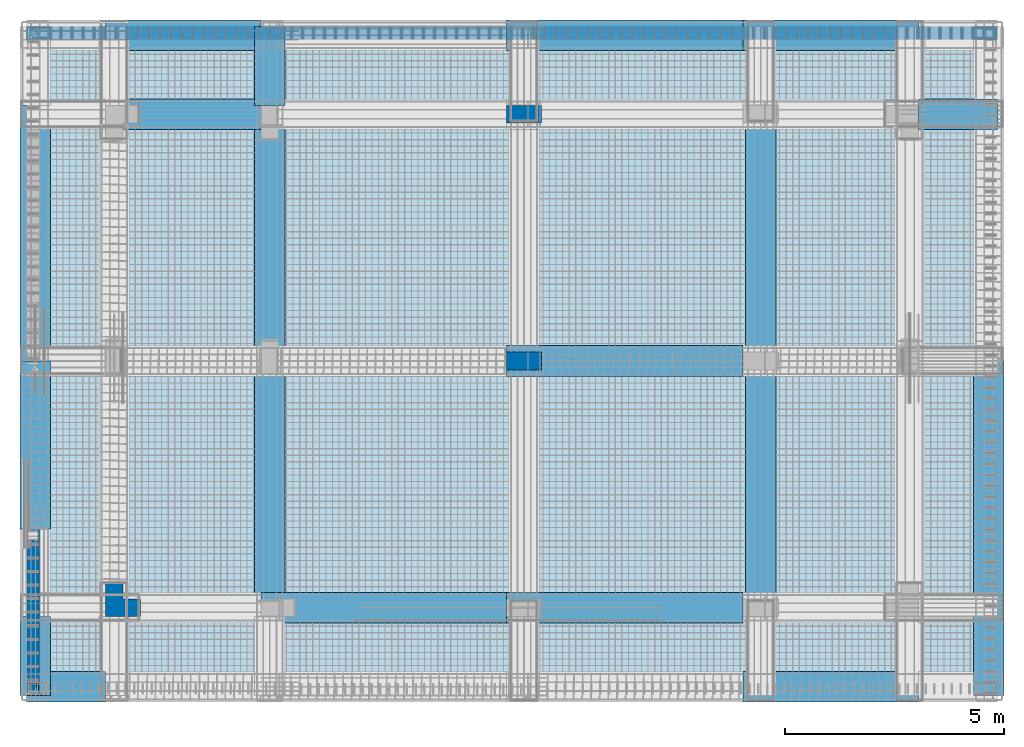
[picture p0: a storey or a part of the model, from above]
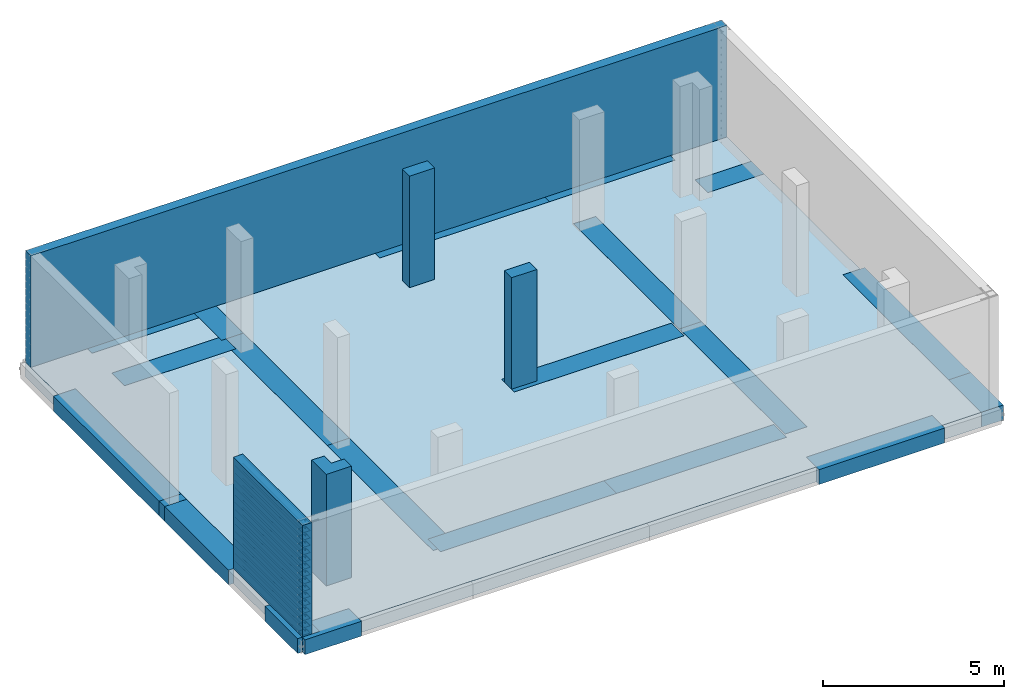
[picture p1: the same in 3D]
Properties of the parts of a building model (IFC4), part 1 of 3

# File
Description: ViewDefinition [CoordinationView]
Made in: IFC file generated by ModeSt (Tecnisoft s.a.s.)

# IfcBuildingStorey (4)
In: Palazzina
Name | Elevation (m)
Storey 0 | 0
Storey 1 | 3.75
Storey 2 | 7
Storey 3 | 11.08

# IfcBeam: 10 R 80x24 T (15)
Type - PredefinedType: BEAM; Material: Calcestruzzo classe C28/35
Description: 10 R 80x24 T - Cemento armato
Pset_BeamCommon - LoadBearing: yes
BaseQuantities - ?: 0.192 m2
Name | In | BaseQuantities, ? (m3) | BaseQuantities, ? (m)
209 | Storey 2 | 1.11936 | 5.83
2 x 206 | Storey 2 | 1.11936 | 5.83
208 | Storey 2 | 1.11936 | 5.83
203 | Storey 2 | 0.4896 | 2.55
203 | Storey 2 | 0.6816 | 3.55
203 | Storey 2 | 1.0368 | 5.4
203 | Storey 2 | 0.5856 | 3.05
203 | Storey 2 | 0.768 | 4
2 x 307 | Storey 3 | 1.13703 | 5.92204
2 x 306 | Storey 3 | 1.13703 | 5.92204
2 x 305 | Storey 3 | 1.13703 | 5.92204

# IfcBeam: 3 R 30x50 T (73)
Type - PredefinedType: BEAM; Material: Calcestruzzo classe C28/35
Description: 3 R 30x50 T - Cemento armato
Pset_BeamCommon - LoadBearing: yes
BaseQuantities - ?: 0.15 m2
Name | In | BaseQuantities, ? (m3) | BaseQuantities, ? (m)
104 | Storey 1 | 0.81 | 5.4
2 x 113 | Storey 1 | 0.8745 | 5.83
111 | Storey 1 | 0.8745 | 5.83
111 | Storey 1 | 0.4095 | 2.73
104 | Storey 1 | 0.435 | 2.9
104 | Storey 1 | 0.405 | 2.7
104 | Storey 1 | 0.6 | 4
2 x 114 | Storey 1 | 0.8745 | 5.83
111 | Storey 1 | 0.465 | 3.1
104 | Storey 1 | 0.5325 | 3.55
2 x 115 | Storey 1 | 0.2025 | 1.35
2 x 106 | Storey 1 | 0.2025 | 1.35
109 | Storey 1 | 0.465 | 3.1
2 x 109 | Storey 1 | 0.2025 | 1.35
2 x 114 | Storey 1 | 0.2025 | 1.35
102 | Storey 1 | 0.6 | 4
2 x 102 | Storey 1 | 0.2025 | 1.35
2 x 113 | Storey 1 | 0.2025 | 1.35
2 x 111 | Storey 1 | 0.2025 | 1.35
2 x 104 | Storey 1 | 0.2025 | 1.35
106 | Storey 1 | 0.6 | 4
106 | Storey 1 | 0.435 | 2.9
106 | Storey 1 | 0.345 | 2.3
109 | Storey 1 | 0.8745 | 5.83
106 | Storey 1 | 0.81 | 5.4
102 | Storey 1 | 0.81 | 5.4
109 | Storey 1 | 0.4095 | 2.73
2 x 115 | Storey 1 | 0.8745 | 5.83
106 | Storey 1 | 0.1875 | 1.25
102 | Storey 1 | 0.5325 | 3.55
102 | Storey 1 | 0.84 | 5.6
106 | Storey 1 | 0.405 | 2.7
201 | Storey 2 | 0.81 | 5.4
204 | Storey 2 | 0.5325 | 3.55
204 | Storey 2 | 0.3825 | 2.55
204 | Storey 2 | 0.4575 | 3.05
204 | Storey 2 | 0.81 | 5.4
201 | Storey 2 | 0.6 | 4
201 | Storey 2 | 0.84 | 5.6
2 x 205 | Storey 2 | 0.8745 | 5.83
201 | Storey 2 | 0.5325 | 3.55
204 | Storey 2 | 0.6 | 4
210 | Storey 2 | 0.6375 | 4.25
210 | Storey 2 | 0.237 | 1.58
210 | Storey 2 | 0.8745 | 5.83
301 | Storey 3 | 0.81 | 5.4
302 | Storey 3 | 0.81 | 5.4
303 | Storey 3 | 0.5325 | 3.55
303 | Storey 3 | 0.81 | 5.4
2 x 308 | Storey 3 | 0.888305 | 5.92204
303 | Storey 3 | 0.84 | 5.6
302 | Storey 3 | 0.6 | 4
301 | Storey 3 | 0.6 | 4
301 | Storey 3 | 0.84 | 5.6
301 | Storey 3 | 0.5325 | 3.55
2 x 304 | Storey 3 | 0.888305 | 5.92204
303 | Storey 3 | 0.6 | 4
302 | Storey 3 | 0.5325 | 3.55
302 | Storey 3 | 0.84 | 5.6

# IfcBeam: 6 R 30x24 T (6)
Type - PredefinedType: BEAM; Material: Calcestruzzo classe C28/35
Description: 6 R 30x24 T - Cemento armato
Pset_BeamCommon - LoadBearing: yes
BaseQuantities - ?: 0.072 m2
Name | In | BaseQuantities, ? (m3) | BaseQuantities, ? (m)
112 | Storey 1 | 0.41976 | 5.83
105 | Storey 1 | 0.1656 | 2.3
105 | Storey 1 | 0.09 | 1.25
110 | Storey 1 | 0.2232 | 3.1
207 | Storey 2 | 0.31752 | 4.41
207 | Storey 2 | 0.10224 | 1.42

# IfcBeam: 8 R 70x50 T (60)
In: Storey 0
Type - PredefinedType: BEAM; Material: Calcestruzzo classe C28/35
Description: 8 R 70x50 T - Cemento armato
Pset_BeamCommon - LoadBearing: yes
BaseQuantities - ?: 0.35 m2
Name | BaseQuantities, ? (m3) | BaseQuantities, ? (m)
506 | 0.105 | 0.3
2 x 501 | 0.63 | 1.8
501 | 1.89 | 5.4
2 x 512 | 0.63 | 1.8
2 x 505 | 0.63 | 1.8
505 | 1.4 | 4
2 x 506 | 0.63 | 1.8
2 x 507 | 0.63 | 1.8
2 x 502 | 0.63 | 1.8
506 | 1.2355 | 3.53
2 x 508 | 0.63 | 1.8
2 x 509 | 0.63 | 1.8
502 | 1.96 | 5.6
501 | 1.96 | 5.6
2 x 510 | 0.63 | 1.8
502 | 1.89 | 5.4
2 x 511 | 0.63 | 1.8
2 x 508 | 2.0405 | 5.83
2 x 509 | 2.0405 | 5.83
2 x 511 | 2.0405 | 5.83
2 x 512 | 2.0405 | 5.83
506 | 0.7 | 2
2 x 507 | 2.0405 | 5.83
2 x 510 | 2.0405 | 5.83
502 | 1.4 | 4
2 x 504 | 0.63 | 1.8
505 | 1.89 | 5.4
504 | 1.89 | 5.4
505 | 1.96 | 5.6
504 | 1.96 | 5.6
505 | 1.2425 | 3.55
2 x 503 | 0.63 | 1.8
503 | 1.89 | 5.4
502 | 1.2425 | 3.55
501 | 1.4 | 4
503 | 1.4 | 4
504 | 1.4 | 4
506 | 2.0405 | 5.83
503 | 1.96 | 5.6
503 | 1.2425 | 3.55
504 | 1.2425 | 3.55
501 | 1.2425 | 3.55

# IfcBeam: 9 R 30x24 T (3)
In: Storey 1
Type - PredefinedType: BEAM; Material: Calcestruzzo classe C28/35
Description: 9 R 30x24 T - Cemento armato
Pset_BeamCommon - LoadBearing: yes
BaseQuantities - ?: 0.072 m2
Name | BaseQuantities, ? (m3) | BaseQuantities, ? (m)
108 | 0.25416 | 3.53
108 | 0.2736 | 3.8
108 | 0.57096 | 7.93

# IfcColumn: 1 R 80x40 P (12)
Type - PredefinedType: COLUMN; Material: Calcestruzzo classe C28/35
Description: 1 R 80x40 P - Cemento armato
Pset_ColumnCommon - LoadBearing: yes
BaseQuantities - ?: 0.32 m2
Name | In | BaseQuantities, ? (m3) | BaseQuantities, ? (m)
12 | Storey 0 | 1.2 | 3.75
6 | Storey 0 | 1.2 | 3.75
7 | Storey 0 | 1.2 | 3.75
10 | Storey 0 | 1.2 | 3.75
7 | Storey 1 | 1.04 | 3.25
6 | Storey 1 | 1.04 | 3.25
12 | Storey 1 | 1.04 | 3.25
10 | Storey 1 | 1.04 | 3.25
12 | Storey 2 | 0.9728 | 3.04
10 | Storey 2 | 1.3056 | 4.08
7 | Storey 2 | 1.3056 | 4.08
6 | Storey 2 | 1.3056 | 4.08

# IfcColumn: 2 R 40x80 P (21)
Type - PredefinedType: COLUMN; Material: Calcestruzzo classe C28/35
Description: 2 R 40x80 P - Cemento armato
Pset_ColumnCommon - LoadBearing: yes
BaseQuantities - ?: 0.32 m2
Name | In | BaseQuantities, ? (m3) | BaseQuantities, ? (m)
9 | Storey 0 | 1.2 | 3.75
4 | Storey 0 | 1.2 | 3.75
13 | Storey 0 | 1.2 | 3.75
14 | Storey 0 | 1.2 | 3.75
2 | Storey 0 | 1.2 | 3.75
3 | Storey 0 | 1.2 | 3.75
8 | Storey 0 | 1.2 | 3.75
9 | Storey 1 | 1.04 | 3.25
4 | Storey 1 | 1.04 | 3.25
13 | Storey 1 | 1.04 | 3.25
8 | Storey 1 | 1.04 | 3.25
2 | Storey 1 | 1.04 | 3.25
3 | Storey 1 | 1.04 | 3.25
14 | Storey 1 | 1.04 | 3.25
14 | Storey 2 | 0.9728 | 3.04
13 | Storey 2 | 0.9728 | 3.04
9 | Storey 2 | 1.3056 | 4.08
2 | Storey 2 | 0.9728 | 3.04
3 | Storey 2 | 0.9728 | 3.04
4 | Storey 2 | 0.9728 | 3.04
8 | Storey 2 | 1.3056 | 4.08

# IfcColumn: 4 L 40x40x80x40 P (6)
Type - PredefinedType: COLUMN; Material: Calcestruzzo classe C28/35
Description: 4 L 40x40x80x40 P - Cemento armato
Pset_ColumnCommon - LoadBearing: yes
BaseQuantities - ?: 0.48 m2
Name | In | BaseQuantities, ? (m3) | BaseQuantities, ? (m)
1 | Storey 0 | 1.8 | 3.75
5 | Storey 0 | 1.8 | 3.75
1 | Storey 1 | 1.56 | 3.25
5 | Storey 1 | 1.56 | 3.25
1 | Storey 2 | 1.4592 | 3.04
5 | Storey 2 | 1.4592 | 3.04

# IfcColumn: 5 Ldx 40x40x80x40 P (6)
Type - PredefinedType: COLUMN; Material: Calcestruzzo classe C28/35
Description: 5 Ldx 40x40x80x40 P - Cemento armato
Pset_ColumnCommon - LoadBearing: yes
BaseQuantities - ?: 0.48 m2
Name | In | BaseQuantities, ? (m3) | BaseQuantities, ? (m)
15 | Storey 0 | 1.8 | 3.75
11 | Storey 0 | 1.8 | 3.75
11 | Storey 1 | 1.56 | 3.25
15 | Storey 1 | 1.56 | 3.25
11 | Storey 2 | 1.4592 | 3.04
15 | Storey 2 | 1.4592 | 3.04

# IfcFooting: 3 Spess. 0.5 S W
In: Storey 0
Type - PredefinedType: STRIP_FOOTING
Description: 3 Spess. 0.5 S W; Material: Calcestruzzo classe C28/35 0.5 m
Pset_WallCommon - LoadBearing: yes
BaseQuantities - ?: 169.005 m3

# IfcReinforcingBar (563)
SteelGrade: B450C
Name | In | NominalDiameter (m) | CrossSectionArea (m2) | BarLength (m)
5 x  | Storey 0 | 0.012 | 0.0001131 | 3.957
5 x  | Storey 0 | 0.012 | 0.0001131 | 1.18782
2 x  | Storey 0 | 0.01 | 0.00007854 | 22.09
5 x  | Storey 0 | 0.01 | 0.00007854 | 1.21121
4 x  | Storey 0 | 0.016 | 0.00020106 | 3.952
4 x  | Storey 0 | 0.016 | 0.00020106 | 1.17543
 | Storey 0 | 0.01 | 0.00007854 | 1.18177
 | Storey 0 | 0.01 | 0.00007854 | 15.2
3 x  | Storey 0 | 0.01 | 0.00007854 | 1.18178
 | Storey 0 | 0.01 | 0.00007854 | 7.87
 | Storey 0 | 0.01 | 0.00007854 | 3.74
10 x  | Storey 2 | 0.02 | 0.00031416 | 1.59754
4 x  | Storey 2 | 0.016 | 0.00020106 | 1.60193
5 x  | Storey 2 | 0.02 | 0.00031416 | 4.73591
4 x  | Storey 2 | 0.016 | 0.00020106 | 4.73591
6 x  | Storey 2 | 0.02 | 0.00031416 | 4.23591
4 x  | Storey 2 | 0.016 | 0.00020106 | 4.23591
10 x  | Storey 2 | 0.016 | 0.00020106 | 3.32943
2 x  | Storey 2 | 0.008 | 0.000050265 | 0.978432
19 x  | Storey 2 | 0.008 | 0.000050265 | 2.37879
 | Storey 2 | 0.008 | 0.000050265 | 0.578429
4 x  | Storey 2 | 0.018 | 0.00025447 | 1.51973
4 x  | Storey 2 | 0.018 | 0.00025447 | 4.47
3 x  | Storey 2 | 0.018 | 0.00025447 | 3.97
 | Storey 2 | 0.008 | 0.000050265 | 1.42681
7 x  | Storey 2 | 0.008 | 0.000050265 | 0.978429
 | Storey 2 | 0.018 | 0.00025447 | 3.32723
3 x  | Storey 2 | 0.008 | 0.000050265 | 1.42683
2 x  | Storey 2 | 0.008 | 0.000050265 | 0.978428
3 x  | Storey 2 | 0.008 | 0.000050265 | 1.4215
5 x  | Storey 2 | 0.02 | 0.00031416 | 4.55
4 x  | Storey 2 | 0.02 | 0.00031416 | 4.05
 | Storey 2 | 0.008 | 0.000050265 | 1.23963
2 x  | Storey 2 | 0.008 | 0.000050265 | 0.97843
3 x  | Storey 2 | 0.008 | 0.000050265 | 1.23324
 | Storey 2 | 0.008 | 0.000050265 | 0.978434
 | Storey 2 | 0.008 | 0.000050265 | 0.578426
2 x  | Storey 2 | 0.018 | 0.00025447 | 4.36723
 | Storey 2 | 0.008 | 0.000050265 | 1.36284
3 x  | Storey 2 | 0.016 | 0.00020106 | 4.36943
2 x  | Storey 2 | 0.008 | 0.000050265 | 1.4295
 | Storey 2 | 0.008 | 0.000050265 | 1.42417
 | Storey 2 | 0.016 | 0.00020106 | 1.44193
 | Storey 2 | 0.016 | 0.00020106 | 4.39
 | Storey 2 | 0.016 | 0.00020106 | 3.89
4 x  | Storey 2 | 0.01 | 0.00007854 | 2.3898
 | Storey 2 | 0.01 | 0.00007854 | 1.23626
2 x  | Storey 2 | 0.01 | 0.00007854 | 0.98443
2 x  | Storey 2 | 0.008 | 0.000050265 | 1.42416
2 x  | Storey 2 | 0.016 | 0.00020106 | 1.52193
2 x  | Storey 2 | 0.016 | 0.00020106 | 4.47
 | Storey 2 | 0.018 | 0.00025447 | 4.13732
 | Storey 2 | 0.016 | 0.00020106 | 4.13732
 | Storey 2 | 0.01 | 0.00007854 | 1.42451
 | Storey 2 | 0.008 | 0.000050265 | 1.36283
 | Storey 2 | 0.008 | 0.000050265 | 0.578428
 | Storey 2 | 0.016 | 0.00020106 | 3.97
 | Storey 2 | 0.02 | 0.00031416 | 3.32504
 | Storey 2 | 0.008 | 0.000050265 | 1.23964
 | Storey 2 | 0.008 | 0.000050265 | 0.978433
 | Storey 2 | 0.008 | 0.000050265 | 0.57843
 | Storey 2 | 0.01 | 0.00007854 | 0.984432
 | Storey 2 | 0.01 | 0.00007854 | 0.584429
 | Storey 0 | 0.014 | 0.00015394 | 22.8032
 | Storey 0 | 0.014 | 0.00015394 | 15.9132
 | Storey 2 | 0.014 | 0.00015394 | 1.51321
 | Storey 2 | 0.014 | 0.00015394 | 13.9632
 | Storey 2 | 0.014 | 0.00015394 | 1.53321
 | Storey 2 | 0.014 | 0.00015394 | 3.11321
7 x  | Storey 1 | 0.008 | 0.000050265 | 1.5868
2 x  | Storey 1 | 0.016 | 0.00020106 | 8.29448
 | Storey 1 | 0.016 | 0.00020106 | 8.19121
2 x  | Storey 1 | 0.018 | 0.00025447 | 6.59121
 | Storey 1 | 0.02 | 0.00031416 | 5.19121
 | Storey 1 | 0.016 | 0.00020106 | 3.58285
 | Storey 1 | 0.02 | 0.00031416 | 11.8812
2 x  | Storey 1 | 0.018 | 0.00025447 | 11.9512
2 x  | Storey 1 | 0.016 | 0.00020106 | 3.36285
4 x  | Storey 1 | 0.012 | 0.0001131 | 2.52121
 | Storey 1 | 0.012 | 0.0001131 | 4.72121
3 x  | Storey 1 | 0.012 | 0.0001131 | 6.77121
2 x  | Storey 1 | 0.012 | 0.0001131 | 6.57121
3 x  | Storey 1 | 0.012 | 0.0001131 | 4.37121
3 x  | Storey 1 | 0.014 | 0.00015394 | 2.69121
 | Storey 1 | 0.016 | 0.00020106 | 2.79448
 | Storey 1 | 0.018 | 0.00025447 | 8.19121
 | Storey 1 | 0.02 | 0.00031416 | 5.69121
2 x  | Storey 1 | 0.016 | 0.00020106 | 3.18285
 | Storey 1 | 0.018 | 0.00025447 | 11.9812
 | Storey 1 | 0.016 | 0.00020106 | 8.32121
 | Storey 1 | 0.02 | 0.00031416 | 7.19121
 | Storey 1 | 0.016 | 0.00020106 | 2.96285
4 x  | Storey 1 | 0.012 | 0.0001131 | 2.12121
2 x  | Storey 1 | 0.012 | 0.0001131 | 4.32121
 | Storey 1 | 0.012 | 0.0001131 | 6.57122
 | Storey 1 | 0.018 | 0.00025447 | 3.19121
 | Storey 1 | 0.016 | 0.00020106 | 2.29448
 | Storey 1 | 0.008 | 0.000050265 | 1.06683
 | Storey 1 | 0.016 | 0.00020106 | 4.09721
 | Storey 1 | 0.018 | 0.00025447 | 11.5912
 | Storey 1 | 0.018 | 0.00025447 | 8.42831
 | Storey 1 | 0.018 | 0.00025447 | 6.8643
 | Storey 1 | 0.016 | 0.00020106 | 9.19121
 | Storey 1 | 0.02 | 0.00031416 | 7.19122
 | Storey 1 | 0.018 | 0.00025447 | 4.19122
 | Storey 1 | 0.014 | 0.00015394 | 3.19121
3 x  | Storey 1 | 0.008 | 0.000050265 | 1.06682
 | Storey 1 | 0.016 | 0.00020106 | 8.54503
 | Storey 1 | 0.016 | 0.00020106 | 7.94503
 | Storey 1 | 0.018 | 0.00025447 | 9.00197
 | Storey 1 | 0.018 | 0.00025447 | 9.14976
 | Storey 1 | 0.018 | 0.00025447 | 9.90276
 | Storey 1 | 0.018 | 0.00025447 | 9.16121
2 x  | Storey 1 | 0.016 | 0.00020106 | 4.59121
3 x  | Storey 1 | 0.012 | 0.0001131 | 6.50121
3 x  | Storey 1 | 0.012 | 0.0001131 | 6.70121
 | Storey 1 | 0.016 | 0.00020106 | 3.64721
 | Storey 1 | 0.018 | 0.00025447 | 9.0443
 | Storey 1 | 0.018 | 0.00025447 | 9.84121
 | Storey 1 | 0.018 | 0.00025447 | 9.84741
 | Storey 1 | 0.018 | 0.00025447 | 9.49121
 | Storey 1 | 0.018 | 0.00025447 | 4.17109
2 x  | Storey 1 | 0.016 | 0.00020106 | 3.95121
 | Storey 1 | 0.012 | 0.0001131 | 2.52122
 | Storey 1 | 0.02 | 0.00031416 | 6.22721
 | Storey 1 | 0.014 | 0.00015394 | 1.97562
2 x  | Storey 1 | 0.018 | 0.00025447 | 8.9443
 | Storey 1 | 0.018 | 0.00025447 | 7.64739
2 x  | Storey 1 | 0.018 | 0.00025447 | 9.42831
 | Storey 1 | 0.018 | 0.00025447 | 8.18739
 | Storey 1 | 0.016 | 0.00020106 | 3.93121
 | Storey 1 | 0.016 | 0.00020106 | 3.63121
2 x  | Storey 1 | 0.012 | 0.0001131 | 6.40121
 | Storey 1 | 0.008 | 0.000050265 | 1.58681
 | Storey 1 | 0.018 | 0.00025447 | 8.71476
 | Storey 1 | 0.016 | 0.00020106 | 4.15121
 | Storey 1 | 0.018 | 0.00025447 | 10.0912
 | Storey 1 | 0.016 | 0.00020106 | 9.11285
 | Storey 1 | 0.02 | 0.00031416 | 9.69122
 | Storey 1 | 0.016 | 0.00020106 | 4.59122
4 x  | Storey 2 | 0.008 | 0.000050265 | 1.5868
2 x  | Storey 2 | 0.018 | 0.00025447 | 11.9412
 | Storey 2 | 0.02 | 0.00031416 | 11.0958
 | Storey 2 | 0.018 | 0.00025447 | 6.52121
 | Storey 2 | 0.018 | 0.00025447 | 5.87121
 | Storey 2 | 0.018 | 0.00025447 | 11.9612
 | Storey 2 | 0.018 | 0.00025447 | 11.9512
 | Storey 2 | 0.018 | 0.00025447 | 6.58121
 | Storey 2 | 0.018 | 0.00025447 | 6.33121
2 x  | Storey 2 | 0.012 | 0.0001131 | 4.37121
 | Storey 2 | 0.012 | 0.0001131 | 4.72121
2 x  | Storey 2 | 0.012 | 0.0001131 | 6.77121
 | Storey 2 | 0.012 | 0.0001131 | 6.57122
4 x  | Storey 2 | 0.008 | 0.000050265 | 1.57214
 | Storey 2 | 0.016 | 0.00020106 | 10.0912
 | Storey 2 | 0.016 | 0.00020106 | 8.19121
 | Storey 2 | 0.016 | 0.00020106 | 10.5912
2 x  | Storey 2 | 0.018 | 0.00025447 | 7.19121
 | Storey 2 | 0.016 | 0.00020106 | 7.19121
 | Storey 2 | 0.02 | 0.00031416 | 7.19121
 | Storey 2 | 0.02 | 0.00031416 | 3.59121
2 x  | Storey 2 | 0.018 | 0.00025447 | 3.59121
 | Storey 2 | 0.016 | 0.00020106 | 3.59121
 | Storey 2 | 0.02 | 0.00031416 | 11.9012
 | Storey 2 | 0.018 | 0.00025447 | 6.94121
 | Storey 2 | 0.018 | 0.00025447 | 5.45976
 | Storey 2 | 0.018 | 0.00025447 | 11.9712
 | Storey 2 | 0.018 | 0.00025447 | 11.4598
 | Storey 2 | 0.018 | 0.00025447 | 6.40121
 | Storey 2 | 0.018 | 0.00025447 | 5.95121
 | Storey 2 | 0.012 | 0.0001131 | 6.57121
 | Storey 2 | 0.012 | 0.0001131 | 4.32121
2 x  | Storey 2 | 0.02 | 0.00031416 | 12.4312
2 x  | Storey 2 | 0.02 | 0.00031416 | 11.9912
 | Storey 2 | 0.012 | 0.0001131 | 6.50121
2 x  | Storey 2 | 0.012 | 0.0001131 | 6.70121
 | Storey 2 | 0.016 | 0.00020106 | 11.9072
 | Storey 2 | 0.02 | 0.00031416 | 8.69121
 | Storey 2 | 0.018 | 0.00025447 | 8.69121
4 x  | Storey 2 | 0.018 | 0.00025447 | 4.59121
2 x  | Storey 2 | 0.016 | 0.00020106 | 4.59121
3 x  | Storey 2 | 0.02 | 0.00031416 | 4.59121
 | Storey 2 | 0.008 | 0.000050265 | 1.06682
 | Storey 2 | 0.016 | 0.00020106 | 6.47721
2 x  | Storey 2 | 0.02 | 0.00031416 | 4.64876
2 x  | Storey 2 | 0.018 | 0.00025447 | 4.64876
 | Storey 2 | 0.012 | 0.0001131 | 5.72788
5 x  | Storey 3 | 0.008 | 0.000050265 | 1.5868
 | Storey 3 | 0.018 | 0.00025447 | 11.9598
 | Storey 3 | 0.018 | 0.00025447 | 10.9598
 | Storey 3 | 0.018 | 0.00025447 | 6.33121
 | Storey 3 | 0.018 | 0.00025447 | 5.59121
2 x  | Storey 3 | 0.018 | 0.00025447 | 10.7443
2 x  | Storey 3 | 0.018 | 0.00025447 | 10.4943
 | Storey 3 | 0.018 | 0.00025447 | 5.97121
 | Storey 3 | 0.018 | 0.00025447 | 5.3443
 | Storey 3 | 0.012 | 0.0001131 | 4.72121
3 x  | Storey 3 | 0.012 | 0.0001131 | 4.40121
2 x  | Storey 3 | 0.012 | 0.0001131 | 6.60122
 | Storey 3 | 0.012 | 0.0001131 | 6.80122
 | Storey 3 | 0.016 | 0.00020106 | 11.0912
 | Storey 3 | 0.016 | 0.00020106 | 8.29448
 | Storey 3 | 0.02 | 0.00031416 | 5.09121
2 x  | Storey 3 | 0.012 | 0.0001131 | 4.32121
2 x  | Storey 3 | 0.012 | 0.0001131 | 6.80121
 | Storey 3 | 0.016 | 0.00020106 | 2.79448
2 x  | Storey 3 | 0.02 | 0.00031416 | 11.0912
 | Storey 3 | 0.016 | 0.00020106 | 5.09122
 | Storey 3 | 0.018 | 0.00025447 | 5.09121
 | Storey 3 | 0.02 | 0.00031416 | 10.6258
 | Storey 3 | 0.02 | 0.00031416 | 10.8758
 | Storey 3 | 0.016 | 0.00020106 | 5.21285
 | Storey 3 | 0.02 | 0.00031416 | 5.02576
 | Storey 3 | 0.012 | 0.0001131 | 6.60121
 | Storey 3 | 0.02 | 0.00031416 | 4.19122
 | Storey 3 | 0.016 | 0.00020106 | 4.19122
 | Storey 3 | 0.018 | 0.00025447 | 4.19122
 | Storey 3 | 0.016 | 0.00020106 | 2.29448
 | Storey 3 | 0.014 | 0.00015394 | 3.19122
2 x  | Storey 3 | 0.018 | 0.00025447 | 7.49081
2 x  | Storey 3 | 0.02 | 0.00031416 | 12.1783
 | Storey 3 | 0.018 | 0.00025447 | 12.1783
2 x  | Storey 3 | 0.012 | 0.0001131 | 6.16672
2 x  | Storey 3 | 0.012 | 0.0001131 | 6.36987
3 x  | Storey 3 | 0.008 | 0.000050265 | 1.57214
 | Storey 3 | 0.016 | 0.00020106 | 7.589
 | Storey 3 | 0.016 | 0.00020106 | 7.09316
5 x  | Storey 3 | 0.02 | 0.00031416 | 8.69116
3 x  | Storey 3 | 0.016 | 0.00020106 | 8.69116
 | Storey 3 | 0.018 | 0.00025447 | 4.21654
 | Storey 3 | 0.016 | 0.00020106 | 4.21654
3 x  | Storey 3 | 0.02 | 0.00031416 | 4.59273
2 x  | Storey 3 | 0.018 | 0.00025447 | 4.59273
2 x  | Storey 3 | 0.018 | 0.00025447 | 6.63307
2 x  | Storey 3 | 0.018 | 0.00025447 | 8.69116
 | Storey 3 | 0.018 | 0.00025447 | 4.26733
 | Storey 3 | 0.016 | 0.00020106 | 4.26733
2 x  | Storey 3 | 0.02 | 0.00031416 | 4.58906
 | Storey 3 | 0.016 | 0.00020106 | 4.58906
3 x  | Storey 3 | 0.016 | 0.00020106 | 4.59273
 | Storey 3 | 0.018 | 0.00025447 | 4.58906
 | Storey 3 | 0.02 | 0.00031416 | 7.62227
 | Storey 3 | 0.02 | 0.00031416 | 7.62226
2 x  | Storey 3 | 0.016 | 0.00020106 | 3.58906
 | Storey 3 | 0.016 | 0.00020106 | 2.44898
8 x  | Storey 0 | 0.01 | 0.00007854 | 1.85514
2 x  | Storey 0 | 0.016 | 0.00020106 | 11.7241
2 x  | Storey 0 | 0.016 | 0.00020106 | 6.70876
2 x  | Storey 0 | 0.016 | 0.00020106 | 6.79003
2 x  | Storey 0 | 0.012 | 0.0001131 | 6.87621
2 x  | Storey 0 | 0.012 | 0.0001131 | 6.65712
2 x  | Storey 0 | 0.012 | 0.0001131 | 11.8103
 | Storey 0 | 0.016 | 0.00020106 | 9.35121
 | Storey 0 | 0.016 | 0.00020106 | 7.30121
 | Storey 0 | 0.016 | 0.00020106 | 7.60121
3 x  | Storey 0 | 0.016 | 0.00020106 | 2.81503
 | Storey 0 | 0.016 | 0.00020106 | 9.22121
 | Storey 0 | 0.02 | 0.00031416 | 7.15121
 | Storey 0 | 0.016 | 0.00020106 | 7.15121
 | Storey 0 | 0.016 | 0.00020106 | 9.48122
4 x  | Storey 0 | 0.012 | 0.0001131 | 3.66121
 | Storey 0 | 0.012 | 0.0001131 | 4.84121
 | Storey 0 | 0.012 | 0.0001131 | 6.92621
3 x  | Storey 0 | 0.012 | 0.0001131 | 6.6603
2 x  | Storey 0 | 0.012 | 0.0001131 | 3.99121
 | Storey 0 | 0.016 | 0.00020106 | 10.1312
 | Storey 0 | 0.016 | 0.00020106 | 6.97121
 | Storey 0 | 0.016 | 0.00020106 | 7.71121
 | Storey 0 | 0.016 | 0.00020106 | 9.97121
 | Storey 0 | 0.016 | 0.00020106 | 6.81831
 | Storey 0 | 0.016 | 0.00020106 | 9.50121
4 x  | Storey 0 | 0.012 | 0.0001131 | 3.26121
2 x  | Storey 0 | 0.012 | 0.0001131 | 4.90121
 | Storey 0 | 0.012 | 0.0001131 | 7.35122
 | Storey 0 | 0.012 | 0.0001131 | 4.49121
4 x  | Storey 0 | 0.01 | 0.00007854 | 1.85515
 | Storey 0 | 0.016 | 0.00020106 | 7.97121
 | Storey 0 | 0.016 | 0.00020106 | 8.82121
 | Storey 0 | 0.016 | 0.00020106 | 7.82121
 | Storey 0 | 0.016 | 0.00020106 | 7.50121
 | Storey 0 | 0.016 | 0.00020106 | 9.61122
 | Storey 0 | 0.016 | 0.00020106 | 8.86121
 | Storey 0 | 0.012 | 0.0001131 | 4.44121
 | Storey 0 | 0.012 | 0.0001131 | 7.35121
 | Storey 0 | 0.016 | 0.00020106 | 10.0912
 | Storey 0 | 0.016 | 0.00020106 | 4.57285
 | Storey 0 | 0.02 | 0.00031416 | 4.94649
 | Storey 0 | 0.018 | 0.00025447 | 2.19121
3 x  | Storey 0 | 0.016 | 0.00020106 | 2.19121
 | Storey 0 | 0.018 | 0.00025447 | 8.41076
 | Storey 0 | 0.012 | 0.0001131 | 4.52121
 | Storey 0 | 0.012 | 0.0001131 | 9.03121
2 x  | Storey 0 | 0.016 | 0.00020106 | 9.09121
4 x  | Storey 0 | 0.016 | 0.00020106 | 8.64503
4 x  | Storey 0 | 0.016 | 0.00020106 | 8.59121
2 x  | Storey 0 | 0.02 | 0.00031416 | 2.19121
2 x  | Storey 0 | 0.012 | 0.0001131 | 6.02121
3 x  | Storey 0 | 0.012 | 0.0001131 | 5.92336
 | Storey 0 | 0.016 | 0.00020106 | 9.83121
 | Storey 0 | 0.016 | 0.00020106 | 9.65121
 | Storey 0 | 0.016 | 0.00020106 | 9.63121
 | Storey 0 | 0.016 | 0.00020106 | 9.68121
 | Storey 0 | 0.012 | 0.0001131 | 6.52121
 | Storey 0 | 0.016 | 0.00020106 | 9.86121
2 x  | Storey 0 | 0.016 | 0.00020106 | 9.59121
 | Storey 0 | 0.016 | 0.00020106 | 9.73121
 | Storey 0 | 0.016 | 0.00020106 | 9.61121
2 x  | Storey 0 | 0.012 | 0.0001131 | 6.98121
 | Storey 0 | 0.016 | 0.00020106 | 9.34121
 | Storey 0 | 0.016 | 0.00020106 | 9.56121
 | Storey 0 | 0.016 | 0.00020106 | 9.13121
 | Storey 0 | 0.012 | 0.0001131 | 3.66122
 | Storey 0 | 0.012 | 0.0001131 | 8.73122

# IfcSlab: 1 Hs 0.3 Sc 0.04 Qps 390 Qpn 250 QA 200 (10)
In: Storey 1
Type - PredefinedType: FLOOR; Material: Concrete
Description: 1 Hs 0.3 Sc 0.04 Qps 390 Qpn 250 QA 200 - Altezza solaio 0.300000 - Spessore cappa 0.040000 -
Pset_SlabCommon - LoadBearing: yes
BaseQuantities - ?: 0.3 m
Name | BaseQuantities, ? (m2) | BaseQuantities, ? (m3)
100 | 20.6965 | 6.20895
101 | -23.32 | -6.996
103 | 31.482 | 9.4446
104 | 32.648 | 9.7944
105 | -15.741 | -4.7223
106 | -9.6915 | -2.90745
107 | -3.875 | -1.1625
110 | -31.482 | -9.4446
111 | 23.32 | 6.996
112 | -16.907 | -5.0721

# IfcSlab: 2 Hs 0.3 Sc 0.04 Qps 300 Qpn 90 QA 200 (8)
In: Storey 3
Type - PredefinedType: FLOOR; Material: Concrete
Description: 2 Hs 0.3 Sc 0.04 Qps 300 Qpn 90 QA 200 - Altezza solaio 0.300000 - Spessore cappa 0.040000 -
Pset_SlabCommon - LoadBearing: yes
BaseQuantities - ?: 0.3 m
Name | BaseQuantities, ? (m2) | BaseQuantities, ? (m3)
300 | 31.482 | 9.4446
301 | 31.482 | 9.4446
302 | 20.6965 | 6.20895
303 | 32.648 | 9.7944
304 | 23.32 | 6.996
305 | 20.6965 | 6.20895
306 | 32.648 | 9.7944
307 | 23.32 | 6.996

# IfcSlab: 2 Spess. 0.2 S F
In: Storey 2
Type - PredefinedType: BASESLAB
Description: 2 Spess. 0.2 S F; Material: Calcestruzzo classe C28/35 0.2 m
Pset_WallCommon - LoadBearing: yes
BaseQuantities - ?: 8.30999 m3

# IfcSlab: 3 Hs 0.1 Qps 250 Qpn 100 QA 200 (16)
In: Storey 1
Type - PredefinedType: FLOOR; Material: Concrete
Description: 3 Hs 0.1 Qps 250 Qpn 100 QA 200 - Altezza solaio 0.100000 - Spessore cappa 0.000000 -
Pset_SlabCommon - LoadBearing: yes
BaseQuantities - ?: 0.1 m
Name | BaseQuantities, ? (m2) | BaseQuantities, ? (m3)
102 | -7.29 | -0.729
108 | -7.56 | -0.756
109 | -4.7925 | -0.47925
113 | -5.4 | -0.54
114 | -1.8225 | -0.18225
115 | -7.8705 | -0.78705
116 | 7.8705 | 0.78705
117 | -1.8225 | -0.18225
118 | -5.4 | -0.54
119 | -7.29 | -0.729
120 | -7.56 | -0.756
121 | -4.7925 | -0.47925
122 | -1.8225 | -0.18225
123 | 7.8705 | 0.78705
124 | -7.8705 | -0.78705
125 | -1.8225 | -0.18225

# IfcSlab: 4 Hs 0.3 Sc 0.04 Qps 300 Qpn 250 QA 200 (6)
In: Storey 2
Type - PredefinedType: FLOOR; Material: Concrete
Description: 4 Hs 0.3 Sc 0.04 Qps 300 Qpn 250 QA 200 - Altezza solaio 0.300000 - Spessore cappa 0.040000 -
Pset_SlabCommon - LoadBearing: yes
BaseQuantities - ?: 0.3 m
Name | BaseQuantities, ? (m2) | BaseQuantities, ? (m3)
200 | 23.32 | 6.996
201 | 31.482 | 9.4446
202 | -14.8665 | -4.45995
203 | 32.648 | 9.7944
204 | 20.6965 | 6.20895
205 | -20.6965 | -6.20895

# IfcWall (21)
Pset_WallCommon - LoadBearing: yes
Name | In
106 | Storey 1
110 | Storey 1
111 | Storey 1
104 | Storey 1
103 | Storey 1
112 | Storey 1
113 | Storey 1
108 | Storey 1
107 | Storey 1
203 | Storey 2
204 | Storey 2
206 | Storey 2
105 | Storey 2
308 | Storey 2
102 | Storey 2
101 | Storey 2
213 | Storey 2
212 | Storey 2
109 | Storey 2
208 | Storey 2
207 | Storey 2

# IfcWallStandardCase: 1 Spess. 0.3 P F (5)
In: Storey 0
Type - PredefinedType: STANDARD
Material: Calcestruzzo classe C28/35 0.3 m
Pset_WallCommon - LoadBearing: yes
BaseQuantities - ?: 3.75 m
Name | Description | BaseQuantities, ? (m2) | BaseQuantities, ? (m3)
113 | Wall number 113 | 1.14 | 4.275
112 | Wall number 112 | 2.379 | 8.92125
111 | Wall number 111 | 6.645 | 24.9188
110 | Wall number 110 | 4.578 | 17.1675
109 | Wall number 109 | 6.645 | 24.9188

# IfcReinforcingBarType, no part of this type: type
PredefinedType: MAIN; NominalDiameter: 0.012 m; CrossSectionArea: 0.0001131 m2; BarLength: 3.957 m; Material: Steel

# IfcReinforcingBarType, no part of this type: type
PredefinedType: MAIN; NominalDiameter: 0.012 m; CrossSectionArea: 0.0001131 m2; BarLength: 1.18782 m; Material: Steel

# IfcReinforcingBarType, no part of this type: type
PredefinedType: LIGATURE; NominalDiameter: 0.01 m; CrossSectionArea: 0.00007854 m2; BarLength: 22.09 m; Material: Steel

# IfcReinforcingBarType, no part of this type: type
PredefinedType: LIGATURE; NominalDiameter: 0.01 m; CrossSectionArea: 0.00007854 m2; BarLength: 1.21121 m; Material: Steel

# IfcReinforcingBarType, no part of this type: type
PredefinedType: MAIN; NominalDiameter: 0.016 m; CrossSectionArea: 0.00020106 m2; BarLength: 3.952 m; Material: Steel

# IfcReinforcingBarType, no part of this type: type
PredefinedType: MAIN; NominalDiameter: 0.016 m; CrossSectionArea: 0.00020106 m2; BarLength: 1.17543 m; Material: Steel

# IfcReinforcingBarType, no part of this type: type
PredefinedType: LIGATURE; NominalDiameter: 0.01 m; CrossSectionArea: 0.00007854 m2; BarLength: 1.18177 m; Material: Steel

# IfcReinforcingBarType, no part of this type: type
PredefinedType: MAIN; NominalDiameter: 0.012 m; CrossSectionArea: 0.0001131 m2; BarLength: 3.957 m; Material: Steel

# IfcReinforcingBarType, no part of this type: type
PredefinedType: MAIN; NominalDiameter: 0.012 m; CrossSectionArea: 0.0001131 m2; BarLength: 1.18782 m; Material: Steel

# IfcReinforcingBarType, no part of this type: type
PredefinedType: LIGATURE; NominalDiameter: 0.01 m; CrossSectionArea: 0.00007854 m2; BarLength: 15.2 m; Material: Steel

# IfcReinforcingBarType, no part of this type: type
PredefinedType: LIGATURE; NominalDiameter: 0.01 m; CrossSectionArea: 0.00007854 m2; BarLength: 1.21121 m; Material: Steel

# IfcReinforcingBarType, no part of this type: type
PredefinedType: MAIN; NominalDiameter: 0.012 m; CrossSectionArea: 0.0001131 m2; BarLength: 3.957 m; Material: Steel

# IfcReinforcingBarType, no part of this type: type
PredefinedType: MAIN; NominalDiameter: 0.012 m; CrossSectionArea: 0.0001131 m2; BarLength: 1.18782 m; Material: Steel

# IfcReinforcingBarType, no part of this type: type
PredefinedType: LIGATURE; NominalDiameter: 0.01 m; CrossSectionArea: 0.00007854 m2; BarLength: 22.09 m; Material: Steel

# IfcReinforcingBarType, no part of this type: type
PredefinedType: LIGATURE; NominalDiameter: 0.01 m; CrossSectionArea: 0.00007854 m2; BarLength: 1.21121 m; Material: Steel

# IfcReinforcingBarType, no part of this type: type
PredefinedType: MAIN; NominalDiameter: 0.016 m; CrossSectionArea: 0.00020106 m2; BarLength: 3.952 m; Material: Steel

# IfcReinforcingBarType, no part of this type: type
PredefinedType: MAIN; NominalDiameter: 0.016 m; CrossSectionArea: 0.00020106 m2; BarLength: 1.17543 m; Material: Steel

# IfcReinforcingBarType, no part of this type: type
PredefinedType: LIGATURE; NominalDiameter: 0.01 m; CrossSectionArea: 0.00007854 m2; BarLength: 1.18178 m; Material: Steel

# IfcReinforcingBarType, no part of this type: type
PredefinedType: MAIN; NominalDiameter: 0.012 m; CrossSectionArea: 0.0001131 m2; BarLength: 3.957 m; Material: Steel

# IfcReinforcingBarType, no part of this type: type
PredefinedType: MAIN; NominalDiameter: 0.012 m; CrossSectionArea: 0.0001131 m2; BarLength: 1.18782 m; Material: Steel

# IfcReinforcingBarType, no part of this type: type
PredefinedType: LIGATURE; NominalDiameter: 0.01 m; CrossSectionArea: 0.00007854 m2; BarLength: 7.87 m; Material: Steel

# IfcReinforcingBarType, no part of this type: type
PredefinedType: LIGATURE; NominalDiameter: 0.01 m; CrossSectionArea: 0.00007854 m2; BarLength: 1.21121 m; Material: Steel

# IfcReinforcingBarType, no part of this type: type
PredefinedType: MAIN; NominalDiameter: 0.016 m; CrossSectionArea: 0.00020106 m2; BarLength: 3.952 m; Material: Steel

# IfcReinforcingBarType, no part of this type: type
PredefinedType: MAIN; NominalDiameter: 0.016 m; CrossSectionArea: 0.00020106 m2; BarLength: 1.17543 m; Material: Steel

# IfcReinforcingBarType, no part of this type: type
PredefinedType: LIGATURE; NominalDiameter: 0.01 m; CrossSectionArea: 0.00007854 m2; BarLength: 1.18178 m; Material: Steel

# IfcReinforcingBarType, no part of this type: type
PredefinedType: MAIN; NominalDiameter: 0.012 m; CrossSectionArea: 0.0001131 m2; BarLength: 3.957 m; Material: Steel

# IfcReinforcingBarType, no part of this type: type
PredefinedType: MAIN; NominalDiameter: 0.012 m; CrossSectionArea: 0.0001131 m2; BarLength: 1.18782 m; Material: Steel

# IfcReinforcingBarType, no part of this type: type
PredefinedType: LIGATURE; NominalDiameter: 0.01 m; CrossSectionArea: 0.00007854 m2; BarLength: 3.74 m; Material: Steel

# IfcReinforcingBarType, no part of this type: type
PredefinedType: LIGATURE; NominalDiameter: 0.01 m; CrossSectionArea: 0.00007854 m2; BarLength: 1.21121 m; Material: Steel

# IfcReinforcingBarType, no part of this type: type
PredefinedType: MAIN; NominalDiameter: 0.016 m; CrossSectionArea: 0.00020106 m2; BarLength: 3.952 m; Material: Steel

# IfcReinforcingBarType, no part of this type: type
PredefinedType: MAIN; NominalDiameter: 0.016 m; CrossSectionArea: 0.00020106 m2; BarLength: 1.17543 m; Material: Steel

# IfcReinforcingBarType, no part of this type: type
PredefinedType: LIGATURE; NominalDiameter: 0.01 m; CrossSectionArea: 0.00007854 m2; BarLength: 1.18178 m; Material: Steel

# IfcReinforcingBarType, no part of this type: type
PredefinedType: MAIN; NominalDiameter: 0.02 m; CrossSectionArea: 0.00031416 m2; BarLength: 1.59754 m; Material: Steel

# IfcReinforcingBarType, no part of this type: type
PredefinedType: MAIN; NominalDiameter: 0.016 m; CrossSectionArea: 0.00020106 m2; BarLength: 1.60193 m; Material: Steel

# IfcReinforcingBarType, no part of this type: type
PredefinedType: MAIN; NominalDiameter: 0.02 m; CrossSectionArea: 0.00031416 m2; BarLength: 4.73591 m; Material: Steel

# IfcReinforcingBarType, no part of this type: type
PredefinedType: MAIN; NominalDiameter: 0.016 m; CrossSectionArea: 0.00020106 m2; BarLength: 4.73591 m; Material: Steel

# IfcReinforcingBarType, no part of this type: type
PredefinedType: MAIN; NominalDiameter: 0.02 m; CrossSectionArea: 0.00031416 m2; BarLength: 4.23591 m; Material: Steel

# IfcReinforcingBarType, no part of this type: type
PredefinedType: MAIN; NominalDiameter: 0.016 m; CrossSectionArea: 0.00020106 m2; BarLength: 4.23591 m; Material: Steel

# IfcReinforcingBarType, no part of this type: type
PredefinedType: MAIN; NominalDiameter: 0.016 m; CrossSectionArea: 0.00020106 m2; BarLength: 3.32943 m; Material: Steel

# IfcReinforcingBarType, no part of this type: type
PredefinedType: LIGATURE; NominalDiameter: 0.008 m; CrossSectionArea: 0.000050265 m2; BarLength: 0.978432 m; Material: Steel

# IfcReinforcingBarType, no part of this type: type
PredefinedType: LIGATURE; NominalDiameter: 0.008 m; CrossSectionArea: 0.000050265 m2; BarLength: 2.37879 m; Material: Steel

# IfcReinforcingBarType, no part of this type: type
PredefinedType: LIGATURE; NominalDiameter: 0.008 m; CrossSectionArea: 0.000050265 m2; BarLength: 0.578429 m; Material: Steel

# IfcReinforcingBarType, no part of this type: type
PredefinedType: LIGATURE; NominalDiameter: 0.008 m; CrossSectionArea: 0.000050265 m2; BarLength: 2.37879 m; Material: Steel

# IfcReinforcingBarType, no part of this type: type
PredefinedType: MAIN; NominalDiameter: 0.018 m; CrossSectionArea: 0.00025447 m2; BarLength: 1.51973 m; Material: Steel

# IfcReinforcingBarType, no part of this type: type
PredefinedType: MAIN; NominalDiameter: 0.018 m; CrossSectionArea: 0.00025447 m2; BarLength: 4.47 m; Material: Steel

# IfcReinforcingBarType, no part of this type: type
PredefinedType: MAIN; NominalDiameter: 0.018 m; CrossSectionArea: 0.00025447 m2; BarLength: 3.97 m; Material: Steel

# IfcReinforcingBarType, no part of this type: type
PredefinedType: MAIN; NominalDiameter: 0.016 m; CrossSectionArea: 0.00020106 m2; BarLength: 3.32943 m; Material: Steel

# IfcReinforcingBarType, no part of this type: type
PredefinedType: LIGATURE; NominalDiameter: 0.008 m; CrossSectionArea: 0.000050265 m2; BarLength: 1.42681 m; Material: Steel

# IfcReinforcingBarType, no part of this type: type
PredefinedType: LIGATURE; NominalDiameter: 0.008 m; CrossSectionArea: 0.000050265 m2; BarLength: 2.37879 m; Material: Steel

# IfcReinforcingBarType, no part of this type: type
PredefinedType: LIGATURE; NominalDiameter: 0.008 m; CrossSectionArea: 0.000050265 m2; BarLength: 0.978429 m; Material: Steel

# IfcReinforcingBarType, no part of this type: type
PredefinedType: MAIN; NominalDiameter: 0.018 m; CrossSectionArea: 0.00025447 m2; BarLength: 1.51973 m; Material: Steel

# IfcReinforcingBarType, no part of this type: type
PredefinedType: MAIN; NominalDiameter: 0.018 m; CrossSectionArea: 0.00025447 m2; BarLength: 4.47 m; Material: Steel

# IfcReinforcingBarType, no part of this type: type
PredefinedType: MAIN; NominalDiameter: 0.018 m; CrossSectionArea: 0.00025447 m2; BarLength: 3.97 m; Material: Steel

# IfcReinforcingBarType, no part of this type: type
PredefinedType: MAIN; NominalDiameter: 0.018 m; CrossSectionArea: 0.00025447 m2; BarLength: 3.32723 m; Material: Steel

# IfcReinforcingBarType, no part of this type: type
PredefinedType: MAIN; NominalDiameter: 0.016 m; CrossSectionArea: 0.00020106 m2; BarLength: 3.32943 m; Material: Steel

# IfcReinforcingBarType, no part of this type: type
PredefinedType: LIGATURE; NominalDiameter: 0.008 m; CrossSectionArea: 0.000050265 m2; BarLength: 1.42683 m; Material: Steel

# IfcReinforcingBarType, no part of this type: type
PredefinedType: LIGATURE; NominalDiameter: 0.008 m; CrossSectionArea: 0.000050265 m2; BarLength: 2.37879 m; Material: Steel

# IfcReinforcingBarType, no part of this type: type
PredefinedType: LIGATURE; NominalDiameter: 0.008 m; CrossSectionArea: 0.000050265 m2; BarLength: 0.978428 m; Material: Steel

# IfcReinforcingBarType, no part of this type: type
PredefinedType: LIGATURE; NominalDiameter: 0.008 m; CrossSectionArea: 0.000050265 m2; BarLength: 1.4215 m; Material: Steel

# IfcReinforcingBarType, no part of this type: type
PredefinedType: MAIN; NominalDiameter: 0.02 m; CrossSectionArea: 0.00031416 m2; BarLength: 1.59754 m; Material: Steel

# IfcReinforcingBarType, no part of this type: type
PredefinedType: MAIN; NominalDiameter: 0.02 m; CrossSectionArea: 0.00031416 m2; BarLength: 4.55 m; Material: Steel

# IfcReinforcingBarType, no part of this type: type
PredefinedType: MAIN; NominalDiameter: 0.02 m; CrossSectionArea: 0.00031416 m2; BarLength: 4.05 m; Material: Steel

# IfcReinforcingBarType, no part of this type: type
PredefinedType: MAIN; NominalDiameter: 0.016 m; CrossSectionArea: 0.00020106 m2; BarLength: 3.32943 m; Material: Steel

# IfcReinforcingBarType, no part of this type: type
PredefinedType: LIGATURE; NominalDiameter: 0.008 m; CrossSectionArea: 0.000050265 m2; BarLength: 2.37879 m; Material: Steel

# IfcReinforcingBarType, no part of this type: type
PredefinedType: LIGATURE; NominalDiameter: 0.008 m; CrossSectionArea: 0.000050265 m2; BarLength: 1.23963 m; Material: Steel

# IfcReinforcingBarType, no part of this type: type
PredefinedType: LIGATURE; NominalDiameter: 0.008 m; CrossSectionArea: 0.000050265 m2; BarLength: 0.97843 m; Material: Steel

# IfcReinforcingBarType, no part of this type: type
PredefinedType: LIGATURE; NominalDiameter: 0.008 m; CrossSectionArea: 0.000050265 m2; BarLength: 1.23324 m; Material: Steel

# IfcReinforcingBarType, no part of this type: type
PredefinedType: MAIN; NominalDiameter: 0.02 m; CrossSectionArea: 0.00031416 m2; BarLength: 1.59754 m; Material: Steel

# IfcReinforcingBarType, no part of this type: type
PredefinedType: MAIN; NominalDiameter: 0.016 m; CrossSectionArea: 0.00020106 m2; BarLength: 1.60193 m; Material: Steel

# IfcReinforcingBarType, no part of this type: type
PredefinedType: MAIN; NominalDiameter: 0.02 m; CrossSectionArea: 0.00031416 m2; BarLength: 4.73591 m; Material: Steel

# IfcReinforcingBarType, no part of this type: type
PredefinedType: MAIN; NominalDiameter: 0.016 m; CrossSectionArea: 0.00020106 m2; BarLength: 4.73591 m; Material: Steel

# IfcReinforcingBarType, no part of this type: type
PredefinedType: MAIN; NominalDiameter: 0.02 m; CrossSectionArea: 0.00031416 m2; BarLength: 4.23591 m; Material: Steel

# IfcReinforcingBarType, no part of this type: type
PredefinedType: MAIN; NominalDiameter: 0.016 m; CrossSectionArea: 0.00020106 m2; BarLength: 4.23591 m; Material: Steel

# IfcReinforcingBarType, no part of this type: type
PredefinedType: MAIN; NominalDiameter: 0.016 m; CrossSectionArea: 0.00020106 m2; BarLength: 3.32943 m; Material: Steel

# IfcReinforcingBarType, no part of this type: type
PredefinedType: LIGATURE; NominalDiameter: 0.008 m; CrossSectionArea: 0.000050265 m2; BarLength: 0.978434 m; Material: Steel

# IfcReinforcingBarType, no part of this type: type
PredefinedType: LIGATURE; NominalDiameter: 0.008 m; CrossSectionArea: 0.000050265 m2; BarLength: 0.578426 m; Material: Steel

# IfcReinforcingBarType, no part of this type: type
PredefinedType: LIGATURE; NominalDiameter: 0.008 m; CrossSectionArea: 0.000050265 m2; BarLength: 2.37879 m; Material: Steel

# IfcReinforcingBarType, no part of this type: type
PredefinedType: LIGATURE; NominalDiameter: 0.008 m; CrossSectionArea: 0.000050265 m2; BarLength: 2.37879 m; Material: Steel

# IfcReinforcingBarType, no part of this type: type
PredefinedType: MAIN; NominalDiameter: 0.02 m; CrossSectionArea: 0.00031416 m2; BarLength: 1.59754 m; Material: Steel

# IfcReinforcingBarType, no part of this type: type
PredefinedType: MAIN; NominalDiameter: 0.02 m; CrossSectionArea: 0.00031416 m2; BarLength: 4.55 m; Material: Steel

# IfcReinforcingBarType, no part of this type: type
PredefinedType: MAIN; NominalDiameter: 0.02 m; CrossSectionArea: 0.00031416 m2; BarLength: 4.23591 m; Material: Steel

# IfcReinforcingBarType, no part of this type: type
PredefinedType: MAIN; NominalDiameter: 0.018 m; CrossSectionArea: 0.00025447 m2; BarLength: 4.36723 m; Material: Steel

# IfcReinforcingBarType, no part of this type: type
PredefinedType: LIGATURE; NominalDiameter: 0.008 m; CrossSectionArea: 0.000050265 m2; BarLength: 2.37879 m; Material: Steel

# IfcReinforcingBarType, no part of this type: type
PredefinedType: LIGATURE; NominalDiameter: 0.008 m; CrossSectionArea: 0.000050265 m2; BarLength: 1.36284 m; Material: Steel

# IfcReinforcingBarType, no part of this type: type
PredefinedType: LIGATURE; NominalDiameter: 0.008 m; CrossSectionArea: 0.000050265 m2; BarLength: 1.42683 m; Material: Steel

# IfcReinforcingBarType, no part of this type: type
PredefinedType: LIGATURE; NominalDiameter: 0.008 m; CrossSectionArea: 0.000050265 m2; BarLength: 0.978429 m; Material: Steel

# IfcReinforcingBarType, no part of this type: type
PredefinedType: MAIN; NominalDiameter: 0.02 m; CrossSectionArea: 0.00031416 m2; BarLength: 1.59754 m; Material: Steel

# IfcReinforcingBarType, no part of this type: type
PredefinedType: MAIN; NominalDiameter: 0.02 m; CrossSectionArea: 0.00031416 m2; BarLength: 4.55 m; Material: Steel

# IfcReinforcingBarType, no part of this type: type
PredefinedType: MAIN; NominalDiameter: 0.02 m; CrossSectionArea: 0.00031416 m2; BarLength: 4.23591 m; Material: Steel

# IfcReinforcingBarType, no part of this type: type
PredefinedType: MAIN; NominalDiameter: 0.016 m; CrossSectionArea: 0.00020106 m2; BarLength: 4.36943 m; Material: Steel

# IfcReinforcingBarType, no part of this type: type
PredefinedType: LIGATURE; NominalDiameter: 0.008 m; CrossSectionArea: 0.000050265 m2; BarLength: 2.37879 m; Material: Steel

# IfcReinforcingBarType, no part of this type: type
PredefinedType: LIGATURE; NominalDiameter: 0.008 m; CrossSectionArea: 0.000050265 m2; BarLength: 0.978428 m; Material: Steel

# IfcReinforcingBarType, no part of this type: type
PredefinedType: LIGATURE; NominalDiameter: 0.008 m; CrossSectionArea: 0.000050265 m2; BarLength: 1.4295 m; Material: Steel

# IfcReinforcingBarType, no part of this type: type
PredefinedType: LIGATURE; NominalDiameter: 0.008 m; CrossSectionArea: 0.000050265 m2; BarLength: 1.42417 m; Material: Steel

# IfcReinforcingBarType, no part of this type: type
PredefinedType: MAIN; NominalDiameter: 0.016 m; CrossSectionArea: 0.00020106 m2; BarLength: 1.44193 m; Material: Steel

# IfcReinforcingBarType, no part of this type: type
PredefinedType: MAIN; NominalDiameter: 0.016 m; CrossSectionArea: 0.00020106 m2; BarLength: 4.39 m; Material: Steel

# IfcReinforcingBarType, no part of this type: type
PredefinedType: MAIN; NominalDiameter: 0.016 m; CrossSectionArea: 0.00020106 m2; BarLength: 3.89 m; Material: Steel

# IfcReinforcingBarType, no part of this type: type
PredefinedType: MAIN; NominalDiameter: 0.016 m; CrossSectionArea: 0.00020106 m2; BarLength: 4.36943 m; Material: Steel

# IfcReinforcingBarType, no part of this type: type
PredefinedType: LIGATURE; NominalDiameter: 0.008 m; CrossSectionArea: 0.000050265 m2; BarLength: 2.37879 m; Material: Steel

# IfcReinforcingBarType, no part of this type: type
PredefinedType: LIGATURE; NominalDiameter: 0.008 m; CrossSectionArea: 0.000050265 m2; BarLength: 1.23324 m; Material: Steel

# IfcReinforcingBarType, no part of this type: type
PredefinedType: LIGATURE; NominalDiameter: 0.008 m; CrossSectionArea: 0.000050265 m2; BarLength: 0.978429 m; Material: Steel

# IfcReinforcingBarType, no part of this type: type
PredefinedType: LIGATURE; NominalDiameter: 0.01 m; CrossSectionArea: 0.00007854 m2; BarLength: 2.3898 m; Material: Steel

# IfcReinforcingBarType, no part of this type: type
PredefinedType: LIGATURE; NominalDiameter: 0.01 m; CrossSectionArea: 0.00007854 m2; BarLength: 1.23626 m; Material: Steel

# IfcReinforcingBarType, no part of this type: type
PredefinedType: LIGATURE; NominalDiameter: 0.01 m; CrossSectionArea: 0.00007854 m2; BarLength: 0.98443 m; Material: Steel

# IfcReinforcingBarType, no part of this type: type
PredefinedType: LIGATURE; NominalDiameter: 0.008 m; CrossSectionArea: 0.000050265 m2; BarLength: 1.42416 m; Material: Steel

# IfcReinforcingBarType, no part of this type: type
PredefinedType: MAIN; NominalDiameter: 0.018 m; CrossSectionArea: 0.00025447 m2; BarLength: 1.51973 m; Material: Steel

# IfcReinforcingBarType, no part of this type: type
PredefinedType: MAIN; NominalDiameter: 0.016 m; CrossSectionArea: 0.00020106 m2; BarLength: 1.52193 m; Material: Steel

# IfcReinforcingBarType, no part of this type: type
PredefinedType: MAIN; NominalDiameter: 0.018 m; CrossSectionArea: 0.00025447 m2; BarLength: 4.47 m; Material: Steel

# IfcReinforcingBarType, no part of this type: type
PredefinedType: MAIN; NominalDiameter: 0.016 m; CrossSectionArea: 0.00020106 m2; BarLength: 4.47 m; Material: Steel

# IfcReinforcingBarType, no part of this type: type
PredefinedType: MAIN; NominalDiameter: 0.018 m; CrossSectionArea: 0.00025447 m2; BarLength: 4.13732 m; Material: Steel

# IfcReinforcingBarType, no part of this type: type
PredefinedType: MAIN; NominalDiameter: 0.016 m; CrossSectionArea: 0.00020106 m2; BarLength: 4.13732 m; Material: Steel

# IfcReinforcingBarType, no part of this type: type
PredefinedType: MAIN; NominalDiameter: 0.016 m; CrossSectionArea: 0.00020106 m2; BarLength: 4.36943 m; Material: Steel

# IfcReinforcingBarType, no part of this type: type
PredefinedType: LIGATURE; NominalDiameter: 0.008 m; CrossSectionArea: 0.000050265 m2; BarLength: 2.37879 m; Material: Steel

# IfcReinforcingBarType, no part of this type: type
PredefinedType: LIGATURE; NominalDiameter: 0.008 m; CrossSectionArea: 0.000050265 m2; BarLength: 1.4215 m; Material: Steel

# IfcReinforcingBarType, no part of this type: type
PredefinedType: LIGATURE; NominalDiameter: 0.008 m; CrossSectionArea: 0.000050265 m2; BarLength: 0.978429 m; Material: Steel

# IfcReinforcingBarType, no part of this type: type
PredefinedType: LIGATURE; NominalDiameter: 0.01 m; CrossSectionArea: 0.00007854 m2; BarLength: 2.3898 m; Material: Steel

# IfcReinforcingBarType, no part of this type: type
PredefinedType: LIGATURE; NominalDiameter: 0.01 m; CrossSectionArea: 0.00007854 m2; BarLength: 1.42451 m; Material: Steel

# IfcReinforcingBarType, no part of this type: type
PredefinedType: LIGATURE; NominalDiameter: 0.01 m; CrossSectionArea: 0.00007854 m2; BarLength: 0.98443 m; Material: Steel

# IfcReinforcingBarType, no part of this type: type
PredefinedType: MAIN; NominalDiameter: 0.02 m; CrossSectionArea: 0.00031416 m2; BarLength: 1.59754 m; Material: Steel

# IfcReinforcingBarType, no part of this type: type
PredefinedType: MAIN; NominalDiameter: 0.02 m; CrossSectionArea: 0.00031416 m2; BarLength: 4.55 m; Material: Steel

# IfcReinforcingBarType, no part of this type: type
PredefinedType: MAIN; NominalDiameter: 0.02 m; CrossSectionArea: 0.00031416 m2; BarLength: 4.05 m; Material: Steel

# IfcReinforcingBarType, no part of this type: type
PredefinedType: MAIN; NominalDiameter: 0.018 m; CrossSectionArea: 0.00025447 m2; BarLength: 4.36723 m; Material: Steel

# IfcReinforcingBarType, no part of this type: type
PredefinedType: LIGATURE; NominalDiameter: 0.008 m; CrossSectionArea: 0.000050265 m2; BarLength: 2.37879 m; Material: Steel

# IfcReinforcingBarType, no part of this type: type
PredefinedType: LIGATURE; NominalDiameter: 0.008 m; CrossSectionArea: 0.000050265 m2; BarLength: 1.36283 m; Material: Steel

# IfcReinforcingBarType, no part of this type: type
PredefinedType: LIGATURE; NominalDiameter: 0.008 m; CrossSectionArea: 0.000050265 m2; BarLength: 0.978429 m; Material: Steel

# IfcReinforcingBarType, no part of this type: type
PredefinedType: LIGATURE; NominalDiameter: 0.008 m; CrossSectionArea: 0.000050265 m2; BarLength: 1.42683 m; Material: Steel

# IfcReinforcingBarType, no part of this type: type
PredefinedType: MAIN; NominalDiameter: 0.02 m; CrossSectionArea: 0.00031416 m2; BarLength: 1.59754 m; Material: Steel

# IfcReinforcingBarType, no part of this type: type
PredefinedType: MAIN; NominalDiameter: 0.016 m; CrossSectionArea: 0.00020106 m2; BarLength: 1.60193 m; Material: Steel

# IfcReinforcingBarType, no part of this type: type
PredefinedType: MAIN; NominalDiameter: 0.02 m; CrossSectionArea: 0.00031416 m2; BarLength: 4.73591 m; Material: Steel

# IfcReinforcingBarType, no part of this type: type
PredefinedType: MAIN; NominalDiameter: 0.016 m; CrossSectionArea: 0.00020106 m2; BarLength: 4.73591 m; Material: Steel

# IfcReinforcingBarType, no part of this type: type
PredefinedType: MAIN; NominalDiameter: 0.02 m; CrossSectionArea: 0.00031416 m2; BarLength: 4.23591 m; Material: Steel

# IfcReinforcingBarType, no part of this type: type
PredefinedType: MAIN; NominalDiameter: 0.016 m; CrossSectionArea: 0.00020106 m2; BarLength: 4.23591 m; Material: Steel

# IfcReinforcingBarType, no part of this type: type
PredefinedType: MAIN; NominalDiameter: 0.016 m; CrossSectionArea: 0.00020106 m2; BarLength: 3.32943 m; Material: Steel

# IfcReinforcingBarType, no part of this type: type
PredefinedType: LIGATURE; NominalDiameter: 0.008 m; CrossSectionArea: 0.000050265 m2; BarLength: 0.978432 m; Material: Steel

# IfcReinforcingBarType, no part of this type: type
PredefinedType: LIGATURE; NominalDiameter: 0.008 m; CrossSectionArea: 0.000050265 m2; BarLength: 0.578428 m; Material: Steel

# IfcReinforcingBarType, no part of this type: type
PredefinedType: LIGATURE; NominalDiameter: 0.008 m; CrossSectionArea: 0.000050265 m2; BarLength: 2.37879 m; Material: Steel

# IfcReinforcingBarType, no part of this type: type
PredefinedType: LIGATURE; NominalDiameter: 0.008 m; CrossSectionArea: 0.000050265 m2; BarLength: 2.37879 m; Material: Steel

# IfcReinforcingBarType, no part of this type: type
PredefinedType: MAIN; NominalDiameter: 0.02 m; CrossSectionArea: 0.00031416 m2; BarLength: 1.59754 m; Material: Steel

# IfcReinforcingBarType, no part of this type: type
PredefinedType: MAIN; NominalDiameter: 0.02 m; CrossSectionArea: 0.00031416 m2; BarLength: 4.55 m; Material: Steel

# IfcReinforcingBarType, no part of this type: type
PredefinedType: MAIN; NominalDiameter: 0.02 m; CrossSectionArea: 0.00031416 m2; BarLength: 4.05 m; Material: Steel

# IfcReinforcingBarType, no part of this type: type
PredefinedType: MAIN; NominalDiameter: 0.016 m; CrossSectionArea: 0.00020106 m2; BarLength: 3.32943 m; Material: Steel

# IfcReinforcingBarType, no part of this type: type
PredefinedType: LIGATURE; NominalDiameter: 0.008 m; CrossSectionArea: 0.000050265 m2; BarLength: 2.37879 m; Material: Steel

# IfcReinforcingBarType, no part of this type: type
PredefinedType: LIGATURE; NominalDiameter: 0.008 m; CrossSectionArea: 0.000050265 m2; BarLength: 1.4295 m; Material: Steel

# IfcReinforcingBarType, no part of this type: type
PredefinedType: LIGATURE; NominalDiameter: 0.008 m; CrossSectionArea: 0.000050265 m2; BarLength: 0.97843 m; Material: Steel

# IfcReinforcingBarType, no part of this type: type
PredefinedType: LIGATURE; NominalDiameter: 0.008 m; CrossSectionArea: 0.000050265 m2; BarLength: 1.42416 m; Material: Steel

# IfcReinforcingBarType, no part of this type: type
PredefinedType: MAIN; NominalDiameter: 0.018 m; CrossSectionArea: 0.00025447 m2; BarLength: 1.51973 m; Material: Steel

# IfcReinforcingBarType, no part of this type: type
PredefinedType: MAIN; NominalDiameter: 0.016 m; CrossSectionArea: 0.00020106 m2; BarLength: 1.52193 m; Material: Steel

# IfcReinforcingBarType, no part of this type: type
PredefinedType: MAIN; NominalDiameter: 0.018 m; CrossSectionArea: 0.00025447 m2; BarLength: 4.47 m; Material: Steel

# IfcReinforcingBarType, no part of this type: type
PredefinedType: MAIN; NominalDiameter: 0.016 m; CrossSectionArea: 0.00020106 m2; BarLength: 4.47 m; Material: Steel

# IfcReinforcingBarType, no part of this type: type
PredefinedType: MAIN; NominalDiameter: 0.018 m; CrossSectionArea: 0.00025447 m2; BarLength: 3.97 m; Material: Steel

# IfcReinforcingBarType, no part of this type: type
PredefinedType: MAIN; NominalDiameter: 0.016 m; CrossSectionArea: 0.00020106 m2; BarLength: 3.97 m; Material: Steel

# IfcReinforcingBarType, no part of this type: type
PredefinedType: MAIN; NominalDiameter: 0.02 m; CrossSectionArea: 0.00031416 m2; BarLength: 3.32504 m; Material: Steel

# IfcReinforcingBarType, no part of this type: type
PredefinedType: MAIN; NominalDiameter: 0.016 m; CrossSectionArea: 0.00020106 m2; BarLength: 3.32943 m; Material: Steel

# IfcReinforcingBarType, no part of this type: type
PredefinedType: LIGATURE; NominalDiameter: 0.008 m; CrossSectionArea: 0.000050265 m2; BarLength: 2.37879 m; Material: Steel

# IfcReinforcingBarType, no part of this type: type
PredefinedType: LIGATURE; NominalDiameter: 0.008 m; CrossSectionArea: 0.000050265 m2; BarLength: 0.978429 m; Material: Steel

# IfcReinforcingBarType, no part of this type: type
PredefinedType: LIGATURE; NominalDiameter: 0.008 m; CrossSectionArea: 0.000050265 m2; BarLength: 1.4215 m; Material: Steel

# IfcReinforcingBarType, no part of this type: type
PredefinedType: MAIN; NominalDiameter: 0.02 m; CrossSectionArea: 0.00031416 m2; BarLength: 1.59754 m; Material: Steel

# IfcReinforcingBarType, no part of this type: type
PredefinedType: MAIN; NominalDiameter: 0.02 m; CrossSectionArea: 0.00031416 m2; BarLength: 4.73591 m; Material: Steel

# IfcReinforcingBarType, no part of this type: type
PredefinedType: MAIN; NominalDiameter: 0.02 m; CrossSectionArea: 0.00031416 m2; BarLength: 4.05 m; Material: Steel

# IfcReinforcingBarType, no part of this type: type
PredefinedType: MAIN; NominalDiameter: 0.016 m; CrossSectionArea: 0.00020106 m2; BarLength: 3.32943 m; Material: Steel

# IfcReinforcingBarType, no part of this type: type
PredefinedType: LIGATURE; NominalDiameter: 0.008 m; CrossSectionArea: 0.000050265 m2; BarLength: 2.37879 m; Material: Steel

# IfcReinforcingBarType, no part of this type: type
PredefinedType: LIGATURE; NominalDiameter: 0.008 m; CrossSectionArea: 0.000050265 m2; BarLength: 1.23964 m; Material: Steel

# IfcReinforcingBarType, no part of this type: type
PredefinedType: LIGATURE; NominalDiameter: 0.008 m; CrossSectionArea: 0.000050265 m2; BarLength: 0.978429 m; Material: Steel

# IfcReinforcingBarType, no part of this type: type
PredefinedType: LIGATURE; NominalDiameter: 0.008 m; CrossSectionArea: 0.000050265 m2; BarLength: 1.23324 m; Material: Steel

# IfcReinforcingBarType, no part of this type: type
PredefinedType: MAIN; NominalDiameter: 0.02 m; CrossSectionArea: 0.00031416 m2; BarLength: 1.59754 m; Material: Steel

# IfcReinforcingBarType, no part of this type: type
PredefinedType: MAIN; NominalDiameter: 0.016 m; CrossSectionArea: 0.00020106 m2; BarLength: 1.60193 m; Material: Steel

# IfcReinforcingBarType, no part of this type: type
PredefinedType: MAIN; NominalDiameter: 0.02 m; CrossSectionArea: 0.00031416 m2; BarLength: 4.73591 m; Material: Steel

# IfcReinforcingBarType, no part of this type: type
PredefinedType: MAIN; NominalDiameter: 0.016 m; CrossSectionArea: 0.00020106 m2; BarLength: 4.73591 m; Material: Steel

# IfcReinforcingBarType, no part of this type: type
PredefinedType: MAIN; NominalDiameter: 0.02 m; CrossSectionArea: 0.00031416 m2; BarLength: 4.23591 m; Material: Steel

# IfcReinforcingBarType, no part of this type: type
PredefinedType: MAIN; NominalDiameter: 0.016 m; CrossSectionArea: 0.00020106 m2; BarLength: 4.23591 m; Material: Steel

# IfcReinforcingBarType, no part of this type: type
PredefinedType: MAIN; NominalDiameter: 0.016 m; CrossSectionArea: 0.00020106 m2; BarLength: 3.32943 m; Material: Steel

# IfcReinforcingBarType, no part of this type: type
PredefinedType: LIGATURE; NominalDiameter: 0.008 m; CrossSectionArea: 0.000050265 m2; BarLength: 2.37879 m; Material: Steel

# IfcReinforcingBarType, no part of this type: type
PredefinedType: LIGATURE; NominalDiameter: 0.008 m; CrossSectionArea: 0.000050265 m2; BarLength: 2.37879 m; Material: Steel

# IfcReinforcingBarType, no part of this type: type
PredefinedType: LIGATURE; NominalDiameter: 0.008 m; CrossSectionArea: 0.000050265 m2; BarLength: 0.978433 m; Material: Steel

# IfcReinforcingBarType, no part of this type: type
PredefinedType: LIGATURE; NominalDiameter: 0.008 m; CrossSectionArea: 0.000050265 m2; BarLength: 0.57843 m; Material: Steel

# IfcReinforcingBarType, no part of this type: type
PredefinedType: LIGATURE; NominalDiameter: 0.01 m; CrossSectionArea: 0.00007854 m2; BarLength: 0.984432 m; Material: Steel

# IfcReinforcingBarType, no part of this type: type
PredefinedType: LIGATURE; NominalDiameter: 0.01 m; CrossSectionArea: 0.00007854 m2; BarLength: 0.584429 m; Material: Steel

# IfcReinforcingBarType, no part of this type: type
PredefinedType: LIGATURE; NominalDiameter: 0.01 m; CrossSectionArea: 0.00007854 m2; BarLength: 2.3898 m; Material: Steel

# IfcReinforcingBarType, no part of this type: type
PredefinedType: LIGATURE; NominalDiameter: 0.01 m; CrossSectionArea: 0.00007854 m2; BarLength: 2.3898 m; Material: Steel

# IfcReinforcingBarType, no part of this type: type
PredefinedType: MAIN; NominalDiameter: 0.014 m; CrossSectionArea: 0.00015394 m2; BarLength: 22.8032 m; Material: Steel

# IfcReinforcingBarType, no part of this type: type
PredefinedType: MAIN; NominalDiameter: 0.014 m; CrossSectionArea: 0.00015394 m2; BarLength: 15.9132 m; Material: Steel

# IfcReinforcingBarType, no part of this type: type
PredefinedType: MAIN; NominalDiameter: 0.014 m; CrossSectionArea: 0.00015394 m2; BarLength: 1.51321 m; Material: Steel

# IfcReinforcingBarType, no part of this type: type
PredefinedType: MAIN; NominalDiameter: 0.014 m; CrossSectionArea: 0.00015394 m2; BarLength: 13.9632 m; Material: Steel

# IfcReinforcingBarType, no part of this type: type
PredefinedType: MAIN; NominalDiameter: 0.014 m; CrossSectionArea: 0.00015394 m2; BarLength: 1.53321 m; Material: Steel

# IfcReinforcingBarType, no part of this type: type
PredefinedType: MAIN; NominalDiameter: 0.014 m; CrossSectionArea: 0.00015394 m2; BarLength: 3.11321 m; Material: Steel

# IfcReinforcingBarType, no part of this type: type
PredefinedType: LIGATURE; NominalDiameter: 0.008 m; CrossSectionArea: 0.000050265 m2; BarLength: 1.5868 m; Material: Steel

# IfcReinforcingBarType, no part of this type: type
PredefinedType: MAIN; NominalDiameter: 0.016 m; CrossSectionArea: 0.00020106 m2; BarLength: 8.29448 m; Material: Steel

# IfcReinforcingBarType, no part of this type: type
PredefinedType: MAIN; NominalDiameter: 0.016 m; CrossSectionArea: 0.00020106 m2; BarLength: 8.19121 m; Material: Steel

# IfcReinforcingBarType, no part of this type: type
PredefinedType: MAIN; NominalDiameter: 0.018 m; CrossSectionArea: 0.00025447 m2; BarLength: 6.59121 m; Material: Steel

# IfcReinforcingBarType, no part of this type: type
PredefinedType: MAIN; NominalDiameter: 0.02 m; CrossSectionArea: 0.00031416 m2; BarLength: 5.19121 m; Material: Steel

# IfcReinforcingBarType, no part of this type: type
PredefinedType: MAIN; NominalDiameter: 0.016 m; CrossSectionArea: 0.00020106 m2; BarLength: 3.58285 m; Material: Steel

# IfcReinforcingBarType, no part of this type: type
PredefinedType: MAIN; NominalDiameter: 0.02 m; CrossSectionArea: 0.00031416 m2; BarLength: 11.8812 m; Material: Steel

# IfcReinforcingBarType, no part of this type: type
PredefinedType: MAIN; NominalDiameter: 0.018 m; CrossSectionArea: 0.00025447 m2; BarLength: 11.9512 m; Material: Steel

# IfcReinforcingBarType, no part of this type: type
PredefinedType: MAIN; NominalDiameter: 0.016 m; CrossSectionArea: 0.00020106 m2; BarLength: 3.36285 m; Material: Steel

# IfcReinforcingBarType, no part of this type: type
PredefinedType: MAIN; NominalDiameter: 0.012 m; CrossSectionArea: 0.0001131 m2; BarLength: 2.52121 m; Material: Steel

# IfcReinforcingBarType, no part of this type: type
PredefinedType: MAIN; NominalDiameter: 0.012 m; CrossSectionArea: 0.0001131 m2; BarLength: 4.72121 m; Material: Steel

# IfcReinforcingBarType, no part of this type: type
PredefinedType: MAIN; NominalDiameter: 0.012 m; CrossSectionArea: 0.0001131 m2; BarLength: 6.77121 m; Material: Steel

# IfcReinforcingBarType, no part of this type: type
PredefinedType: MAIN; NominalDiameter: 0.012 m; CrossSectionArea: 0.0001131 m2; BarLength: 6.57121 m; Material: Steel

# IfcReinforcingBarType, no part of this type: type
PredefinedType: MAIN; NominalDiameter: 0.012 m; CrossSectionArea: 0.0001131 m2; BarLength: 4.37121 m; Material: Steel

# IfcReinforcingBarType, no part of this type: type
PredefinedType: MAIN; NominalDiameter: 0.014 m; CrossSectionArea: 0.00015394 m2; BarLength: 2.69121 m; Material: Steel

# IfcReinforcingBarType, no part of this type: type
PredefinedType: MAIN; NominalDiameter: 0.016 m; CrossSectionArea: 0.00020106 m2; BarLength: 2.79448 m; Material: Steel

# IfcReinforcingBarType, no part of this type: type
PredefinedType: LIGATURE; NominalDiameter: 0.008 m; CrossSectionArea: 0.000050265 m2; BarLength: 1.5868 m; Material: Steel

# IfcReinforcingBarType, no part of this type: type
PredefinedType: MAIN; NominalDiameter: 0.018 m; CrossSectionArea: 0.00025447 m2; BarLength: 8.19121 m; Material: Steel

# IfcReinforcingBarType, no part of this type: type
PredefinedType: MAIN; NominalDiameter: 0.016 m; CrossSectionArea: 0.00020106 m2; BarLength: 8.29448 m; Material: Steel

# IfcReinforcingBarType, no part of this type: type
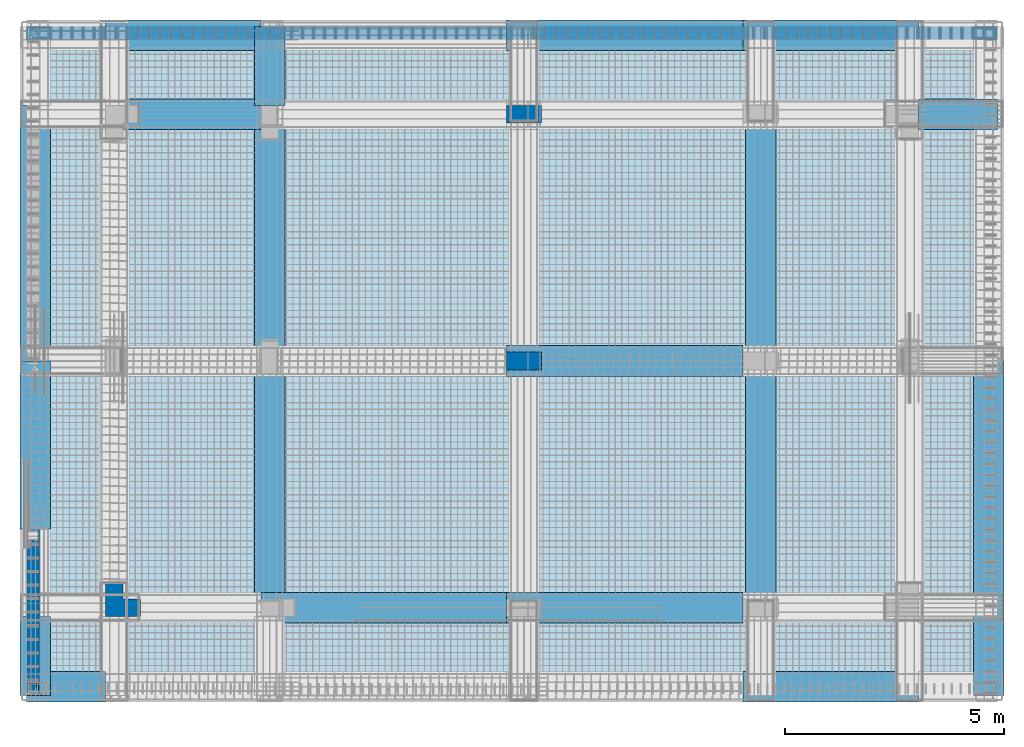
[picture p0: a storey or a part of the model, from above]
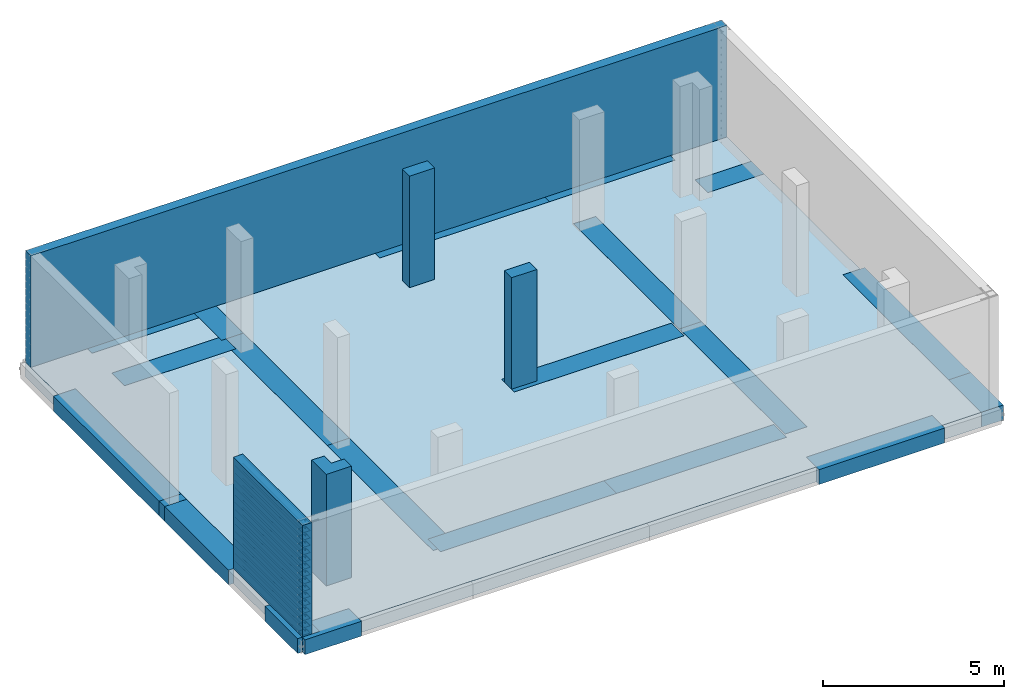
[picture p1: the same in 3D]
Properties of the parts of a building model (IFC4), part 2 of 3

# IfcReinforcingBarType, no part of this type: type
PredefinedType: MAIN; NominalDiameter: 0.018 m; CrossSectionArea: 0.00025447 m2; BarLength: 6.59121 m; Material: Steel

# IfcReinforcingBarType, no part of this type: type
PredefinedType: MAIN; NominalDiameter: 0.02 m; CrossSectionArea: 0.00031416 m2; BarLength: 5.69121 m; Material: Steel

# IfcReinforcingBarType, no part of this type: type
PredefinedType: MAIN; NominalDiameter: 0.016 m; CrossSectionArea: 0.00020106 m2; BarLength: 3.18285 m; Material: Steel

# IfcReinforcingBarType, no part of this type: type
PredefinedType: MAIN; NominalDiameter: 0.018 m; CrossSectionArea: 0.00025447 m2; BarLength: 11.9812 m; Material: Steel

# IfcReinforcingBarType, no part of this type: type
PredefinedType: MAIN; NominalDiameter: 0.016 m; CrossSectionArea: 0.00020106 m2; BarLength: 8.32121 m; Material: Steel

# IfcReinforcingBarType, no part of this type: type
PredefinedType: MAIN; NominalDiameter: 0.02 m; CrossSectionArea: 0.00031416 m2; BarLength: 7.19121 m; Material: Steel

# IfcReinforcingBarType, no part of this type: type
PredefinedType: MAIN; NominalDiameter: 0.016 m; CrossSectionArea: 0.00020106 m2; BarLength: 2.96285 m; Material: Steel

# IfcReinforcingBarType, no part of this type: type
PredefinedType: MAIN; NominalDiameter: 0.012 m; CrossSectionArea: 0.0001131 m2; BarLength: 2.12121 m; Material: Steel

# IfcReinforcingBarType, no part of this type: type
PredefinedType: MAIN; NominalDiameter: 0.012 m; CrossSectionArea: 0.0001131 m2; BarLength: 4.32121 m; Material: Steel

# IfcReinforcingBarType, no part of this type: type
PredefinedType: MAIN; NominalDiameter: 0.012 m; CrossSectionArea: 0.0001131 m2; BarLength: 6.77121 m; Material: Steel

# IfcReinforcingBarType, no part of this type: type
PredefinedType: MAIN; NominalDiameter: 0.012 m; CrossSectionArea: 0.0001131 m2; BarLength: 6.57122 m; Material: Steel

# IfcReinforcingBarType, no part of this type: type
PredefinedType: MAIN; NominalDiameter: 0.012 m; CrossSectionArea: 0.0001131 m2; BarLength: 4.37121 m; Material: Steel

# IfcReinforcingBarType, no part of this type: type
PredefinedType: MAIN; NominalDiameter: 0.018 m; CrossSectionArea: 0.00025447 m2; BarLength: 3.19121 m; Material: Steel

# IfcReinforcingBarType, no part of this type: type
PredefinedType: MAIN; NominalDiameter: 0.016 m; CrossSectionArea: 0.00020106 m2; BarLength: 2.29448 m; Material: Steel

# IfcReinforcingBarType, no part of this type: type
PredefinedType: MAIN; NominalDiameter: 0.014 m; CrossSectionArea: 0.00015394 m2; BarLength: 2.69121 m; Material: Steel

# IfcReinforcingBarType, no part of this type: type
PredefinedType: LIGATURE; NominalDiameter: 0.008 m; CrossSectionArea: 0.000050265 m2; BarLength: 1.06683 m; Material: Steel

# IfcReinforcingBarType, no part of this type: type
PredefinedType: MAIN; NominalDiameter: 0.016 m; CrossSectionArea: 0.00020106 m2; BarLength: 4.09721 m; Material: Steel

# IfcReinforcingBarType, no part of this type: type
PredefinedType: LIGATURE; NominalDiameter: 0.008 m; CrossSectionArea: 0.000050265 m2; BarLength: 1.5868 m; Material: Steel

# IfcReinforcingBarType, no part of this type: type
PredefinedType: MAIN; NominalDiameter: 0.018 m; CrossSectionArea: 0.00025447 m2; BarLength: 11.5912 m; Material: Steel

# IfcReinforcingBarType, no part of this type: type
PredefinedType: MAIN; NominalDiameter: 0.018 m; CrossSectionArea: 0.00025447 m2; BarLength: 8.42831 m; Material: Steel

# IfcReinforcingBarType, no part of this type: type
PredefinedType: MAIN; NominalDiameter: 0.018 m; CrossSectionArea: 0.00025447 m2; BarLength: 6.8643 m; Material: Steel

# IfcReinforcingBarType, no part of this type: type
PredefinedType: MAIN; NominalDiameter: 0.018 m; CrossSectionArea: 0.00025447 m2; BarLength: 11.9512 m; Material: Steel

# IfcReinforcingBarType, no part of this type: type
PredefinedType: MAIN; NominalDiameter: 0.016 m; CrossSectionArea: 0.00020106 m2; BarLength: 9.19121 m; Material: Steel

# IfcReinforcingBarType, no part of this type: type
PredefinedType: MAIN; NominalDiameter: 0.02 m; CrossSectionArea: 0.00031416 m2; BarLength: 7.19122 m; Material: Steel

# IfcReinforcingBarType, no part of this type: type
PredefinedType: MAIN; NominalDiameter: 0.016 m; CrossSectionArea: 0.00020106 m2; BarLength: 3.36285 m; Material: Steel

# IfcReinforcingBarType, no part of this type: type
PredefinedType: MAIN; NominalDiameter: 0.012 m; CrossSectionArea: 0.0001131 m2; BarLength: 2.52121 m; Material: Steel

# IfcReinforcingBarType, no part of this type: type
PredefinedType: MAIN; NominalDiameter: 0.012 m; CrossSectionArea: 0.0001131 m2; BarLength: 4.32121 m; Material: Steel

# IfcReinforcingBarType, no part of this type: type
PredefinedType: MAIN; NominalDiameter: 0.012 m; CrossSectionArea: 0.0001131 m2; BarLength: 6.77121 m; Material: Steel

# IfcReinforcingBarType, no part of this type: type
PredefinedType: MAIN; NominalDiameter: 0.012 m; CrossSectionArea: 0.0001131 m2; BarLength: 6.57121 m; Material: Steel

# IfcReinforcingBarType, no part of this type: type
PredefinedType: MAIN; NominalDiameter: 0.012 m; CrossSectionArea: 0.0001131 m2; BarLength: 4.37121 m; Material: Steel

# IfcReinforcingBarType, no part of this type: type
PredefinedType: MAIN; NominalDiameter: 0.018 m; CrossSectionArea: 0.00025447 m2; BarLength: 4.19122 m; Material: Steel

# IfcReinforcingBarType, no part of this type: type
PredefinedType: MAIN; NominalDiameter: 0.014 m; CrossSectionArea: 0.00015394 m2; BarLength: 3.19121 m; Material: Steel

# IfcReinforcingBarType, no part of this type: type
PredefinedType: MAIN; NominalDiameter: 0.014 m; CrossSectionArea: 0.00015394 m2; BarLength: 2.69121 m; Material: Steel

# IfcReinforcingBarType, no part of this type: type
PredefinedType: LIGATURE; NominalDiameter: 0.008 m; CrossSectionArea: 0.000050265 m2; BarLength: 1.06682 m; Material: Steel

# IfcReinforcingBarType, no part of this type: type
PredefinedType: MAIN; NominalDiameter: 0.016 m; CrossSectionArea: 0.00020106 m2; BarLength: 8.54503 m; Material: Steel

# IfcReinforcingBarType, no part of this type: type
PredefinedType: MAIN; NominalDiameter: 0.016 m; CrossSectionArea: 0.00020106 m2; BarLength: 7.94503 m; Material: Steel

# IfcReinforcingBarType, no part of this type: type
PredefinedType: LIGATURE; NominalDiameter: 0.008 m; CrossSectionArea: 0.000050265 m2; BarLength: 1.5868 m; Material: Steel

# IfcReinforcingBarType, no part of this type: type
PredefinedType: MAIN; NominalDiameter: 0.018 m; CrossSectionArea: 0.00025447 m2; BarLength: 9.00197 m; Material: Steel

# IfcReinforcingBarType, no part of this type: type
PredefinedType: MAIN; NominalDiameter: 0.018 m; CrossSectionArea: 0.00025447 m2; BarLength: 9.14976 m; Material: Steel

# IfcReinforcingBarType, no part of this type: type
PredefinedType: MAIN; NominalDiameter: 0.018 m; CrossSectionArea: 0.00025447 m2; BarLength: 9.90276 m; Material: Steel

# IfcReinforcingBarType, no part of this type: type
PredefinedType: MAIN; NominalDiameter: 0.018 m; CrossSectionArea: 0.00025447 m2; BarLength: 9.16121 m; Material: Steel

# IfcReinforcingBarType, no part of this type: type
PredefinedType: MAIN; NominalDiameter: 0.016 m; CrossSectionArea: 0.00020106 m2; BarLength: 4.59121 m; Material: Steel

# IfcReinforcingBarType, no part of this type: type
PredefinedType: MAIN; NominalDiameter: 0.012 m; CrossSectionArea: 0.0001131 m2; BarLength: 2.52121 m; Material: Steel

# IfcReinforcingBarType, no part of this type: type
PredefinedType: MAIN; NominalDiameter: 0.012 m; CrossSectionArea: 0.0001131 m2; BarLength: 6.50121 m; Material: Steel

# IfcReinforcingBarType, no part of this type: type
PredefinedType: MAIN; NominalDiameter: 0.012 m; CrossSectionArea: 0.0001131 m2; BarLength: 6.70121 m; Material: Steel

# IfcReinforcingBarType, no part of this type: type
PredefinedType: LIGATURE; NominalDiameter: 0.008 m; CrossSectionArea: 0.000050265 m2; BarLength: 1.06682 m; Material: Steel

# IfcReinforcingBarType, no part of this type: type
PredefinedType: MAIN; NominalDiameter: 0.016 m; CrossSectionArea: 0.00020106 m2; BarLength: 3.64721 m; Material: Steel

# IfcReinforcingBarType, no part of this type: type
PredefinedType: LIGATURE; NominalDiameter: 0.008 m; CrossSectionArea: 0.000050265 m2; BarLength: 1.5868 m; Material: Steel

# IfcReinforcingBarType, no part of this type: type
PredefinedType: MAIN; NominalDiameter: 0.018 m; CrossSectionArea: 0.00025447 m2; BarLength: 9.0443 m; Material: Steel

# IfcReinforcingBarType, no part of this type: type
PredefinedType: MAIN; NominalDiameter: 0.018 m; CrossSectionArea: 0.00025447 m2; BarLength: 9.84121 m; Material: Steel

# IfcReinforcingBarType, no part of this type: type
PredefinedType: MAIN; NominalDiameter: 0.018 m; CrossSectionArea: 0.00025447 m2; BarLength: 9.84741 m; Material: Steel

# IfcReinforcingBarType, no part of this type: type
PredefinedType: MAIN; NominalDiameter: 0.018 m; CrossSectionArea: 0.00025447 m2; BarLength: 9.49121 m; Material: Steel

# IfcReinforcingBarType, no part of this type: type
PredefinedType: MAIN; NominalDiameter: 0.018 m; CrossSectionArea: 0.00025447 m2; BarLength: 4.17109 m; Material: Steel

# IfcReinforcingBarType, no part of this type: type
PredefinedType: MAIN; NominalDiameter: 0.016 m; CrossSectionArea: 0.00020106 m2; BarLength: 3.95121 m; Material: Steel

# IfcReinforcingBarType, no part of this type: type
PredefinedType: MAIN; NominalDiameter: 0.012 m; CrossSectionArea: 0.0001131 m2; BarLength: 2.12121 m; Material: Steel

# IfcReinforcingBarType, no part of this type: type
PredefinedType: MAIN; NominalDiameter: 0.012 m; CrossSectionArea: 0.0001131 m2; BarLength: 6.70121 m; Material: Steel

# IfcReinforcingBarType, no part of this type: type
PredefinedType: MAIN; NominalDiameter: 0.012 m; CrossSectionArea: 0.0001131 m2; BarLength: 2.52122 m; Material: Steel

# IfcReinforcingBarType, no part of this type: type
PredefinedType: MAIN; NominalDiameter: 0.012 m; CrossSectionArea: 0.0001131 m2; BarLength: 6.50121 m; Material: Steel

# IfcReinforcingBarType, no part of this type: type
PredefinedType: LIGATURE; NominalDiameter: 0.008 m; CrossSectionArea: 0.000050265 m2; BarLength: 1.06682 m; Material: Steel

# IfcReinforcingBarType, no part of this type: type
PredefinedType: MAIN; NominalDiameter: 0.02 m; CrossSectionArea: 0.00031416 m2; BarLength: 6.22721 m; Material: Steel

# IfcReinforcingBarType, no part of this type: type
PredefinedType: MAIN; NominalDiameter: 0.014 m; CrossSectionArea: 0.00015394 m2; BarLength: 1.97562 m; Material: Steel

# IfcReinforcingBarType, no part of this type: type
PredefinedType: LIGATURE; NominalDiameter: 0.008 m; CrossSectionArea: 0.000050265 m2; BarLength: 1.5868 m; Material: Steel

# IfcReinforcingBarType, no part of this type: type
PredefinedType: MAIN; NominalDiameter: 0.018 m; CrossSectionArea: 0.00025447 m2; BarLength: 8.9443 m; Material: Steel

# IfcReinforcingBarType, no part of this type: type
PredefinedType: MAIN; NominalDiameter: 0.018 m; CrossSectionArea: 0.00025447 m2; BarLength: 7.64739 m; Material: Steel

# IfcReinforcingBarType, no part of this type: type
PredefinedType: MAIN; NominalDiameter: 0.016 m; CrossSectionArea: 0.00020106 m2; BarLength: 3.18285 m; Material: Steel

# IfcReinforcingBarType, no part of this type: type
PredefinedType: MAIN; NominalDiameter: 0.018 m; CrossSectionArea: 0.00025447 m2; BarLength: 9.42831 m; Material: Steel

# IfcReinforcingBarType, no part of this type: type
PredefinedType: MAIN; NominalDiameter: 0.018 m; CrossSectionArea: 0.00025447 m2; BarLength: 8.18739 m; Material: Steel

# IfcReinforcingBarType, no part of this type: type
PredefinedType: MAIN; NominalDiameter: 0.016 m; CrossSectionArea: 0.00020106 m2; BarLength: 3.93121 m; Material: Steel

# IfcReinforcingBarType, no part of this type: type
PredefinedType: MAIN; NominalDiameter: 0.016 m; CrossSectionArea: 0.00020106 m2; BarLength: 3.63121 m; Material: Steel

# IfcReinforcingBarType, no part of this type: type
PredefinedType: MAIN; NominalDiameter: 0.012 m; CrossSectionArea: 0.0001131 m2; BarLength: 2.12121 m; Material: Steel

# IfcReinforcingBarType, no part of this type: type
PredefinedType: MAIN; NominalDiameter: 0.012 m; CrossSectionArea: 0.0001131 m2; BarLength: 6.40121 m; Material: Steel

# IfcReinforcingBarType, no part of this type: type
PredefinedType: LIGATURE; NominalDiameter: 0.008 m; CrossSectionArea: 0.000050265 m2; BarLength: 1.58681 m; Material: Steel

# IfcReinforcingBarType, no part of this type: type
PredefinedType: MAIN; NominalDiameter: 0.018 m; CrossSectionArea: 0.00025447 m2; BarLength: 8.9443 m; Material: Steel

# IfcReinforcingBarType, no part of this type: type
PredefinedType: MAIN; NominalDiameter: 0.018 m; CrossSectionArea: 0.00025447 m2; BarLength: 8.71476 m; Material: Steel

# IfcReinforcingBarType, no part of this type: type
PredefinedType: MAIN; NominalDiameter: 0.018 m; CrossSectionArea: 0.00025447 m2; BarLength: 9.42831 m; Material: Steel

# IfcReinforcingBarType, no part of this type: type
PredefinedType: MAIN; NominalDiameter: 0.016 m; CrossSectionArea: 0.00020106 m2; BarLength: 4.15121 m; Material: Steel

# IfcReinforcingBarType, no part of this type: type
PredefinedType: MAIN; NominalDiameter: 0.016 m; CrossSectionArea: 0.00020106 m2; BarLength: 3.95121 m; Material: Steel

# IfcReinforcingBarType, no part of this type: type
PredefinedType: MAIN; NominalDiameter: 0.012 m; CrossSectionArea: 0.0001131 m2; BarLength: 2.12121 m; Material: Steel

# IfcReinforcingBarType, no part of this type: type
PredefinedType: MAIN; NominalDiameter: 0.012 m; CrossSectionArea: 0.0001131 m2; BarLength: 6.40121 m; Material: Steel

# IfcReinforcingBarType, no part of this type: type
PredefinedType: LIGATURE; NominalDiameter: 0.008 m; CrossSectionArea: 0.000050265 m2; BarLength: 1.5868 m; Material: Steel

# IfcReinforcingBarType, no part of this type: type
PredefinedType: MAIN; NominalDiameter: 0.018 m; CrossSectionArea: 0.00025447 m2; BarLength: 10.0912 m; Material: Steel

# IfcReinforcingBarType, no part of this type: type
PredefinedType: MAIN; NominalDiameter: 0.016 m; CrossSectionArea: 0.00020106 m2; BarLength: 9.11285 m; Material: Steel

# IfcReinforcingBarType, no part of this type: type
PredefinedType: MAIN; NominalDiameter: 0.02 m; CrossSectionArea: 0.00031416 m2; BarLength: 9.69122 m; Material: Steel

# IfcReinforcingBarType, no part of this type: type
PredefinedType: MAIN; NominalDiameter: 0.016 m; CrossSectionArea: 0.00020106 m2; BarLength: 4.59122 m; Material: Steel

# IfcReinforcingBarType, no part of this type: type
PredefinedType: MAIN; NominalDiameter: 0.016 m; CrossSectionArea: 0.00020106 m2; BarLength: 4.59121 m; Material: Steel

# IfcReinforcingBarType, no part of this type: type
PredefinedType: MAIN; NominalDiameter: 0.012 m; CrossSectionArea: 0.0001131 m2; BarLength: 2.52121 m; Material: Steel

# IfcReinforcingBarType, no part of this type: type
PredefinedType: MAIN; NominalDiameter: 0.012 m; CrossSectionArea: 0.0001131 m2; BarLength: 6.70121 m; Material: Steel

# IfcReinforcingBarType, no part of this type: type
PredefinedType: MAIN; NominalDiameter: 0.012 m; CrossSectionArea: 0.0001131 m2; BarLength: 6.50121 m; Material: Steel

# IfcReinforcingBarType, no part of this type: type
PredefinedType: LIGATURE; NominalDiameter: 0.008 m; CrossSectionArea: 0.000050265 m2; BarLength: 1.5868 m; Material: Steel

# IfcReinforcingBarType, no part of this type: type
PredefinedType: MAIN; NominalDiameter: 0.018 m; CrossSectionArea: 0.00025447 m2; BarLength: 11.9412 m; Material: Steel

# IfcReinforcingBarType, no part of this type: type
PredefinedType: MAIN; NominalDiameter: 0.02 m; CrossSectionArea: 0.00031416 m2; BarLength: 11.0958 m; Material: Steel

# IfcReinforcingBarType, no part of this type: type
PredefinedType: MAIN; NominalDiameter: 0.018 m; CrossSectionArea: 0.00025447 m2; BarLength: 6.52121 m; Material: Steel

# IfcReinforcingBarType, no part of this type: type
PredefinedType: MAIN; NominalDiameter: 0.018 m; CrossSectionArea: 0.00025447 m2; BarLength: 5.87121 m; Material: Steel

# IfcReinforcingBarType, no part of this type: type
PredefinedType: MAIN; NominalDiameter: 0.018 m; CrossSectionArea: 0.00025447 m2; BarLength: 11.9612 m; Material: Steel

# IfcReinforcingBarType, no part of this type: type
PredefinedType: MAIN; NominalDiameter: 0.018 m; CrossSectionArea: 0.00025447 m2; BarLength: 11.9512 m; Material: Steel

# IfcReinforcingBarType, no part of this type: type
PredefinedType: MAIN; NominalDiameter: 0.018 m; CrossSectionArea: 0.00025447 m2; BarLength: 6.58121 m; Material: Steel

# IfcReinforcingBarType, no part of this type: type
PredefinedType: MAIN; NominalDiameter: 0.018 m; CrossSectionArea: 0.00025447 m2; BarLength: 6.33121 m; Material: Steel

# IfcReinforcingBarType, no part of this type: type
PredefinedType: MAIN; NominalDiameter: 0.012 m; CrossSectionArea: 0.0001131 m2; BarLength: 4.37121 m; Material: Steel

# IfcReinforcingBarType, no part of this type: type
PredefinedType: MAIN; NominalDiameter: 0.012 m; CrossSectionArea: 0.0001131 m2; BarLength: 4.72121 m; Material: Steel

# IfcReinforcingBarType, no part of this type: type
PredefinedType: MAIN; NominalDiameter: 0.012 m; CrossSectionArea: 0.0001131 m2; BarLength: 6.77121 m; Material: Steel

# IfcReinforcingBarType, no part of this type: type
PredefinedType: MAIN; NominalDiameter: 0.012 m; CrossSectionArea: 0.0001131 m2; BarLength: 6.57122 m; Material: Steel

# IfcReinforcingBarType, no part of this type: type
PredefinedType: LIGATURE; NominalDiameter: 0.008 m; CrossSectionArea: 0.000050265 m2; BarLength: 1.57214 m; Material: Steel

# IfcReinforcingBarType, no part of this type: type
PredefinedType: MAIN; NominalDiameter: 0.016 m; CrossSectionArea: 0.00020106 m2; BarLength: 10.0912 m; Material: Steel

# IfcReinforcingBarType, no part of this type: type
PredefinedType: MAIN; NominalDiameter: 0.016 m; CrossSectionArea: 0.00020106 m2; BarLength: 8.19121 m; Material: Steel

# IfcReinforcingBarType, no part of this type: type
PredefinedType: MAIN; NominalDiameter: 0.016 m; CrossSectionArea: 0.00020106 m2; BarLength: 10.5912 m; Material: Steel

# IfcReinforcingBarType, no part of this type: type
PredefinedType: MAIN; NominalDiameter: 0.018 m; CrossSectionArea: 0.00025447 m2; BarLength: 7.19121 m; Material: Steel

# IfcReinforcingBarType, no part of this type: type
PredefinedType: MAIN; NominalDiameter: 0.016 m; CrossSectionArea: 0.00020106 m2; BarLength: 7.19121 m; Material: Steel

# IfcReinforcingBarType, no part of this type: type
PredefinedType: MAIN; NominalDiameter: 0.02 m; CrossSectionArea: 0.00031416 m2; BarLength: 7.19121 m; Material: Steel

# IfcReinforcingBarType, no part of this type: type
PredefinedType: MAIN; NominalDiameter: 0.018 m; CrossSectionArea: 0.00025447 m2; BarLength: 7.19121 m; Material: Steel

# IfcReinforcingBarType, no part of this type: type
PredefinedType: MAIN; NominalDiameter: 0.02 m; CrossSectionArea: 0.00031416 m2; BarLength: 3.59121 m; Material: Steel

# IfcReinforcingBarType, no part of this type: type
PredefinedType: MAIN; NominalDiameter: 0.018 m; CrossSectionArea: 0.00025447 m2; BarLength: 3.59121 m; Material: Steel

# IfcReinforcingBarType, no part of this type: type
PredefinedType: MAIN; NominalDiameter: 0.018 m; CrossSectionArea: 0.00025447 m2; BarLength: 3.59121 m; Material: Steel

# IfcReinforcingBarType, no part of this type: type
PredefinedType: MAIN; NominalDiameter: 0.016 m; CrossSectionArea: 0.00020106 m2; BarLength: 3.59121 m; Material: Steel

# IfcReinforcingBarType, no part of this type: type
PredefinedType: LIGATURE; NominalDiameter: 0.008 m; CrossSectionArea: 0.000050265 m2; BarLength: 1.5868 m; Material: Steel

# IfcReinforcingBarType, no part of this type: type
PredefinedType: MAIN; NominalDiameter: 0.018 m; CrossSectionArea: 0.00025447 m2; BarLength: 11.9412 m; Material: Steel

# IfcReinforcingBarType, no part of this type: type
PredefinedType: MAIN; NominalDiameter: 0.02 m; CrossSectionArea: 0.00031416 m2; BarLength: 11.9012 m; Material: Steel

# IfcReinforcingBarType, no part of this type: type
PredefinedType: MAIN; NominalDiameter: 0.018 m; CrossSectionArea: 0.00025447 m2; BarLength: 6.94121 m; Material: Steel

# IfcReinforcingBarType, no part of this type: type
PredefinedType: MAIN; NominalDiameter: 0.018 m; CrossSectionArea: 0.00025447 m2; BarLength: 5.45976 m; Material: Steel

# IfcReinforcingBarType, no part of this type: type
PredefinedType: MAIN; NominalDiameter: 0.018 m; CrossSectionArea: 0.00025447 m2; BarLength: 11.9712 m; Material: Steel

# IfcReinforcingBarType, no part of this type: type
PredefinedType: MAIN; NominalDiameter: 0.018 m; CrossSectionArea: 0.00025447 m2; BarLength: 11.4598 m; Material: Steel

# IfcReinforcingBarType, no part of this type: type
PredefinedType: MAIN; NominalDiameter: 0.018 m; CrossSectionArea: 0.00025447 m2; BarLength: 6.40121 m; Material: Steel

# IfcReinforcingBarType, no part of this type: type
PredefinedType: MAIN; NominalDiameter: 0.018 m; CrossSectionArea: 0.00025447 m2; BarLength: 5.95121 m; Material: Steel

# IfcReinforcingBarType, no part of this type: type
PredefinedType: MAIN; NominalDiameter: 0.012 m; CrossSectionArea: 0.0001131 m2; BarLength: 6.57121 m; Material: Steel

# IfcReinforcingBarType, no part of this type: type
PredefinedType: MAIN; NominalDiameter: 0.012 m; CrossSectionArea: 0.0001131 m2; BarLength: 4.32121 m; Material: Steel

# IfcReinforcingBarType, no part of this type: type
PredefinedType: MAIN; NominalDiameter: 0.012 m; CrossSectionArea: 0.0001131 m2; BarLength: 6.77121 m; Material: Steel

# IfcReinforcingBarType, no part of this type: type
PredefinedType: MAIN; NominalDiameter: 0.012 m; CrossSectionArea: 0.0001131 m2; BarLength: 4.37121 m; Material: Steel

# IfcReinforcingBarType, no part of this type: type
PredefinedType: LIGATURE; NominalDiameter: 0.008 m; CrossSectionArea: 0.000050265 m2; BarLength: 1.5868 m; Material: Steel

# IfcReinforcingBarType, no part of this type: type
PredefinedType: MAIN; NominalDiameter: 0.02 m; CrossSectionArea: 0.00031416 m2; BarLength: 12.4312 m; Material: Steel

# IfcReinforcingBarType, no part of this type: type
PredefinedType: MAIN; NominalDiameter: 0.02 m; CrossSectionArea: 0.00031416 m2; BarLength: 11.9912 m; Material: Steel

# IfcReinforcingBarType, no part of this type: type
PredefinedType: MAIN; NominalDiameter: 0.012 m; CrossSectionArea: 0.0001131 m2; BarLength: 6.50121 m; Material: Steel

# IfcReinforcingBarType, no part of this type: type
PredefinedType: MAIN; NominalDiameter: 0.012 m; CrossSectionArea: 0.0001131 m2; BarLength: 6.70121 m; Material: Steel

# IfcReinforcingBarType, no part of this type: type
PredefinedType: LIGATURE; NominalDiameter: 0.008 m; CrossSectionArea: 0.000050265 m2; BarLength: 1.57214 m; Material: Steel

# IfcReinforcingBarType, no part of this type: type
PredefinedType: MAIN; NominalDiameter: 0.016 m; CrossSectionArea: 0.00020106 m2; BarLength: 11.9072 m; Material: Steel

# IfcReinforcingBarType, no part of this type: type
PredefinedType: MAIN; NominalDiameter: 0.02 m; CrossSectionArea: 0.00031416 m2; BarLength: 8.69121 m; Material: Steel

# IfcReinforcingBarType, no part of this type: type
PredefinedType: MAIN; NominalDiameter: 0.018 m; CrossSectionArea: 0.00025447 m2; BarLength: 8.69121 m; Material: Steel

# IfcReinforcingBarType, no part of this type: type
PredefinedType: MAIN; NominalDiameter: 0.018 m; CrossSectionArea: 0.00025447 m2; BarLength: 4.59121 m; Material: Steel

# IfcReinforcingBarType, no part of this type: type
PredefinedType: MAIN; NominalDiameter: 0.016 m; CrossSectionArea: 0.00020106 m2; BarLength: 4.59121 m; Material: Steel

# IfcReinforcingBarType, no part of this type: type
PredefinedType: MAIN; NominalDiameter: 0.02 m; CrossSectionArea: 0.00031416 m2; BarLength: 4.59121 m; Material: Steel

# IfcReinforcingBarType, no part of this type: type
PredefinedType: MAIN; NominalDiameter: 0.018 m; CrossSectionArea: 0.00025447 m2; BarLength: 4.59121 m; Material: Steel

# IfcReinforcingBarType, no part of this type: type
PredefinedType: LIGATURE; NominalDiameter: 0.008 m; CrossSectionArea: 0.000050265 m2; BarLength: 1.06682 m; Material: Steel

# IfcReinforcingBarType, no part of this type: type
PredefinedType: MAIN; NominalDiameter: 0.016 m; CrossSectionArea: 0.00020106 m2; BarLength: 6.47721 m; Material: Steel

# IfcReinforcingBarType, no part of this type: type
PredefinedType: LIGATURE; NominalDiameter: 0.008 m; CrossSectionArea: 0.000050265 m2; BarLength: 1.57214 m; Material: Steel

# IfcReinforcingBarType, no part of this type: type
PredefinedType: MAIN; NominalDiameter: 0.02 m; CrossSectionArea: 0.00031416 m2; BarLength: 4.64876 m; Material: Steel

# IfcReinforcingBarType, no part of this type: type
PredefinedType: MAIN; NominalDiameter: 0.018 m; CrossSectionArea: 0.00025447 m2; BarLength: 4.64876 m; Material: Steel

# IfcReinforcingBarType, no part of this type: type
PredefinedType: MAIN; NominalDiameter: 0.02 m; CrossSectionArea: 0.00031416 m2; BarLength: 4.59121 m; Material: Steel

# IfcReinforcingBarType, no part of this type: type
PredefinedType: MAIN; NominalDiameter: 0.018 m; CrossSectionArea: 0.00025447 m2; BarLength: 4.59121 m; Material: Steel

# IfcReinforcingBarType, no part of this type: type
PredefinedType: MAIN; NominalDiameter: 0.016 m; CrossSectionArea: 0.00020106 m2; BarLength: 4.59121 m; Material: Steel

# IfcReinforcingBarType, no part of this type: type
PredefinedType: LIGATURE; NominalDiameter: 0.008 m; CrossSectionArea: 0.000050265 m2; BarLength: 1.57214 m; Material: Steel

# IfcReinforcingBarType, no part of this type: type
PredefinedType: MAIN; NominalDiameter: 0.02 m; CrossSectionArea: 0.00031416 m2; BarLength: 4.64876 m; Material: Steel

# IfcReinforcingBarType, no part of this type: type
PredefinedType: MAIN; NominalDiameter: 0.018 m; CrossSectionArea: 0.00025447 m2; BarLength: 4.64876 m; Material: Steel

# IfcReinforcingBarType, no part of this type: type
PredefinedType: MAIN; NominalDiameter: 0.02 m; CrossSectionArea: 0.00031416 m2; BarLength: 4.59121 m; Material: Steel

# IfcReinforcingBarType, no part of this type: type
PredefinedType: MAIN; NominalDiameter: 0.018 m; CrossSectionArea: 0.00025447 m2; BarLength: 4.59121 m; Material: Steel

# IfcReinforcingBarType, no part of this type: type
PredefinedType: LIGATURE; NominalDiameter: 0.008 m; CrossSectionArea: 0.000050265 m2; BarLength: 1.5868 m; Material: Steel

# IfcReinforcingBarType, no part of this type: type
PredefinedType: MAIN; NominalDiameter: 0.02 m; CrossSectionArea: 0.00031416 m2; BarLength: 12.4312 m; Material: Steel

# IfcReinforcingBarType, no part of this type: type
PredefinedType: MAIN; NominalDiameter: 0.02 m; CrossSectionArea: 0.00031416 m2; BarLength: 11.9912 m; Material: Steel

# IfcReinforcingBarType, no part of this type: type
PredefinedType: MAIN; NominalDiameter: 0.012 m; CrossSectionArea: 0.0001131 m2; BarLength: 6.70121 m; Material: Steel

# IfcReinforcingBarType, no part of this type: type
PredefinedType: MAIN; NominalDiameter: 0.012 m; CrossSectionArea: 0.0001131 m2; BarLength: 5.72788 m; Material: Steel

# IfcReinforcingBarType, no part of this type: type
PredefinedType: LIGATURE; NominalDiameter: 0.008 m; CrossSectionArea: 0.000050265 m2; BarLength: 1.5868 m; Material: Steel

# IfcReinforcingBarType, no part of this type: type
PredefinedType: MAIN; NominalDiameter: 0.018 m; CrossSectionArea: 0.00025447 m2; BarLength: 11.9598 m; Material: Steel

# IfcReinforcingBarType, no part of this type: type
PredefinedType: MAIN; NominalDiameter: 0.018 m; CrossSectionArea: 0.00025447 m2; BarLength: 10.9598 m; Material: Steel

# IfcReinforcingBarType, no part of this type: type
PredefinedType: MAIN; NominalDiameter: 0.018 m; CrossSectionArea: 0.00025447 m2; BarLength: 6.33121 m; Material: Steel

# IfcReinforcingBarType, no part of this type: type
PredefinedType: MAIN; NominalDiameter: 0.018 m; CrossSectionArea: 0.00025447 m2; BarLength: 5.59121 m; Material: Steel

# IfcReinforcingBarType, no part of this type: type
PredefinedType: MAIN; NominalDiameter: 0.018 m; CrossSectionArea: 0.00025447 m2; BarLength: 10.7443 m; Material: Steel

# IfcReinforcingBarType, no part of this type: type
PredefinedType: MAIN; NominalDiameter: 0.018 m; CrossSectionArea: 0.00025447 m2; BarLength: 10.4943 m; Material: Steel

# IfcReinforcingBarType, no part of this type: type
PredefinedType: MAIN; NominalDiameter: 0.018 m; CrossSectionArea: 0.00025447 m2; BarLength: 5.97121 m; Material: Steel

# IfcReinforcingBarType, no part of this type: type
PredefinedType: MAIN; NominalDiameter: 0.018 m; CrossSectionArea: 0.00025447 m2; BarLength: 5.3443 m; Material: Steel

# IfcReinforcingBarType, no part of this type: type
PredefinedType: MAIN; NominalDiameter: 0.012 m; CrossSectionArea: 0.0001131 m2; BarLength: 4.72121 m; Material: Steel

# IfcReinforcingBarType, no part of this type: type
PredefinedType: MAIN; NominalDiameter: 0.012 m; CrossSectionArea: 0.0001131 m2; BarLength: 4.40121 m; Material: Steel

# IfcReinforcingBarType, no part of this type: type
PredefinedType: MAIN; NominalDiameter: 0.012 m; CrossSectionArea: 0.0001131 m2; BarLength: 6.60122 m; Material: Steel

# IfcReinforcingBarType, no part of this type: type
PredefinedType: MAIN; NominalDiameter: 0.012 m; CrossSectionArea: 0.0001131 m2; BarLength: 6.80122 m; Material: Steel

# IfcReinforcingBarType, no part of this type: type
PredefinedType: LIGATURE; NominalDiameter: 0.008 m; CrossSectionArea: 0.000050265 m2; BarLength: 1.5868 m; Material: Steel

# IfcReinforcingBarType, no part of this type: type
PredefinedType: MAIN; NominalDiameter: 0.016 m; CrossSectionArea: 0.00020106 m2; BarLength: 11.0912 m; Material: Steel

# IfcReinforcingBarType, no part of this type: type
PredefinedType: MAIN; NominalDiameter: 0.016 m; CrossSectionArea: 0.00020106 m2; BarLength: 8.29448 m; Material: Steel

# IfcReinforcingBarType, no part of this type: type
PredefinedType: MAIN; NominalDiameter: 0.02 m; CrossSectionArea: 0.00031416 m2; BarLength: 5.09121 m; Material: Steel

# IfcReinforcingBarType, no part of this type: type
PredefinedType: MAIN; NominalDiameter: 0.018 m; CrossSectionArea: 0.00025447 m2; BarLength: 10.7443 m; Material: Steel

# IfcReinforcingBarType, no part of this type: type
PredefinedType: MAIN; NominalDiameter: 0.018 m; CrossSectionArea: 0.00025447 m2; BarLength: 10.4943 m; Material: Steel

# IfcReinforcingBarType, no part of this type: type
PredefinedType: MAIN; NominalDiameter: 0.012 m; CrossSectionArea: 0.0001131 m2; BarLength: 4.32121 m; Material: Steel

# IfcReinforcingBarType, no part of this type: type
PredefinedType: MAIN; NominalDiameter: 0.012 m; CrossSectionArea: 0.0001131 m2; BarLength: 6.80121 m; Material: Steel

# IfcReinforcingBarType, no part of this type: type
PredefinedType: MAIN; NominalDiameter: 0.012 m; CrossSectionArea: 0.0001131 m2; BarLength: 6.60122 m; Material: Steel

# IfcReinforcingBarType, no part of this type: type
PredefinedType: MAIN; NominalDiameter: 0.012 m; CrossSectionArea: 0.0001131 m2; BarLength: 4.40121 m; Material: Steel

# IfcReinforcingBarType, no part of this type: type
PredefinedType: MAIN; NominalDiameter: 0.016 m; CrossSectionArea: 0.00020106 m2; BarLength: 2.79448 m; Material: Steel

# IfcReinforcingBarType, no part of this type: type
PredefinedType: LIGATURE; NominalDiameter: 0.008 m; CrossSectionArea: 0.000050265 m2; BarLength: 1.5868 m; Material: Steel

# IfcReinforcingBarType, no part of this type: type
PredefinedType: MAIN; NominalDiameter: 0.02 m; CrossSectionArea: 0.00031416 m2; BarLength: 11.0912 m; Material: Steel

# IfcReinforcingBarType, no part of this type: type
PredefinedType: MAIN; NominalDiameter: 0.02 m; CrossSectionArea: 0.00031416 m2; BarLength: 11.0912 m; Material: Steel

# IfcReinforcingBarType, no part of this type: type
PredefinedType: MAIN; NominalDiameter: 0.016 m; CrossSectionArea: 0.00020106 m2; BarLength: 5.09122 m; Material: Steel

# IfcReinforcingBarType, no part of this type: type
PredefinedType: MAIN; NominalDiameter: 0.018 m; CrossSectionArea: 0.00025447 m2; BarLength: 5.09121 m; Material: Steel

# IfcReinforcingBarType, no part of this type: type
PredefinedType: MAIN; NominalDiameter: 0.02 m; CrossSectionArea: 0.00031416 m2; BarLength: 10.6258 m; Material: Steel

# IfcReinforcingBarType, no part of this type: type
PredefinedType: MAIN; NominalDiameter: 0.02 m; CrossSectionArea: 0.00031416 m2; BarLength: 10.8758 m; Material: Steel

# IfcReinforcingBarType, no part of this type: type
PredefinedType: MAIN; NominalDiameter: 0.016 m; CrossSectionArea: 0.00020106 m2; BarLength: 5.21285 m; Material: Steel

# IfcReinforcingBarType, no part of this type: type
PredefinedType: MAIN; NominalDiameter: 0.02 m; CrossSectionArea: 0.00031416 m2; BarLength: 5.02576 m; Material: Steel

# IfcReinforcingBarType, no part of this type: type
PredefinedType: MAIN; NominalDiameter: 0.012 m; CrossSectionArea: 0.0001131 m2; BarLength: 4.32121 m; Material: Steel

# IfcReinforcingBarType, no part of this type: type
PredefinedType: MAIN; NominalDiameter: 0.012 m; CrossSectionArea: 0.0001131 m2; BarLength: 6.80121 m; Material: Steel

# IfcReinforcingBarType, no part of this type: type
PredefinedType: MAIN; NominalDiameter: 0.012 m; CrossSectionArea: 0.0001131 m2; BarLength: 6.60121 m; Material: Steel

# IfcReinforcingBarType, no part of this type: type
PredefinedType: MAIN; NominalDiameter: 0.012 m; CrossSectionArea: 0.0001131 m2; BarLength: 4.40121 m; Material: Steel

# IfcReinforcingBarType, no part of this type: type
PredefinedType: MAIN; NominalDiameter: 0.02 m; CrossSectionArea: 0.00031416 m2; BarLength: 4.19122 m; Material: Steel

# IfcReinforcingBarType, no part of this type: type
PredefinedType: MAIN; NominalDiameter: 0.016 m; CrossSectionArea: 0.00020106 m2; BarLength: 4.19122 m; Material: Steel

# IfcReinforcingBarType, no part of this type: type
PredefinedType: MAIN; NominalDiameter: 0.018 m; CrossSectionArea: 0.00025447 m2; BarLength: 4.19122 m; Material: Steel

# IfcReinforcingBarType, no part of this type: type
PredefinedType: MAIN; NominalDiameter: 0.016 m; CrossSectionArea: 0.00020106 m2; BarLength: 2.29448 m; Material: Steel

# IfcReinforcingBarType, no part of this type: type
PredefinedType: MAIN; NominalDiameter: 0.014 m; CrossSectionArea: 0.00015394 m2; BarLength: 3.19122 m; Material: Steel

# IfcReinforcingBarType, no part of this type: type
PredefinedType: LIGATURE; NominalDiameter: 0.008 m; CrossSectionArea: 0.000050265 m2; BarLength: 1.5868 m; Material: Steel

# IfcReinforcingBarType, no part of this type: type
PredefinedType: MAIN; NominalDiameter: 0.018 m; CrossSectionArea: 0.00025447 m2; BarLength: 7.49081 m; Material: Steel

# IfcReinforcingBarType, no part of this type: type
PredefinedType: MAIN; NominalDiameter: 0.018 m; CrossSectionArea: 0.00025447 m2; BarLength: 7.49081 m; Material: Steel

# IfcReinforcingBarType, no part of this type: type
PredefinedType: MAIN; NominalDiameter: 0.02 m; CrossSectionArea: 0.00031416 m2; BarLength: 12.1783 m; Material: Steel

# IfcReinforcingBarType, no part of this type: type
PredefinedType: MAIN; NominalDiameter: 0.018 m; CrossSectionArea: 0.00025447 m2; BarLength: 12.1783 m; Material: Steel

# IfcReinforcingBarType, no part of this type: type
PredefinedType: MAIN; NominalDiameter: 0.012 m; CrossSectionArea: 0.0001131 m2; BarLength: 6.16672 m; Material: Steel

# IfcReinforcingBarType, no part of this type: type
PredefinedType: MAIN; NominalDiameter: 0.012 m; CrossSectionArea: 0.0001131 m2; BarLength: 6.36987 m; Material: Steel

# IfcReinforcingBarType, no part of this type: type
PredefinedType: LIGATURE; NominalDiameter: 0.008 m; CrossSectionArea: 0.000050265 m2; BarLength: 1.57214 m; Material: Steel

# IfcReinforcingBarType, no part of this type: type
PredefinedType: MAIN; NominalDiameter: 0.016 m; CrossSectionArea: 0.00020106 m2; BarLength: 7.589 m; Material: Steel

# IfcReinforcingBarType, no part of this type: type
PredefinedType: MAIN; NominalDiameter: 0.016 m; CrossSectionArea: 0.00020106 m2; BarLength: 7.09316 m; Material: Steel

# IfcReinforcingBarType, no part of this type: type
PredefinedType: MAIN; NominalDiameter: 0.02 m; CrossSectionArea: 0.00031416 m2; BarLength: 8.69116 m; Material: Steel

# IfcReinforcingBarType, no part of this type: type
PredefinedType: MAIN; NominalDiameter: 0.016 m; CrossSectionArea: 0.00020106 m2; BarLength: 8.69116 m; Material: Steel

# IfcReinforcingBarType, no part of this type: type
PredefinedType: MAIN; NominalDiameter: 0.018 m; CrossSectionArea: 0.00025447 m2; BarLength: 4.21654 m; Material: Steel

# IfcReinforcingBarType, no part of this type: type
PredefinedType: MAIN; NominalDiameter: 0.016 m; CrossSectionArea: 0.00020106 m2; BarLength: 4.21654 m; Material: Steel

# IfcReinforcingBarType, no part of this type: type
PredefinedType: MAIN; NominalDiameter: 0.02 m; CrossSectionArea: 0.00031416 m2; BarLength: 4.59273 m; Material: Steel

# IfcReinforcingBarType, no part of this type: type
PredefinedType: MAIN; NominalDiameter: 0.018 m; CrossSectionArea: 0.00025447 m2; BarLength: 4.59273 m; Material: Steel

# IfcReinforcingBarType, no part of this type: type
PredefinedType: LIGATURE; NominalDiameter: 0.008 m; CrossSectionArea: 0.000050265 m2; BarLength: 1.57214 m; Material: Steel

# IfcReinforcingBarType, no part of this type: type
PredefinedType: MAIN; NominalDiameter: 0.018 m; CrossSectionArea: 0.00025447 m2; BarLength: 6.63307 m; Material: Steel

# IfcReinforcingBarType, no part of this type: type
PredefinedType: MAIN; NominalDiameter: 0.02 m; CrossSectionArea: 0.00031416 m2; BarLength: 8.69116 m; Material: Steel

# IfcReinforcingBarType, no part of this type: type
PredefinedType: MAIN; NominalDiameter: 0.016 m; CrossSectionArea: 0.00020106 m2; BarLength: 8.69116 m; Material: Steel

# IfcReinforcingBarType, no part of this type: type
PredefinedType: MAIN; NominalDiameter: 0.02 m; CrossSectionArea: 0.00031416 m2; BarLength: 8.69116 m; Material: Steel

# IfcReinforcingBarType, no part of this type: type
PredefinedType: MAIN; NominalDiameter: 0.018 m; CrossSectionArea: 0.00025447 m2; BarLength: 8.69116 m; Material: Steel

# IfcReinforcingBarType, no part of this type: type
PredefinedType: MAIN; NominalDiameter: 0.018 m; CrossSectionArea: 0.00025447 m2; BarLength: 4.26733 m; Material: Steel

# IfcReinforcingBarType, no part of this type: type
PredefinedType: MAIN; NominalDiameter: 0.016 m; CrossSectionArea: 0.00020106 m2; BarLength: 4.26733 m; Material: Steel

# IfcReinforcingBarType, no part of this type: type
PredefinedType: MAIN; NominalDiameter: 0.02 m; CrossSectionArea: 0.00031416 m2; BarLength: 4.58906 m; Material: Steel

# IfcReinforcingBarType, no part of this type: type
PredefinedType: MAIN; NominalDiameter: 0.016 m; CrossSectionArea: 0.00020106 m2; BarLength: 4.58906 m; Material: Steel

# IfcReinforcingBarType, no part of this type: type
PredefinedType: MAIN; NominalDiameter: 0.018 m; CrossSectionArea: 0.00025447 m2; BarLength: 4.59273 m; Material: Steel

# IfcReinforcingBarType, no part of this type: type
PredefinedType: MAIN; NominalDiameter: 0.016 m; CrossSectionArea: 0.00020106 m2; BarLength: 4.59273 m; Material: Steel

# IfcReinforcingBarType, no part of this type: type
PredefinedType: LIGATURE; NominalDiameter: 0.008 m; CrossSectionArea: 0.000050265 m2; BarLength: 1.57214 m; Material: Steel

# IfcReinforcingBarType, no part of this type: type
PredefinedType: MAIN; NominalDiameter: 0.018 m; CrossSectionArea: 0.00025447 m2; BarLength: 6.63307 m; Material: Steel

# IfcReinforcingBarType, no part of this type: type
PredefinedType: MAIN; NominalDiameter: 0.02 m; CrossSectionArea: 0.00031416 m2; BarLength: 8.69116 m; Material: Steel

# IfcReinforcingBarType, no part of this type: type
PredefinedType: MAIN; NominalDiameter: 0.018 m; CrossSectionArea: 0.00025447 m2; BarLength: 8.69116 m; Material: Steel

# IfcReinforcingBarType, no part of this type: type
PredefinedType: MAIN; NominalDiameter: 0.02 m; CrossSectionArea: 0.00031416 m2; BarLength: 8.69116 m; Material: Steel

# IfcReinforcingBarType, no part of this type: type
PredefinedType: MAIN; NominalDiameter: 0.016 m; CrossSectionArea: 0.00020106 m2; BarLength: 8.69116 m; Material: Steel

# IfcReinforcingBarType, no part of this type: type
PredefinedType: MAIN; NominalDiameter: 0.02 m; CrossSectionArea: 0.00031416 m2; BarLength: 4.59273 m; Material: Steel

# IfcReinforcingBarType, no part of this type: type
PredefinedType: MAIN; NominalDiameter: 0.016 m; CrossSectionArea: 0.00020106 m2; BarLength: 4.59273 m; Material: Steel

# IfcReinforcingBarType, no part of this type: type
PredefinedType: MAIN; NominalDiameter: 0.02 m; CrossSectionArea: 0.00031416 m2; BarLength: 4.58906 m; Material: Steel

# IfcReinforcingBarType, no part of this type: type
PredefinedType: MAIN; NominalDiameter: 0.018 m; CrossSectionArea: 0.00025447 m2; BarLength: 4.58906 m; Material: Steel

# IfcReinforcingBarType, no part of this type: type
PredefinedType: MAIN; NominalDiameter: 0.02 m; CrossSectionArea: 0.00031416 m2; BarLength: 4.59273 m; Material: Steel

# IfcReinforcingBarType, no part of this type: type
PredefinedType: MAIN; NominalDiameter: 0.016 m; CrossSectionArea: 0.00020106 m2; BarLength: 4.59273 m; Material: Steel

# IfcReinforcingBarType, no part of this type: type
PredefinedType: LIGATURE; NominalDiameter: 0.008 m; CrossSectionArea: 0.000050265 m2; BarLength: 1.5868 m; Material: Steel

# IfcReinforcingBarType, no part of this type: type
PredefinedType: MAIN; NominalDiameter: 0.02 m; CrossSectionArea: 0.00031416 m2; BarLength: 7.62227 m; Material: Steel

# IfcReinforcingBarType, no part of this type: type
PredefinedType: MAIN; NominalDiameter: 0.02 m; CrossSectionArea: 0.00031416 m2; BarLength: 7.62226 m; Material: Steel

# IfcReinforcingBarType, no part of this type: type
PredefinedType: MAIN; NominalDiameter: 0.02 m; CrossSectionArea: 0.00031416 m2; BarLength: 12.1783 m; Material: Steel

# IfcReinforcingBarType, no part of this type: type
PredefinedType: MAIN; NominalDiameter: 0.012 m; CrossSectionArea: 0.0001131 m2; BarLength: 6.36987 m; Material: Steel

# IfcReinforcingBarType, no part of this type: type
PredefinedType: MAIN; NominalDiameter: 0.012 m; CrossSectionArea: 0.0001131 m2; BarLength: 6.16672 m; Material: Steel

# IfcReinforcingBarType, no part of this type: type
PredefinedType: MAIN; NominalDiameter: 0.016 m; CrossSectionArea: 0.00020106 m2; BarLength: 3.58906 m; Material: Steel

# IfcReinforcingBarType, no part of this type: type
PredefinedType: MAIN; NominalDiameter: 0.016 m; CrossSectionArea: 0.00020106 m2; BarLength: 2.44898 m; Material: Steel

# IfcReinforcingBarType, no part of this type: type
PredefinedType: MAIN; NominalDiameter: 0.016 m; CrossSectionArea: 0.00020106 m2; BarLength: 3.58906 m; Material: Steel

# IfcReinforcingBarType, no part of this type: type
PredefinedType: LIGATURE; NominalDiameter: 0.01 m; CrossSectionArea: 0.00007854 m2; BarLength: 1.85514 m; Material: Steel

# IfcReinforcingBarType, no part of this type: type
PredefinedType: MAIN; NominalDiameter: 0.016 m; CrossSectionArea: 0.00020106 m2; BarLength: 11.7241 m; Material: Steel

# IfcReinforcingBarType, no part of this type: type
PredefinedType: MAIN; NominalDiameter: 0.016 m; CrossSectionArea: 0.00020106 m2; BarLength: 6.70876 m; Material: Steel

# IfcReinforcingBarType, no part of this type: type
PredefinedType: MAIN; NominalDiameter: 0.016 m; CrossSectionArea: 0.00020106 m2; BarLength: 6.79003 m; Material: Steel

# IfcReinforcingBarType, no part of this type: type
PredefinedType: MAIN; NominalDiameter: 0.012 m; CrossSectionArea: 0.0001131 m2; BarLength: 6.87621 m; Material: Steel

# IfcReinforcingBarType, no part of this type: type
PredefinedType: MAIN; NominalDiameter: 0.012 m; CrossSectionArea: 0.0001131 m2; BarLength: 6.65712 m; Material: Steel

# IfcReinforcingBarType, no part of this type: type
PredefinedType: MAIN; NominalDiameter: 0.012 m; CrossSectionArea: 0.0001131 m2; BarLength: 11.8103 m; Material: Steel

# IfcReinforcingBarType, no part of this type: type
PredefinedType: LIGATURE; NominalDiameter: 0.01 m; CrossSectionArea: 0.00007854 m2; BarLength: 1.85514 m; Material: Steel

# IfcReinforcingBarType, no part of this type: type
PredefinedType: MAIN; NominalDiameter: 0.016 m; CrossSectionArea: 0.00020106 m2; BarLength: 9.35121 m; Material: Steel

# IfcReinforcingBarType, no part of this type: type
PredefinedType: MAIN; NominalDiameter: 0.016 m; CrossSectionArea: 0.00020106 m2; BarLength: 7.30121 m; Material: Steel

# IfcReinforcingBarType, no part of this type: type
PredefinedType: MAIN; NominalDiameter: 0.016 m; CrossSectionArea: 0.00020106 m2; BarLength: 7.60121 m; Material: Steel

# IfcReinforcingBarType, no part of this type: type
PredefinedType: MAIN; NominalDiameter: 0.016 m; CrossSectionArea: 0.00020106 m2; BarLength: 2.81503 m; Material: Steel

# IfcReinforcingBarType, no part of this type: type
PredefinedType: MAIN; NominalDiameter: 0.016 m; CrossSectionArea: 0.00020106 m2; BarLength: 9.22121 m; Material: Steel

# IfcReinforcingBarType, no part of this type: type
PredefinedType: MAIN; NominalDiameter: 0.02 m; CrossSectionArea: 0.00031416 m2; BarLength: 7.15121 m; Material: Steel

# IfcReinforcingBarType, no part of this type: type
PredefinedType: MAIN; NominalDiameter: 0.016 m; CrossSectionArea: 0.00020106 m2; BarLength: 7.15121 m; Material: Steel

# IfcReinforcingBarType, no part of this type: type
PredefinedType: MAIN; NominalDiameter: 0.016 m; CrossSectionArea: 0.00020106 m2; BarLength: 9.48122 m; Material: Steel

# IfcReinforcingBarType, no part of this type: type
PredefinedType: MAIN; NominalDiameter: 0.012 m; CrossSectionArea: 0.0001131 m2; BarLength: 3.66121 m; Material: Steel

# IfcReinforcingBarType, no part of this type: type
PredefinedType: MAIN; NominalDiameter: 0.012 m; CrossSectionArea: 0.0001131 m2; BarLength: 4.84121 m; Material: Steel

# IfcReinforcingBarType, no part of this type: type
PredefinedType: MAIN; NominalDiameter: 0.012 m; CrossSectionArea: 0.0001131 m2; BarLength: 6.92621 m; Material: Steel

# IfcReinforcingBarType, no part of this type: type
PredefinedType: MAIN; NominalDiameter: 0.012 m; CrossSectionArea: 0.0001131 m2; BarLength: 6.6603 m; Material: Steel

# IfcReinforcingBarType, no part of this type: type
PredefinedType: MAIN; NominalDiameter: 0.012 m; CrossSectionArea: 0.0001131 m2; BarLength: 3.99121 m; Material: Steel

# IfcReinforcingBarType, no part of this type: type
PredefinedType: LIGATURE; NominalDiameter: 0.01 m; CrossSectionArea: 0.00007854 m2; BarLength: 1.85514 m; Material: Steel

# IfcReinforcingBarType, no part of this type: type
PredefinedType: MAIN; NominalDiameter: 0.016 m; CrossSectionArea: 0.00020106 m2; BarLength: 10.1312 m; Material: Steel

# IfcReinforcingBarType, no part of this type: type
PredefinedType: MAIN; NominalDiameter: 0.016 m; CrossSectionArea: 0.00020106 m2; BarLength: 6.97121 m; Material: Steel

# IfcReinforcingBarType, no part of this type: type
PredefinedType: MAIN; NominalDiameter: 0.016 m; CrossSectionArea: 0.00020106 m2; BarLength: 7.71121 m; Material: Steel

# IfcReinforcingBarType, no part of this type: type
PredefinedType: MAIN; NominalDiameter: 0.016 m; CrossSectionArea: 0.00020106 m2; BarLength: 2.81503 m; Material: Steel

# IfcReinforcingBarType, no part of this type: type
PredefinedType: MAIN; NominalDiameter: 0.016 m; CrossSectionArea: 0.00020106 m2; BarLength: 9.97121 m; Material: Steel

# IfcReinforcingBarType, no part of this type: type
PredefinedType: MAIN; NominalDiameter: 0.016 m; CrossSectionArea: 0.00020106 m2; BarLength: 6.81831 m; Material: Steel

# IfcReinforcingBarType, no part of this type: type
PredefinedType: MAIN; NominalDiameter: 0.016 m; CrossSectionArea: 0.00020106 m2; BarLength: 9.50121 m; Material: Steel

# IfcReinforcingBarType, no part of this type: type
PredefinedType: MAIN; NominalDiameter: 0.012 m; CrossSectionArea: 0.0001131 m2; BarLength: 3.26121 m; Material: Steel

# IfcReinforcingBarType, no part of this type: type
PredefinedType: MAIN; NominalDiameter: 0.012 m; CrossSectionArea: 0.0001131 m2; BarLength: 4.90121 m; Material: Steel

# IfcReinforcingBarType, no part of this type: type
PredefinedType: MAIN; NominalDiameter: 0.012 m; CrossSectionArea: 0.0001131 m2; BarLength: 7.35122 m; Material: Steel

# IfcReinforcingBarType, no part of this type: type
PredefinedType: MAIN; NominalDiameter: 0.012 m; CrossSectionArea: 0.0001131 m2; BarLength: 6.6603 m; Material: Steel

# IfcReinforcingBarType, no part of this type: type
PredefinedType: MAIN; NominalDiameter: 0.012 m; CrossSectionArea: 0.0001131 m2; BarLength: 4.49121 m; Material: Steel

# IfcReinforcingBarType, no part of this type: type
PredefinedType: LIGATURE; NominalDiameter: 0.01 m; CrossSectionArea: 0.00007854 m2; BarLength: 1.85515 m; Material: Steel

# IfcReinforcingBarType, no part of this type: type
PredefinedType: MAIN; NominalDiameter: 0.016 m; CrossSectionArea: 0.00020106 m2; BarLength: 7.97121 m; Material: Steel

# IfcReinforcingBarType, no part of this type: type
PredefinedType: MAIN; NominalDiameter: 0.016 m; CrossSectionArea: 0.00020106 m2; BarLength: 8.82121 m; Material: Steel

# IfcReinforcingBarType, no part of this type: type
PredefinedType: MAIN; NominalDiameter: 0.016 m; CrossSectionArea: 0.00020106 m2; BarLength: 7.82121 m; Material: Steel

# IfcReinforcingBarType, no part of this type: type
PredefinedType: MAIN; NominalDiameter: 0.016 m; CrossSectionArea: 0.00020106 m2; BarLength: 2.81503 m; Material: Steel

# IfcReinforcingBarType, no part of this type: type
PredefinedType: MAIN; NominalDiameter: 0.016 m; CrossSectionArea: 0.00020106 m2; BarLength: 7.50121 m; Material: Steel

# IfcReinforcingBarType, no part of this type: type
PredefinedType: MAIN; NominalDiameter: 0.016 m; CrossSectionArea: 0.00020106 m2; BarLength: 9.61122 m; Material: Steel

# IfcReinforcingBarType, no part of this type: type
PredefinedType: MAIN; NominalDiameter: 0.016 m; CrossSectionArea: 0.00020106 m2; BarLength: 8.86121 m; Material: Steel

# IfcReinforcingBarType, no part of this type: type
PredefinedType: MAIN; NominalDiameter: 0.012 m; CrossSectionArea: 0.0001131 m2; BarLength: 3.99121 m; Material: Steel

# IfcReinforcingBarType, no part of this type: type
PredefinedType: MAIN; NominalDiameter: 0.012 m; CrossSectionArea: 0.0001131 m2; BarLength: 3.66121 m; Material: Steel

# IfcReinforcingBarType, no part of this type: type
PredefinedType: MAIN; NominalDiameter: 0.012 m; CrossSectionArea: 0.0001131 m2; BarLength: 4.44121 m; Material: Steel

# IfcReinforcingBarType, no part of this type: type
PredefinedType: MAIN; NominalDiameter: 0.012 m; CrossSectionArea: 0.0001131 m2; BarLength: 7.35121 m; Material: Steel

# IfcReinforcingBarType, no part of this type: type
PredefinedType: MAIN; NominalDiameter: 0.012 m; CrossSectionArea: 0.0001131 m2; BarLength: 6.6603 m; Material: Steel

# IfcReinforcingBarType, no part of this type: type
PredefinedType: LIGATURE; NominalDiameter: 0.01 m; CrossSectionArea: 0.00007854 m2; BarLength: 1.85514 m; Material: Steel

# IfcReinforcingBarType, no part of this type: type
PredefinedType: MAIN; NominalDiameter: 0.016 m; CrossSectionArea: 0.00020106 m2; BarLength: 11.7241 m; Material: Steel

# IfcReinforcingBarType, no part of this type: type
PredefinedType: MAIN; NominalDiameter: 0.016 m; CrossSectionArea: 0.00020106 m2; BarLength: 6.70876 m; Material: Steel

# IfcReinforcingBarType, no part of this type: type
PredefinedType: MAIN; NominalDiameter: 0.016 m; CrossSectionArea: 0.00020106 m2; BarLength: 6.79003 m; Material: Steel

# IfcReinforcingBarType, no part of this type: type
PredefinedType: MAIN; NominalDiameter: 0.012 m; CrossSectionArea: 0.0001131 m2; BarLength: 6.87621 m; Material: Steel

# IfcReinforcingBarType, no part of this type: type
PredefinedType: MAIN; NominalDiameter: 0.012 m; CrossSectionArea: 0.0001131 m2; BarLength: 6.65712 m; Material: Steel

# IfcReinforcingBarType, no part of this type: type
PredefinedType: MAIN; NominalDiameter: 0.012 m; CrossSectionArea: 0.0001131 m2; BarLength: 11.8103 m; Material: Steel

# IfcReinforcingBarType, no part of this type: type
PredefinedType: LIGATURE; NominalDiameter: 0.01 m; CrossSectionArea: 0.00007854 m2; BarLength: 1.85514 m; Material: Steel

# IfcReinforcingBarType, no part of this type: type
PredefinedType: MAIN; NominalDiameter: 0.016 m; CrossSectionArea: 0.00020106 m2; BarLength: 10.0912 m; Material: Steel

# IfcReinforcingBarType, no part of this type: type
PredefinedType: MAIN; NominalDiameter: 0.016 m; CrossSectionArea: 0.00020106 m2; BarLength: 4.57285 m; Material: Steel

# IfcReinforcingBarType, no part of this type: type
PredefinedType: MAIN; NominalDiameter: 0.02 m; CrossSectionArea: 0.00031416 m2; BarLength: 4.94649 m; Material: Steel

# IfcReinforcingBarType, no part of this type: type
PredefinedType: MAIN; NominalDiameter: 0.018 m; CrossSectionArea: 0.00025447 m2; BarLength: 2.19121 m; Material: Steel

# IfcReinforcingBarType, no part of this type: type
PredefinedType: MAIN; NominalDiameter: 0.016 m; CrossSectionArea: 0.00020106 m2; BarLength: 2.19121 m; Material: Steel

# IfcReinforcingBarType, no part of this type: type
PredefinedType: MAIN; NominalDiameter: 0.018 m; CrossSectionArea: 0.00025447 m2; BarLength: 8.41076 m; Material: Steel

# IfcReinforcingBarType, no part of this type: type
PredefinedType: MAIN; NominalDiameter: 0.012 m; CrossSectionArea: 0.0001131 m2; BarLength: 4.90121 m; Material: Steel

# IfcReinforcingBarType, no part of this type: type
PredefinedType: MAIN; NominalDiameter: 0.012 m; CrossSectionArea: 0.0001131 m2; BarLength: 4.52121 m; Material: Steel

# IfcReinforcingBarType, no part of this type: type
PredefinedType: MAIN; NominalDiameter: 0.012 m; CrossSectionArea: 0.0001131 m2; BarLength: 9.03121 m; Material: Steel

# IfcReinforcingBarType, no part of this type: type
PredefinedType: LIGATURE; NominalDiameter: 0.01 m; CrossSectionArea: 0.00007854 m2; BarLength: 1.85514 m; Material: Steel

# IfcReinforcingBarType, no part of this type: type
PredefinedType: MAIN; NominalDiameter: 0.016 m; CrossSectionArea: 0.00020106 m2; BarLength: 9.09121 m; Material: Steel

# IfcReinforcingBarType, no part of this type: type
PredefinedType: MAIN; NominalDiameter: 0.016 m; CrossSectionArea: 0.00020106 m2; BarLength: 8.64503 m; Material: Steel

# IfcReinforcingBarType, no part of this type: type
PredefinedType: MAIN; NominalDiameter: 0.016 m; CrossSectionArea: 0.00020106 m2; BarLength: 8.59121 m; Material: Steel

# IfcReinforcingBarType, no part of this type: type
PredefinedType: MAIN; NominalDiameter: 0.016 m; CrossSectionArea: 0.00020106 m2; BarLength: 8.59121 m; Material: Steel

# IfcReinforcingBarType, no part of this type: type
PredefinedType: MAIN; NominalDiameter: 0.02 m; CrossSectionArea: 0.00031416 m2; BarLength: 2.19121 m; Material: Steel

# IfcReinforcingBarType, no part of this type: type
PredefinedType: MAIN; NominalDiameter: 0.016 m; CrossSectionArea: 0.00020106 m2; BarLength: 2.19121 m; Material: Steel

# IfcReinforcingBarType, no part of this type: type
PredefinedType: MAIN; NominalDiameter: 0.012 m; CrossSectionArea: 0.0001131 m2; BarLength: 3.66121 m; Material: Steel

# IfcReinforcingBarType, no part of this type: type
PredefinedType: MAIN; NominalDiameter: 0.012 m; CrossSectionArea: 0.0001131 m2; BarLength: 6.02121 m; Material: Steel

# IfcReinforcingBarType, no part of this type: type
PredefinedType: MAIN; NominalDiameter: 0.012 m; CrossSectionArea: 0.0001131 m2; BarLength: 5.92336 m; Material: Steel

# IfcReinforcingBarType, no part of this type: type
PredefinedType: LIGATURE; NominalDiameter: 0.01 m; CrossSectionArea: 0.00007854 m2; BarLength: 1.85514 m; Material: Steel

# IfcReinforcingBarType, no part of this type: type
PredefinedType: MAIN; NominalDiameter: 0.016 m; CrossSectionArea: 0.00020106 m2; BarLength: 9.83121 m; Material: Steel

# IfcReinforcingBarType, no part of this type: type
PredefinedType: MAIN; NominalDiameter: 0.016 m; CrossSectionArea: 0.00020106 m2; BarLength: 9.65121 m; Material: Steel

# IfcReinforcingBarType, no part of this type: type
PredefinedType: MAIN; NominalDiameter: 0.016 m; CrossSectionArea: 0.00020106 m2; BarLength: 9.63121 m; Material: Steel

# IfcReinforcingBarType, no part of this type: type
PredefinedType: MAIN; NominalDiameter: 0.016 m; CrossSectionArea: 0.00020106 m2; BarLength: 9.68121 m; Material: Steel

# IfcReinforcingBarType, no part of this type: type
PredefinedType: MAIN; NominalDiameter: 0.012 m; CrossSectionArea: 0.0001131 m2; BarLength: 5.92336 m; Material: Steel

# IfcReinforcingBarType, no part of this type: type
PredefinedType: MAIN; NominalDiameter: 0.012 m; CrossSectionArea: 0.0001131 m2; BarLength: 3.66121 m; Material: Steel

# IfcReinforcingBarType, no part of this type: type
PredefinedType: MAIN; NominalDiameter: 0.012 m; CrossSectionArea: 0.0001131 m2; BarLength: 3.26121 m; Material: Steel

# IfcReinforcingBarType, no part of this type: type
PredefinedType: MAIN; NominalDiameter: 0.012 m; CrossSectionArea: 0.0001131 m2; BarLength: 6.52121 m; Material: Steel

# IfcReinforcingBarType, no part of this type: type
PredefinedType: LIGATURE; NominalDiameter: 0.01 m; CrossSectionArea: 0.00007854 m2; BarLength: 1.85514 m; Material: Steel

# IfcReinforcingBarType, no part of this type: type
PredefinedType: MAIN; NominalDiameter: 0.016 m; CrossSectionArea: 0.00020106 m2; BarLength: 9.86121 m; Material: Steel

# IfcReinforcingBarType, no part of this type: type
PredefinedType: MAIN; NominalDiameter: 0.016 m; CrossSectionArea: 0.00020106 m2; BarLength: 9.59121 m; Material: Steel

# IfcReinforcingBarType, no part of this type: type
PredefinedType: MAIN; NominalDiameter: 0.016 m; CrossSectionArea: 0.00020106 m2; BarLength: 9.73121 m; Material: Steel

# IfcReinforcingBarType, no part of this type: type
PredefinedType: MAIN; NominalDiameter: 0.016 m; CrossSectionArea: 0.00020106 m2; BarLength: 9.61121 m; Material: Steel

# IfcReinforcingBarType, no part of this type: type
PredefinedType: MAIN; NominalDiameter: 0.012 m; CrossSectionArea: 0.0001131 m2; BarLength: 6.98121 m; Material: Steel

# IfcReinforcingBarType, no part of this type: type
PredefinedType: MAIN; NominalDiameter: 0.012 m; CrossSectionArea: 0.0001131 m2; BarLength: 3.26121 m; Material: Steel

# IfcReinforcingBarType, no part of this type: type
PredefinedType: LIGATURE; NominalDiameter: 0.01 m; CrossSectionArea: 0.00007854 m2; BarLength: 1.85515 m; Material: Steel

# IfcReinforcingBarType, no part of this type: type
PredefinedType: MAIN; NominalDiameter: 0.016 m; CrossSectionArea: 0.00020106 m2; BarLength: 9.59121 m; Material: Steel

# IfcReinforcingBarType, no part of this type: type
PredefinedType: MAIN; NominalDiameter: 0.016 m; CrossSectionArea: 0.00020106 m2; BarLength: 9.34121 m; Material: Steel

# IfcReinforcingBarType, no part of this type: type
PredefinedType: MAIN; NominalDiameter: 0.016 m; CrossSectionArea: 0.00020106 m2; BarLength: 9.56121 m; Material: Steel

# IfcReinforcingBarType, no part of this type: type
PredefinedType: MAIN; NominalDiameter: 0.016 m; CrossSectionArea: 0.00020106 m2; BarLength: 9.13121 m; Material: Steel

# IfcReinforcingBarType, no part of this type: type
PredefinedType: MAIN; NominalDiameter: 0.012 m; CrossSectionArea: 0.0001131 m2; BarLength: 6.98121 m; Material: Steel

# IfcReinforcingBarType, no part of this type: type
PredefinedType: MAIN; NominalDiameter: 0.012 m; CrossSectionArea: 0.0001131 m2; BarLength: 3.26121 m; Material: Steel

# IfcReinforcingBarType, no part of this type: type
PredefinedType: LIGATURE; NominalDiameter: 0.01 m; CrossSectionArea: 0.00007854 m2; BarLength: 1.85515 m; Material: Steel

# IfcReinforcingBarType, no part of this type: type
PredefinedType: MAIN; NominalDiameter: 0.016 m; CrossSectionArea: 0.00020106 m2; BarLength: 9.09121 m; Material: Steel

# IfcReinforcingBarType, no part of this type: type
PredefinedType: MAIN; NominalDiameter: 0.016 m; CrossSectionArea: 0.00020106 m2; BarLength: 8.64503 m; Material: Steel

# IfcReinforcingBarType, no part of this type: type
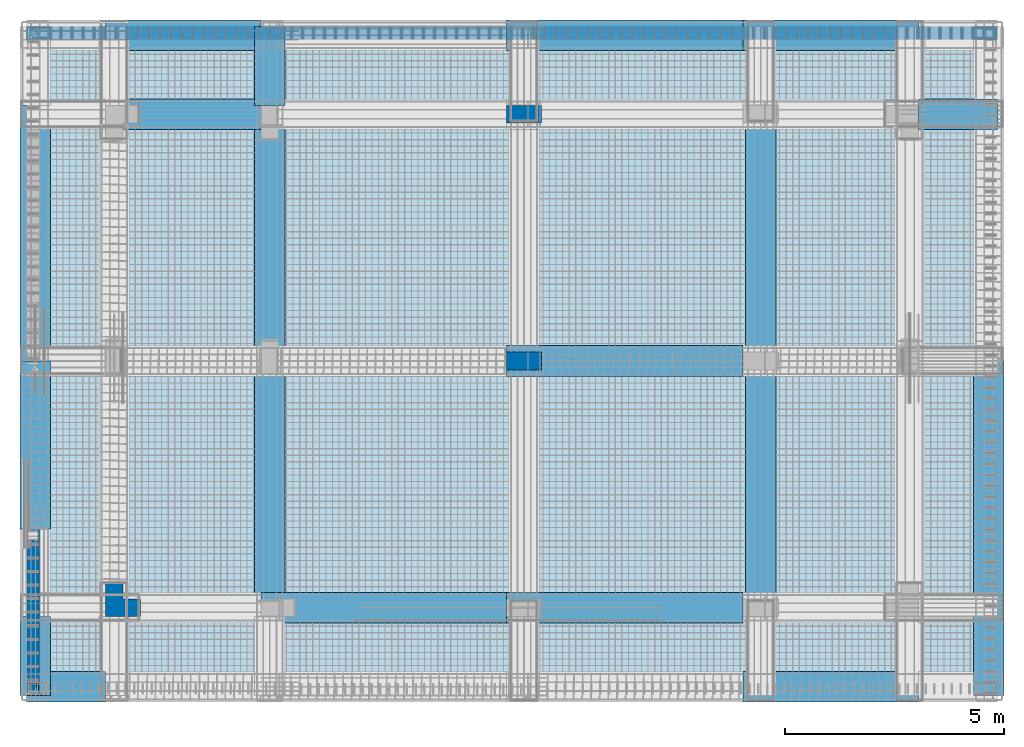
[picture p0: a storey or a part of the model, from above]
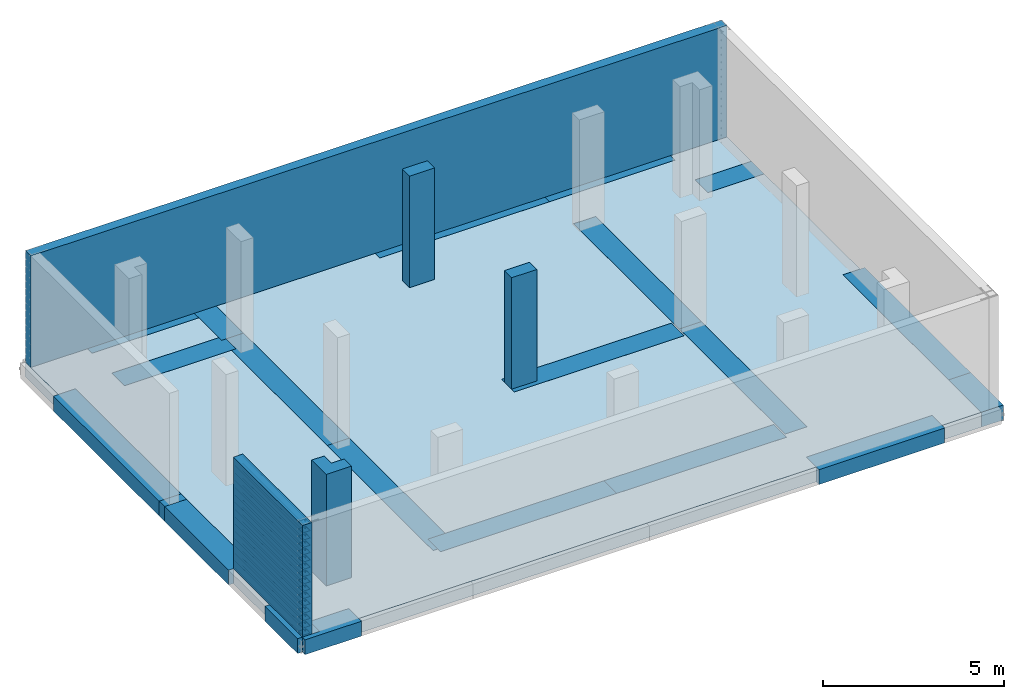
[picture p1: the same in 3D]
Properties of the parts of a building model (IFC4), part 3 of 3

# IfcReinforcingBarType, no part of this type: type
PredefinedType: MAIN; NominalDiameter: 0.016 m; CrossSectionArea: 0.00020106 m2; BarLength: 8.59121 m; Material: Steel

# IfcReinforcingBarType, no part of this type: type
PredefinedType: MAIN; NominalDiameter: 0.016 m; CrossSectionArea: 0.00020106 m2; BarLength: 8.59121 m; Material: Steel

# IfcReinforcingBarType, no part of this type: type
PredefinedType: MAIN; NominalDiameter: 0.02 m; CrossSectionArea: 0.00031416 m2; BarLength: 2.19121 m; Material: Steel

# IfcReinforcingBarType, no part of this type: type
PredefinedType: MAIN; NominalDiameter: 0.016 m; CrossSectionArea: 0.00020106 m2; BarLength: 2.19121 m; Material: Steel

# IfcReinforcingBarType, no part of this type: type
PredefinedType: MAIN; NominalDiameter: 0.012 m; CrossSectionArea: 0.0001131 m2; BarLength: 3.66122 m; Material: Steel

# IfcReinforcingBarType, no part of this type: type
PredefinedType: MAIN; NominalDiameter: 0.012 m; CrossSectionArea: 0.0001131 m2; BarLength: 6.02121 m; Material: Steel

# IfcReinforcingBarType, no part of this type: type
PredefinedType: MAIN; NominalDiameter: 0.012 m; CrossSectionArea: 0.0001131 m2; BarLength: 5.92336 m; Material: Steel

# IfcReinforcingBarType, no part of this type: type
PredefinedType: LIGATURE; NominalDiameter: 0.01 m; CrossSectionArea: 0.00007854 m2; BarLength: 1.85515 m; Material: Steel

# IfcReinforcingBarType, no part of this type: type
PredefinedType: MAIN; NominalDiameter: 0.016 m; CrossSectionArea: 0.00020106 m2; BarLength: 8.64503 m; Material: Steel

# IfcReinforcingBarType, no part of this type: type
PredefinedType: MAIN; NominalDiameter: 0.016 m; CrossSectionArea: 0.00020106 m2; BarLength: 8.64503 m; Material: Steel

# IfcReinforcingBarType, no part of this type: type
PredefinedType: MAIN; NominalDiameter: 0.012 m; CrossSectionArea: 0.0001131 m2; BarLength: 8.73122 m; Material: Steel

# Material: Calcestruzzo classe C28/35
Calcestruzzo classe C28/35 - Mass Density: 2500; Poisson Ratio: 0.1; Shear Modulus: 1481280000; Thermal Expansion Coefficient: 0.00001; Young Modulus: 3258810112

# Material: Calcestruzzo classe C28/35
Calcestruzzo classe C28/35 - Mass Density: 2500; Poisson Ratio: 0.1; Shear Modulus: 1481280000; Thermal Expansion Coefficient: 0.00001; Young Modulus: 3258810112

# Material: Calcestruzzo classe C28/35
Calcestruzzo classe C28/35 - Mass Density: 2500; Poisson Ratio: 0.1; Shear Modulus: 1481280000; Thermal Expansion Coefficient: 0.00001; Young Modulus: 3258810112

# Material: Calcestruzzo classe C28/35
Calcestruzzo classe C28/35 - Mass Density: 2500; Poisson Ratio: 0.1; Shear Modulus: 1481280000; Thermal Expansion Coefficient: 0.00001; Young Modulus: 3258810112

# Material: Calcestruzzo classe C28/35
Calcestruzzo classe C28/35 - Mass Density: 2500; Poisson Ratio: 0.1; Shear Modulus: 1481280000; Thermal Expansion Coefficient: 0.00001; Young Modulus: 3258810112

# Material: Calcestruzzo classe C28/35
Calcestruzzo classe C28/35 - Mass Density: 2500; Poisson Ratio: 0.1; Shear Modulus: 1481280000; Thermal Expansion Coefficient: 0.00001; Young Modulus: 3258810112

# Material: Calcestruzzo classe C28/35
Calcestruzzo classe C28/35 - Mass Density: 2500; Poisson Ratio: 0.1; Shear Modulus: 1481280000; Thermal Expansion Coefficient: 0.00001; Young Modulus: 3258810112

# Material: Calcestruzzo classe C28/35
Calcestruzzo classe C28/35 - Mass Density: 2500; Poisson Ratio: 0.1; Shear Modulus: 1481280000; Thermal Expansion Coefficient: 0.00001; Young Modulus: 3258810112

# Material: Calcestruzzo classe C28/35
Calcestruzzo classe C28/35 - Mass Density: 2500; Poisson Ratio: 0.1; Shear Modulus: 1481280000; Thermal Expansion Coefficient: 0.00001; Young Modulus: 3258810112

# Material: Calcestruzzo classe C28/35
Calcestruzzo classe C28/35 - Mass Density: 2500; Poisson Ratio: 0.1; Shear Modulus: 1481280000; Thermal Expansion Coefficient: 0.00001; Young Modulus: 3258810112

# Material: Calcestruzzo classe C28/35
Calcestruzzo classe C28/35 - Mass Density: 2500; Poisson Ratio: 0.1; Shear Modulus: 1481280000; Thermal Expansion Coefficient: 0.00001; Young Modulus: 3258810112

# Material: Calcestruzzo classe C28/35
Calcestruzzo classe C28/35 - Mass Density: 2500; Poisson Ratio: 0.1; Shear Modulus: 1481280000; Thermal Expansion Coefficient: 0.00001; Young Modulus: 3258810112

# Material: Calcestruzzo classe C28/35
Calcestruzzo classe C28/35 - Mass Density: 2500; Poisson Ratio: 0.1; Shear Modulus: 1481280000; Thermal Expansion Coefficient: 0.00001; Young Modulus: 3258810112

# Material: Calcestruzzo classe C28/35
Calcestruzzo classe C28/35 - Mass Density: 2500; Poisson Ratio: 0.1; Shear Modulus: 1481280000; Thermal Expansion Coefficient: 0.00001; Young Modulus: 3258810112

# Material: Calcestruzzo classe C28/35
Calcestruzzo classe C28/35 - Mass Density: 2500; Poisson Ratio: 0.1; Shear Modulus: 1481280000; Thermal Expansion Coefficient: 0.00001; Young Modulus: 3258810112

# Material: Calcestruzzo classe C28/35
Calcestruzzo classe C28/35 - Mass Density: 2500; Poisson Ratio: 0.1; Shear Modulus: 1481280000; Thermal Expansion Coefficient: 0.00001; Young Modulus: 3258810112

# Material: Calcestruzzo classe C28/35
Calcestruzzo classe C28/35 - Mass Density: 2500; Poisson Ratio: 0.1; Shear Modulus: 1481280000; Thermal Expansion Coefficient: 0.00001; Young Modulus: 3258810112

# Material: Calcestruzzo classe C28/35
Calcestruzzo classe C28/35 - Mass Density: 2500; Poisson Ratio: 0.1; Shear Modulus: 1481280000; Thermal Expansion Coefficient: 0.00001; Young Modulus: 3258810112

# Material: Calcestruzzo classe C28/35
Calcestruzzo classe C28/35 - Mass Density: 2500; Poisson Ratio: 0.1; Shear Modulus: 1481280000; Thermal Expansion Coefficient: 0.00001; Young Modulus: 3258810112

# Material: Calcestruzzo classe C28/35
Calcestruzzo classe C28/35 - Mass Density: 2500; Poisson Ratio: 0.1; Shear Modulus: 1481280000; Thermal Expansion Coefficient: 0.00001; Young Modulus: 3258810112

# Material: Calcestruzzo classe C28/35
Calcestruzzo classe C28/35 - Mass Density: 2500; Poisson Ratio: 0.1; Shear Modulus: 1481280000; Thermal Expansion Coefficient: 0.00001; Young Modulus: 3258810112

# Material: Calcestruzzo classe C28/35
Calcestruzzo classe C28/35 - Mass Density: 2500; Poisson Ratio: 0.1; Shear Modulus: 1481280000; Thermal Expansion Coefficient: 0.00001; Young Modulus: 3258810112

# Material: Calcestruzzo classe C28/35
Calcestruzzo classe C28/35 - Mass Density: 2500; Poisson Ratio: 0.1; Shear Modulus: 1481280000; Thermal Expansion Coefficient: 0.00001; Young Modulus: 3258810112

# Material: Calcestruzzo classe C28/35
Calcestruzzo classe C28/35 - Mass Density: 2500; Poisson Ratio: 0.1; Shear Modulus: 1481280000; Thermal Expansion Coefficient: 0.00001; Young Modulus: 3258810112

# Material: Calcestruzzo classe C28/35
Calcestruzzo classe C28/35 - Mass Density: 2500; Poisson Ratio: 0.1; Shear Modulus: 1481280000; Thermal Expansion Coefficient: 0.00001; Young Modulus: 3258810112

# Material: Calcestruzzo classe C28/35
Calcestruzzo classe C28/35 - Mass Density: 2500; Poisson Ratio: 0.1; Shear Modulus: 1481280000; Thermal Expansion Coefficient: 0.00001; Young Modulus: 3258810112

# Material: Calcestruzzo classe C28/35
Calcestruzzo classe C28/35 - Mass Density: 2500; Poisson Ratio: 0.1; Shear Modulus: 1481280000; Thermal Expansion Coefficient: 0.00001; Young Modulus: 3258810112

# Material: Calcestruzzo classe C28/35
Calcestruzzo classe C28/35 - Mass Density: 2500; Poisson Ratio: 0.1; Shear Modulus: 1481280000; Thermal Expansion Coefficient: 0.00001; Young Modulus: 3258810112

# Material: Calcestruzzo classe C28/35
Calcestruzzo classe C28/35 - Mass Density: 2500; Poisson Ratio: 0.1; Shear Modulus: 1481280000; Thermal Expansion Coefficient: 0.00001; Young Modulus: 3258810112

# Material: Calcestruzzo classe C28/35
Calcestruzzo classe C28/35 - Mass Density: 2500; Poisson Ratio: 0.1; Shear Modulus: 1481280000; Thermal Expansion Coefficient: 0.00001; Young Modulus: 3258810112

# Material: Calcestruzzo classe C28/35
Calcestruzzo classe C28/35 - Mass Density: 2500; Poisson Ratio: 0.1; Shear Modulus: 1481280000; Thermal Expansion Coefficient: 0.00001; Young Modulus: 3258810112

# Material: Calcestruzzo classe C28/35
Calcestruzzo classe C28/35 - Mass Density: 2500; Poisson Ratio: 0.1; Shear Modulus: 1481280000; Thermal Expansion Coefficient: 0.00001; Young Modulus: 3258810112

# Material: Calcestruzzo classe C28/35
Calcestruzzo classe C28/35 - Mass Density: 2500; Poisson Ratio: 0.1; Shear Modulus: 1481280000; Thermal Expansion Coefficient: 0.00001; Young Modulus: 3258810112

# Material: Calcestruzzo classe C28/35
Calcestruzzo classe C28/35 - Mass Density: 2500; Poisson Ratio: 0.1; Shear Modulus: 1481280000; Thermal Expansion Coefficient: 0.00001; Young Modulus: 3258810112

# Material: Calcestruzzo classe C28/35
Calcestruzzo classe C28/35 - Mass Density: 2500; Poisson Ratio: 0.1; Shear Modulus: 1481280000; Thermal Expansion Coefficient: 0.00001; Young Modulus: 3258810112

# Material: Calcestruzzo classe C28/35
Calcestruzzo classe C28/35 - Mass Density: 2500; Poisson Ratio: 0.1; Shear Modulus: 1481280000; Thermal Expansion Coefficient: 0.00001; Young Modulus: 3258810112

# Material: Calcestruzzo classe C28/35
Calcestruzzo classe C28/35 - Mass Density: 2500; Poisson Ratio: 0.1; Shear Modulus: 1481280000; Thermal Expansion Coefficient: 0.00001; Young Modulus: 3258810112

# Material: Calcestruzzo classe C28/35
Calcestruzzo classe C28/35 - Mass Density: 2500; Poisson Ratio: 0.1; Shear Modulus: 1481280000; Thermal Expansion Coefficient: 0.00001; Young Modulus: 3258810112

# Material: Calcestruzzo classe C28/35
Calcestruzzo classe C28/35 - Mass Density: 2500; Poisson Ratio: 0.1; Shear Modulus: 1481280000; Thermal Expansion Coefficient: 0.00001; Young Modulus: 3258810112

# Material: Calcestruzzo classe C28/35
Calcestruzzo classe C28/35 - Mass Density: 2500; Poisson Ratio: 0.1; Shear Modulus: 1481280000; Thermal Expansion Coefficient: 0.00001; Young Modulus: 3258810112

# Material: Calcestruzzo classe C28/35
Calcestruzzo classe C28/35 - Mass Density: 2500; Poisson Ratio: 0.1; Shear Modulus: 1481280000; Thermal Expansion Coefficient: 0.00001; Young Modulus: 3258810112

# Material: Calcestruzzo classe C28/35
Calcestruzzo classe C28/35 - Mass Density: 2500; Poisson Ratio: 0.1; Shear Modulus: 1481280000; Thermal Expansion Coefficient: 0.00001; Young Modulus: 3258810112

# Material: Calcestruzzo classe C28/35
Calcestruzzo classe C28/35 - Mass Density: 2500; Poisson Ratio: 0.1; Shear Modulus: 1481280000; Thermal Expansion Coefficient: 0.00001; Young Modulus: 3258810112

# Material: Calcestruzzo classe C28/35
Calcestruzzo classe C28/35 - Mass Density: 2500; Poisson Ratio: 0.1; Shear Modulus: 1481280000; Thermal Expansion Coefficient: 0.00001; Young Modulus: 3258810112

# Material: Calcestruzzo classe C28/35
Calcestruzzo classe C28/35 - Mass Density: 2500; Poisson Ratio: 0.1; Shear Modulus: 1481280000; Thermal Expansion Coefficient: 0.00001; Young Modulus: 3258810112

# Material: Calcestruzzo classe C28/35
Calcestruzzo classe C28/35 - Mass Density: 2500; Poisson Ratio: 0.1; Shear Modulus: 1481280000; Thermal Expansion Coefficient: 0.00001; Young Modulus: 3258810112

# Material: Calcestruzzo classe C28/35
Calcestruzzo classe C28/35 - Mass Density: 2500; Poisson Ratio: 0.1; Shear Modulus: 1481280000; Thermal Expansion Coefficient: 0.00001; Young Modulus: 3258810112

# Material: Calcestruzzo classe C28/35
Calcestruzzo classe C28/35 - Mass Density: 2500; Poisson Ratio: 0.1; Shear Modulus: 1481280000; Thermal Expansion Coefficient: 0.00001; Young Modulus: 3258810112

# Material: Calcestruzzo classe C28/35
Calcestruzzo classe C28/35 - Mass Density: 2500; Poisson Ratio: 0.1; Shear Modulus: 1481280000; Thermal Expansion Coefficient: 0.00001; Young Modulus: 3258810112

# Material: Calcestruzzo classe C28/35
Calcestruzzo classe C28/35 - Mass Density: 2500; Poisson Ratio: 0.1; Shear Modulus: 1481280000; Thermal Expansion Coefficient: 0.00001; Young Modulus: 3258810112

# Material: Calcestruzzo classe C28/35
Calcestruzzo classe C28/35 - Mass Density: 2500; Poisson Ratio: 0.1; Shear Modulus: 1481280000; Thermal Expansion Coefficient: 0.00001; Young Modulus: 3258810112

# Material: Calcestruzzo classe C28/35
Calcestruzzo classe C28/35 - Mass Density: 2500; Poisson Ratio: 0.1; Shear Modulus: 1481280000; Thermal Expansion Coefficient: 0.00001; Young Modulus: 3258810112

# Material: Calcestruzzo classe C28/35
Calcestruzzo classe C28/35 - Mass Density: 2500; Poisson Ratio: 0.1; Shear Modulus: 1481280000; Thermal Expansion Coefficient: 0.00001; Young Modulus: 3258810112

# Material: Calcestruzzo classe C28/35
Calcestruzzo classe C28/35 - Mass Density: 2500; Poisson Ratio: 0.1; Shear Modulus: 1481280000; Thermal Expansion Coefficient: 0.00001; Young Modulus: 3258810112

# Material: Calcestruzzo classe C28/35
Calcestruzzo classe C28/35 - Mass Density: 2500; Poisson Ratio: 0.1; Shear Modulus: 1481280000; Thermal Expansion Coefficient: 0.00001; Young Modulus: 3258810112

# Material: Calcestruzzo classe C28/35
Calcestruzzo classe C28/35 - Mass Density: 2500; Poisson Ratio: 0.1; Shear Modulus: 1481280000; Thermal Expansion Coefficient: 0.00001; Young Modulus: 3258810112

# Material: Calcestruzzo classe C28/35
Calcestruzzo classe C28/35 - Mass Density: 2500; Poisson Ratio: 0.1; Shear Modulus: 1481280000; Thermal Expansion Coefficient: 0.00001; Young Modulus: 3258810112

# Material: Calcestruzzo classe C28/35
Calcestruzzo classe C28/35 - Mass Density: 2500; Poisson Ratio: 0.1; Shear Modulus: 1481280000; Thermal Expansion Coefficient: 0.00001; Young Modulus: 3258810112

# Material: Calcestruzzo classe C28/35
Calcestruzzo classe C28/35 - Mass Density: 2500; Poisson Ratio: 0.1; Shear Modulus: 1481280000; Thermal Expansion Coefficient: 0.00001; Young Modulus: 3258810112

# Material: Calcestruzzo classe C28/35
Calcestruzzo classe C28/35 - Mass Density: 2500; Poisson Ratio: 0.1; Shear Modulus: 1481280000; Thermal Expansion Coefficient: 0.00001; Young Modulus: 3258810112

# Material: Calcestruzzo classe C28/35
Calcestruzzo classe C28/35 - Mass Density: 2500; Poisson Ratio: 0.1; Shear Modulus: 1481280000; Thermal Expansion Coefficient: 0.00001; Young Modulus: 3258810112

# Material: Calcestruzzo classe C28/35
Calcestruzzo classe C28/35 - Mass Density: 2500; Poisson Ratio: 0.1; Shear Modulus: 1481280000; Thermal Expansion Coefficient: 0.00001; Young Modulus: 3258810112

# Material: Calcestruzzo classe C28/35
Calcestruzzo classe C28/35 - Mass Density: 2500; Poisson Ratio: 0.1; Shear Modulus: 1481280000; Thermal Expansion Coefficient: 0.00001; Young Modulus: 3258810112

# Material: Calcestruzzo classe C28/35
Calcestruzzo classe C28/35 - Mass Density: 2500; Poisson Ratio: 0.1; Shear Modulus: 1481280000; Thermal Expansion Coefficient: 0.00001; Young Modulus: 3258810112

# Material: Calcestruzzo classe C28/35
Calcestruzzo classe C28/35 - Mass Density: 2500; Poisson Ratio: 0.1; Shear Modulus: 1481280000; Thermal Expansion Coefficient: 0.00001; Young Modulus: 3258810112

# Material: Calcestruzzo classe C28/35
Calcestruzzo classe C28/35 - Mass Density: 2500; Poisson Ratio: 0.1; Shear Modulus: 1481280000; Thermal Expansion Coefficient: 0.00001; Young Modulus: 3258810112

# Material: Calcestruzzo classe C28/35
Calcestruzzo classe C28/35 - Mass Density: 2500; Poisson Ratio: 0.1; Shear Modulus: 1481280000; Thermal Expansion Coefficient: 0.00001; Young Modulus: 3258810112

# Material: Calcestruzzo classe C28/35
Calcestruzzo classe C28/35 - Mass Density: 2500; Poisson Ratio: 0.1; Shear Modulus: 1481280000; Thermal Expansion Coefficient: 0.00001; Young Modulus: 3258810112

# Material: Calcestruzzo classe C28/35
Calcestruzzo classe C28/35 - Mass Density: 2500; Poisson Ratio: 0.1; Shear Modulus: 1481280000; Thermal Expansion Coefficient: 0.00001; Young Modulus: 3258810112

# Material: Calcestruzzo classe C28/35
Calcestruzzo classe C28/35 - Mass Density: 2500; Poisson Ratio: 0.1; Shear Modulus: 1481280000; Thermal Expansion Coefficient: 0.00001; Young Modulus: 3258810112

# Material: Calcestruzzo classe C28/35
Calcestruzzo classe C28/35 - Mass Density: 2500; Poisson Ratio: 0.1; Shear Modulus: 1481280000; Thermal Expansion Coefficient: 0.00001; Young Modulus: 3258810112

# Material: Calcestruzzo classe C28/35
Calcestruzzo classe C28/35 - Mass Density: 2500; Poisson Ratio: 0.1; Shear Modulus: 1481280000; Thermal Expansion Coefficient: 0.00001; Young Modulus: 3258810112

# Material: Calcestruzzo classe C28/35
Calcestruzzo classe C28/35 - Mass Density: 2500; Poisson Ratio: 0.1; Shear Modulus: 1481280000; Thermal Expansion Coefficient: 0.00001; Young Modulus: 3258810112

# Material: Calcestruzzo classe C28/35
Calcestruzzo classe C28/35 - Mass Density: 2500; Poisson Ratio: 0.1; Shear Modulus: 1481280000; Thermal Expansion Coefficient: 0.00001; Young Modulus: 3258810112

# Material: Calcestruzzo classe C28/35
Calcestruzzo classe C28/35 - Mass Density: 2500; Poisson Ratio: 0.1; Shear Modulus: 1481280000; Thermal Expansion Coefficient: 0.00001; Young Modulus: 3258810112

# Material: Calcestruzzo classe C28/35
Calcestruzzo classe C28/35 - Mass Density: 2500; Poisson Ratio: 0.1; Shear Modulus: 1481280000; Thermal Expansion Coefficient: 0.00001; Young Modulus: 3258810112

# Material: Calcestruzzo classe C28/35
Calcestruzzo classe C28/35 - Mass Density: 2500; Poisson Ratio: 0.1; Shear Modulus: 1481280000; Thermal Expansion Coefficient: 0.00001; Young Modulus: 3258810112

# Material: Calcestruzzo classe C28/35
Calcestruzzo classe C28/35 - Mass Density: 2500; Poisson Ratio: 0.1; Shear Modulus: 1481280000; Thermal Expansion Coefficient: 0.00001; Young Modulus: 3258810112

# Material: Calcestruzzo classe C28/35
Calcestruzzo classe C28/35 - Mass Density: 2500; Poisson Ratio: 0.1; Shear Modulus: 1481280000; Thermal Expansion Coefficient: 0.00001; Young Modulus: 3258810112

# Material: Calcestruzzo classe C28/35
Calcestruzzo classe C28/35 - Mass Density: 2500; Poisson Ratio: 0.1; Shear Modulus: 1481280000; Thermal Expansion Coefficient: 0.00001; Young Modulus: 3258810112

# Material: Calcestruzzo classe C28/35
Calcestruzzo classe C28/35 - Mass Density: 2500; Poisson Ratio: 0.1; Shear Modulus: 1481280000; Thermal Expansion Coefficient: 0.00001; Young Modulus: 3258810112

# Material: Calcestruzzo classe C28/35
Calcestruzzo classe C28/35 - Mass Density: 2500; Poisson Ratio: 0.1; Shear Modulus: 1481280000; Thermal Expansion Coefficient: 0.00001; Young Modulus: 3258810112

# Material: Calcestruzzo classe C28/35
Calcestruzzo classe C28/35 - Mass Density: 2500; Poisson Ratio: 0.1; Shear Modulus: 1481280000; Thermal Expansion Coefficient: 0.00001; Young Modulus: 3258810112

# Material: Calcestruzzo classe C28/35
Calcestruzzo classe C28/35 - Mass Density: 2500; Poisson Ratio: 0.1; Shear Modulus: 1481280000; Thermal Expansion Coefficient: 0.00001; Young Modulus: 3258810112

# Material: Calcestruzzo classe C28/35
Calcestruzzo classe C28/35 - Mass Density: 2500; Poisson Ratio: 0.1; Shear Modulus: 1481280000; Thermal Expansion Coefficient: 0.00001; Young Modulus: 3258810112

# Material: Calcestruzzo classe C28/35
Calcestruzzo classe C28/35 - Mass Density: 2500; Poisson Ratio: 0.1; Shear Modulus: 1481280000; Thermal Expansion Coefficient: 0.00001; Young Modulus: 3258810112

# Material: Calcestruzzo classe C28/35
Calcestruzzo classe C28/35 - Mass Density: 2500; Poisson Ratio: 0.1; Shear Modulus: 1481280000; Thermal Expansion Coefficient: 0.00001; Young Modulus: 3258810112

# Material: Calcestruzzo classe C28/35
Calcestruzzo classe C28/35 - Mass Density: 2500; Poisson Ratio: 0.1; Shear Modulus: 1481280000; Thermal Expansion Coefficient: 0.00001; Young Modulus: 3258810112

# Material: Calcestruzzo classe C28/35
Calcestruzzo classe C28/35 - Mass Density: 2500; Poisson Ratio: 0.1; Shear Modulus: 1481280000; Thermal Expansion Coefficient: 0.00001; Young Modulus: 3258810112

# Material: Calcestruzzo classe C28/35
Calcestruzzo classe C28/35 - Mass Density: 2500; Poisson Ratio: 0.1; Shear Modulus: 1481280000; Thermal Expansion Coefficient: 0.00001; Young Modulus: 3258810112

# Material: Calcestruzzo classe C28/35
Calcestruzzo classe C28/35 - Mass Density: 2500; Poisson Ratio: 0.1; Shear Modulus: 1481280000; Thermal Expansion Coefficient: 0.00001; Young Modulus: 3258810112

# Material: Calcestruzzo classe C28/35
Calcestruzzo classe C28/35 - Mass Density: 2500; Poisson Ratio: 0.1; Shear Modulus: 1481280000; Thermal Expansion Coefficient: 0.00001; Young Modulus: 3258810112

# Material: Calcestruzzo classe C28/35
Calcestruzzo classe C28/35 - Mass Density: 2500; Poisson Ratio: 0.1; Shear Modulus: 1481280000; Thermal Expansion Coefficient: 0.00001; Young Modulus: 3258810112

# Material: Calcestruzzo classe C28/35
Calcestruzzo classe C28/35 - Mass Density: 2500; Poisson Ratio: 0.1; Shear Modulus: 1481280000; Thermal Expansion Coefficient: 0.00001; Young Modulus: 3258810112

# Material: Calcestruzzo classe C28/35
Calcestruzzo classe C28/35 - Mass Density: 2500; Poisson Ratio: 0.1; Shear Modulus: 1481280000; Thermal Expansion Coefficient: 0.00001; Young Modulus: 3258810112

# Material: Calcestruzzo classe C28/35
Calcestruzzo classe C28/35 - Mass Density: 2500; Poisson Ratio: 0.1; Shear Modulus: 1481280000; Thermal Expansion Coefficient: 0.00001; Young Modulus: 3258810112

# Material: Calcestruzzo classe C28/35
Calcestruzzo classe C28/35 - Mass Density: 2500; Poisson Ratio: 0.1; Shear Modulus: 1481280000; Thermal Expansion Coefficient: 0.00001; Young Modulus: 3258810112

# Material: Calcestruzzo classe C28/35
Calcestruzzo classe C28/35 - Mass Density: 2500; Poisson Ratio: 0.1; Shear Modulus: 1481280000; Thermal Expansion Coefficient: 0.00001; Young Modulus: 3258810112

# Material: Calcestruzzo classe C28/35
Calcestruzzo classe C28/35 - Mass Density: 2500; Poisson Ratio: 0.1; Shear Modulus: 1481280000; Thermal Expansion Coefficient: 0.00001; Young Modulus: 3258810112

# Material: Calcestruzzo classe C28/35
Calcestruzzo classe C28/35 - Mass Density: 2500; Poisson Ratio: 0.1; Shear Modulus: 1481280000; Thermal Expansion Coefficient: 0.00001; Young Modulus: 3258810112

# Material: Calcestruzzo classe C28/35
Calcestruzzo classe C28/35 - Mass Density: 2500; Poisson Ratio: 0.1; Shear Modulus: 1481280000; Thermal Expansion Coefficient: 0.00001; Young Modulus: 3258810112

# Material: Calcestruzzo classe C28/35
Calcestruzzo classe C28/35 - Mass Density: 2500; Poisson Ratio: 0.1; Shear Modulus: 1481280000; Thermal Expansion Coefficient: 0.00001; Young Modulus: 3258810112

# Material: Calcestruzzo classe C28/35
Calcestruzzo classe C28/35 - Mass Density: 2500; Poisson Ratio: 0.1; Shear Modulus: 1481280000; Thermal Expansion Coefficient: 0.00001; Young Modulus: 3258810112

# Material: Calcestruzzo classe C28/35
Calcestruzzo classe C28/35 - Mass Density: 2500; Poisson Ratio: 0.1; Shear Modulus: 1481280000; Thermal Expansion Coefficient: 0.00001; Young Modulus: 3258810112

# Material: Calcestruzzo classe C28/35
Calcestruzzo classe C28/35 - Mass Density: 2500; Poisson Ratio: 0.1; Shear Modulus: 1481280000; Thermal Expansion Coefficient: 0.00001; Young Modulus: 3258810112

# Material: Calcestruzzo classe C28/35
Calcestruzzo classe C28/35 - Mass Density: 2500; Poisson Ratio: 0.1; Shear Modulus: 1481280000; Thermal Expansion Coefficient: 0.00001; Young Modulus: 3258810112

# Material: Calcestruzzo classe C28/35
Calcestruzzo classe C28/35 - Mass Density: 2500; Poisson Ratio: 0.1; Shear Modulus: 1481280000; Thermal Expansion Coefficient: 0.00001; Young Modulus: 3258810112

# Material: Calcestruzzo classe C28/35
Calcestruzzo classe C28/35 - Mass Density: 2500; Poisson Ratio: 0.1; Shear Modulus: 1481280000; Thermal Expansion Coefficient: 0.00001; Young Modulus: 3258810112

# Material: Calcestruzzo classe C28/35
Calcestruzzo classe C28/35 - Mass Density: 2500; Poisson Ratio: 0.1; Shear Modulus: 1481280000; Thermal Expansion Coefficient: 0.00001; Young Modulus: 3258810112

# Material: Calcestruzzo classe C28/35
Calcestruzzo classe C28/35 - Mass Density: 2500; Poisson Ratio: 0.1; Shear Modulus: 1481280000; Thermal Expansion Coefficient: 0.00001; Young Modulus: 3258810112

# Material: Calcestruzzo classe C28/35
Calcestruzzo classe C28/35 - Mass Density: 2500; Poisson Ratio: 0.1; Shear Modulus: 1481280000; Thermal Expansion Coefficient: 0.00001; Young Modulus: 3258810112

# Material: Calcestruzzo classe C28/35
Calcestruzzo classe C28/35 - Mass Density: 2500; Poisson Ratio: 0.1; Shear Modulus: 1481280000; Thermal Expansion Coefficient: 0.00001; Young Modulus: 3258810112

# Material: Calcestruzzo classe C28/35
Calcestruzzo classe C28/35 - Mass Density: 2500; Poisson Ratio: 0.1; Shear Modulus: 1481280000; Thermal Expansion Coefficient: 0.00001; Young Modulus: 3258810112

# Material: Calcestruzzo classe C28/35
Calcestruzzo classe C28/35 - Mass Density: 2500; Poisson Ratio: 0.1; Shear Modulus: 1481280000; Thermal Expansion Coefficient: 0.00001; Young Modulus: 3258810112

# Material: Calcestruzzo classe C28/35
Calcestruzzo classe C28/35 - Mass Density: 2500; Poisson Ratio: 0.1; Shear Modulus: 1481280000; Thermal Expansion Coefficient: 0.00001; Young Modulus: 3258810112

# Material: Calcestruzzo classe C28/35
Calcestruzzo classe C28/35 - Mass Density: 2500; Poisson Ratio: 0.1; Shear Modulus: 1481280000; Thermal Expansion Coefficient: 0.00001; Young Modulus: 3258810112

# Material: Calcestruzzo classe C28/35
Calcestruzzo classe C28/35 - Mass Density: 2500; Poisson Ratio: 0.1; Shear Modulus: 1481280000; Thermal Expansion Coefficient: 0.00001; Young Modulus: 3258810112

# Material: Calcestruzzo classe C28/35
Calcestruzzo classe C28/35 - Mass Density: 2500; Poisson Ratio: 0.1; Shear Modulus: 1481280000; Thermal Expansion Coefficient: 0.00001; Young Modulus: 3258810112

# Material: Calcestruzzo classe C28/35
Calcestruzzo classe C28/35 - Mass Density: 2500; Poisson Ratio: 0.1; Shear Modulus: 1481280000; Thermal Expansion Coefficient: 0.00001; Young Modulus: 3258810112

# Material: Calcestruzzo classe C28/35
Calcestruzzo classe C28/35 - Mass Density: 2500; Poisson Ratio: 0.1; Shear Modulus: 1481280000; Thermal Expansion Coefficient: 0.00001; Young Modulus: 3258810112

# Material: Calcestruzzo classe C28/35
Calcestruzzo classe C28/35 - Mass Density: 2500; Poisson Ratio: 0.1; Shear Modulus: 1481280000; Thermal Expansion Coefficient: 0.00001; Young Modulus: 3258810112

# Material: Calcestruzzo classe C28/35
Calcestruzzo classe C28/35 - Mass Density: 2500; Poisson Ratio: 0.1; Shear Modulus: 1481280000; Thermal Expansion Coefficient: 0.00001; Young Modulus: 3258810112

# Material: Calcestruzzo classe C28/35
Calcestruzzo classe C28/35 - Mass Density: 2500; Poisson Ratio: 0.1; Shear Modulus: 1481280000; Thermal Expansion Coefficient: 0.00001; Young Modulus: 3258810112

# Material: Calcestruzzo classe C28/35
Calcestruzzo classe C28/35 - Mass Density: 2500; Poisson Ratio: 0.1; Shear Modulus: 1481280000; Thermal Expansion Coefficient: 0.00001; Young Modulus: 3258810112

# Material: Calcestruzzo classe C28/35
Calcestruzzo classe C28/35 - Mass Density: 2500; Poisson Ratio: 0.1; Shear Modulus: 1481280000; Thermal Expansion Coefficient: 0.00001; Young Modulus: 3258810112

# Material: Calcestruzzo classe C28/35
Calcestruzzo classe C28/35 - Mass Density: 2500; Poisson Ratio: 0.1; Shear Modulus: 1481280000; Thermal Expansion Coefficient: 0.00001; Young Modulus: 3258810112

# Material: Calcestruzzo classe C28/35
Calcestruzzo classe C28/35 - Mass Density: 2500; Poisson Ratio: 0.1; Shear Modulus: 1481280000; Thermal Expansion Coefficient: 0.00001; Young Modulus: 3258810112

# Material: Calcestruzzo classe C28/35
Calcestruzzo classe C28/35 - Mass Density: 2500; Poisson Ratio: 0.1; Shear Modulus: 1481280000; Thermal Expansion Coefficient: 0.00001; Young Modulus: 3258810112

# Material: Calcestruzzo classe C28/35
Calcestruzzo classe C28/35 - Mass Density: 2500; Poisson Ratio: 0.1; Shear Modulus: 1481280000; Thermal Expansion Coefficient: 0.00001; Young Modulus: 3258810112

# Material: Calcestruzzo classe C28/35
Calcestruzzo classe C28/35 - Mass Density: 2500; Poisson Ratio: 0.1; Shear Modulus: 1481280000; Thermal Expansion Coefficient: 0.00001; Young Modulus: 3258810112

# Material: Calcestruzzo classe C28/35
Calcestruzzo classe C28/35 - Mass Density: 2500; Poisson Ratio: 0.1; Shear Modulus: 1481280000; Thermal Expansion Coefficient: 0.00001; Young Modulus: 3258810112

# Material: Calcestruzzo classe C28/35
Calcestruzzo classe C28/35 - Mass Density: 2500; Poisson Ratio: 0.1; Shear Modulus: 1481280000; Thermal Expansion Coefficient: 0.00001; Young Modulus: 3258810112

# Material: Calcestruzzo classe C28/35
Calcestruzzo classe C28/35 - Mass Density: 2500; Poisson Ratio: 0.1; Shear Modulus: 1481280000; Thermal Expansion Coefficient: 0.00001; Young Modulus: 3258810112

# Material: Calcestruzzo classe C28/35
Calcestruzzo classe C28/35 - Mass Density: 2500; Poisson Ratio: 0.1; Shear Modulus: 1481280000; Thermal Expansion Coefficient: 0.00001; Young Modulus: 3258810112

# Material: Calcestruzzo classe C28/35
Calcestruzzo classe C28/35 - Mass Density: 2500; Poisson Ratio: 0.1; Shear Modulus: 1481280000; Thermal Expansion Coefficient: 0.00001; Young Modulus: 3258810112

# Material: Calcestruzzo classe C28/35
Calcestruzzo classe C28/35 - Mass Density: 2500; Poisson Ratio: 0.1; Shear Modulus: 1481280000; Thermal Expansion Coefficient: 0.00001; Young Modulus: 3258810112

# Material: Calcestruzzo classe C28/35
Calcestruzzo classe C28/35 - Mass Density: 2500; Poisson Ratio: 0.1; Shear Modulus: 1481280000; Thermal Expansion Coefficient: 0.00001; Young Modulus: 3258810112

# Material: Calcestruzzo classe C28/35
Calcestruzzo classe C28/35 - Mass Density: 2500; Poisson Ratio: 0.1; Shear Modulus: 1481280000; Thermal Expansion Coefficient: 0.00001; Young Modulus: 3258810112

# Material: Calcestruzzo classe C28/35
Calcestruzzo classe C28/35 - Mass Density: 2500; Poisson Ratio: 0.1; Shear Modulus: 1481280000; Thermal Expansion Coefficient: 0.00001; Young Modulus: 3258810112

# Material: Calcestruzzo classe C28/35
Calcestruzzo classe C28/35 - Mass Density: 2500; Poisson Ratio: 0.1; Shear Modulus: 1481280000; Thermal Expansion Coefficient: 0.00001; Young Modulus: 3258810112

# Material: Calcestruzzo classe C28/35
Calcestruzzo classe C28/35 - Mass Density: 2500; Poisson Ratio: 0.1; Shear Modulus: 1481280000; Thermal Expansion Coefficient: 0.00001; Young Modulus: 3258810112

# Material: Calcestruzzo classe C28/35
Calcestruzzo classe C28/35 - Mass Density: 2500; Poisson Ratio: 0.1; Shear Modulus: 1481280000; Thermal Expansion Coefficient: 0.00001; Young Modulus: 3258810112

# Material: Calcestruzzo classe C28/35
Calcestruzzo classe C28/35 - Mass Density: 2500; Poisson Ratio: 0.1; Shear Modulus: 1481280000; Thermal Expansion Coefficient: 0.00001; Young Modulus: 3258810112

# Material: Calcestruzzo classe C28/35
Calcestruzzo classe C28/35 - Mass Density: 2500; Poisson Ratio: 0.1; Shear Modulus: 1481280000; Thermal Expansion Coefficient: 0.00001; Young Modulus: 3258810112

# Material: Calcestruzzo classe C28/35
Calcestruzzo classe C28/35 - Mass Density: 2500; Poisson Ratio: 0.1; Shear Modulus: 1481280000; Thermal Expansion Coefficient: 0.00001; Young Modulus: 3258810112

# Material: Calcestruzzo classe C28/35
Calcestruzzo classe C28/35 - Mass Density: 2500; Poisson Ratio: 0.1; Shear Modulus: 1481280000; Thermal Expansion Coefficient: 0.00001; Young Modulus: 3258810112

# Material: Calcestruzzo classe C28/35
Calcestruzzo classe C28/35 - Mass Density: 2500; Poisson Ratio: 0.1; Shear Modulus: 1481280000; Thermal Expansion Coefficient: 0.00001; Young Modulus: 3258810112

# Material: Calcestruzzo classe C28/35
Calcestruzzo classe C28/35 - Mass Density: 2500; Poisson Ratio: 0.1; Shear Modulus: 1481280000; Thermal Expansion Coefficient: 0.00001; Young Modulus: 3258810112

# Material: Calcestruzzo classe C28/35
Calcestruzzo classe C28/35 - Mass Density: 2500; Poisson Ratio: 0.1; Shear Modulus: 1481280000; Thermal Expansion Coefficient: 0.00001; Young Modulus: 3258810112

# Material: Calcestruzzo classe C28/35
Calcestruzzo classe C28/35 - Mass Density: 2500; Poisson Ratio: 0.1; Shear Modulus: 1481280000; Thermal Expansion Coefficient: 0.00001; Young Modulus: 3258810112

# Material: Calcestruzzo classe C28/35
Calcestruzzo classe C28/35 - Mass Density: 2500; Poisson Ratio: 0.1; Shear Modulus: 1481280000; Thermal Expansion Coefficient: 0.00001; Young Modulus: 3258810112

# Material: Calcestruzzo classe C28/35
Calcestruzzo classe C28/35 - Mass Density: 2500; Poisson Ratio: 0.1; Shear Modulus: 1481280000; Thermal Expansion Coefficient: 0.00001; Young Modulus: 3258810112

# Material: Calcestruzzo classe C28/35
Calcestruzzo classe C28/35 - Mass Density: 2500; Poisson Ratio: 0.1; Shear Modulus: 1481280000; Thermal Expansion Coefficient: 0.00001; Young Modulus: 3258810112

# Material: Calcestruzzo classe C28/35
Calcestruzzo classe C28/35 - Mass Density: 2500; Poisson Ratio: 0.1; Shear Modulus: 1481280000; Thermal Expansion Coefficient: 0.00001; Young Modulus: 3258810112

# Material: Calcestruzzo classe C28/35
Calcestruzzo classe C28/35 - Mass Density: 2500; Poisson Ratio: 0.1; Shear Modulus: 1481280000; Thermal Expansion Coefficient: 0.00001; Young Modulus: 3258810112

# Material: Calcestruzzo classe C28/35
Calcestruzzo classe C28/35 - Mass Density: 2500; Poisson Ratio: 0.1; Shear Modulus: 1481280000; Thermal Expansion Coefficient: 0.00001; Young Modulus: 3258810112

# Material: Calcestruzzo classe C28/35
Calcestruzzo classe C28/35 - Mass Density: 2500; Poisson Ratio: 0.1; Shear Modulus: 1481280000; Thermal Expansion Coefficient: 0.00001; Young Modulus: 3258810112

# Material: Calcestruzzo classe C28/35
Calcestruzzo classe C28/35 - Mass Density: 2500; Poisson Ratio: 0.1; Shear Modulus: 1481280000; Thermal Expansion Coefficient: 0.00001; Young Modulus: 3258810112

# Material: Calcestruzzo classe C28/35
Calcestruzzo classe C28/35 - Mass Density: 2500; Poisson Ratio: 0.1; Shear Modulus: 1481280000; Thermal Expansion Coefficient: 0.00001; Young Modulus: 3258810112

# Material: Calcestruzzo classe C28/35
Calcestruzzo classe C28/35 - Mass Density: 2500; Poisson Ratio: 0.1; Shear Modulus: 1481280000; Thermal Expansion Coefficient: 0.00001; Young Modulus: 3258810112

# Material: Calcestruzzo classe C28/35
Calcestruzzo classe C28/35 - Mass Density: 2500; Poisson Ratio: 0.1; Shear Modulus: 1481280000; Thermal Expansion Coefficient: 0.00001; Young Modulus: 3258810112

# Material: Calcestruzzo classe C28/35
Calcestruzzo classe C28/35 - Mass Density: 2500; Poisson Ratio: 0.1; Shear Modulus: 1481280000; Thermal Expansion Coefficient: 0.00001; Young Modulus: 3258810112

# Material: Calcestruzzo classe C28/35
Calcestruzzo classe C28/35 - Mass Density: 2500; Poisson Ratio: 0.1; Shear Modulus: 1481280000; Thermal Expansion Coefficient: 0.00001; Young Modulus: 3258810112

# Material: Calcestruzzo classe C28/35
Calcestruzzo classe C28/35 - Mass Density: 2500; Poisson Ratio: 0.1; Shear Modulus: 1481280000; Thermal Expansion Coefficient: 0.00001; Young Modulus: 3258810112

# Material: Calcestruzzo classe C28/35
Calcestruzzo classe C28/35 - Mass Density: 2500; Poisson Ratio: 0.1; Shear Modulus: 1481280000; Thermal Expansion Coefficient: 0.00001; Young Modulus: 3258810112

# Material: Calcestruzzo classe C28/35
Calcestruzzo classe C28/35 - Mass Density: 2500; Poisson Ratio: 0.1; Shear Modulus: 1481280000; Thermal Expansion Coefficient: 0.00001; Young Modulus: 3258810112

# Material: Calcestruzzo classe C28/35
Calcestruzzo classe C28/35 - Mass Density: 2500; Poisson Ratio: 0.1; Shear Modulus: 1481280000; Thermal Expansion Coefficient: 0.00001; Young Modulus: 3258810112

# Material: Calcestruzzo classe C28/35
Calcestruzzo classe C28/35 - Mass Density: 2500; Poisson Ratio: 0.1; Shear Modulus: 1481280000; Thermal Expansion Coefficient: 0.00001; Young Modulus: 3258810112

# Material: Calcestruzzo classe C28/35
Calcestruzzo classe C28/35 - Mass Density: 2500; Poisson Ratio: 0.1; Shear Modulus: 1481280000; Thermal Expansion Coefficient: 0.00001; Young Modulus: 3258810112

# Material: Calcestruzzo classe C28/35
Calcestruzzo classe C28/35 - Mass Density: 2500; Poisson Ratio: 0.1; Shear Modulus: 1481280000; Thermal Expansion Coefficient: 0.00001; Young Modulus: 3258810112

# Material: Calcestruzzo classe C28/35
Calcestruzzo classe C28/35 - Mass Density: 2500; Poisson Ratio: 0.1; Shear Modulus: 1481280000; Thermal Expansion Coefficient: 0.00001; Young Modulus: 3258810112

# Material: Calcestruzzo classe C28/35
Calcestruzzo classe C28/35 - Mass Density: 2500; Poisson Ratio: 0.1; Shear Modulus: 1481280000; Thermal Expansion Coefficient: 0.00001; Young Modulus: 3258810112

# Material: Calcestruzzo classe C28/35
Calcestruzzo classe C28/35 - Mass Density: 2500; Poisson Ratio: 0.1; Shear Modulus: 1481280000; Thermal Expansion Coefficient: 0.00001; Young Modulus: 3258810112

# Material: Calcestruzzo classe C28/35
Calcestruzzo classe C28/35 - Mass Density: 2500; Poisson Ratio: 0.1; Shear Modulus: 1481280000; Thermal Expansion Coefficient: 0.00001; Young Modulus: 3258810112

# Material: Calcestruzzo classe C28/35
Calcestruzzo classe C28/35 - Mass Density: 2500; Poisson Ratio: 0.1; Shear Modulus: 1481280000; Thermal Expansion Coefficient: 0.00001; Young Modulus: 3258810112

# Material: Calcestruzzo classe C28/35
Calcestruzzo classe C28/35 - Mass Density: 2500; Poisson Ratio: 0.1; Shear Modulus: 1481280000; Thermal Expansion Coefficient: 0.00001; Young Modulus: 3258810112

# Material: Calcestruzzo classe C28/35
Calcestruzzo classe C28/35 - Mass Density: 2500; Poisson Ratio: 0.1; Shear Modulus: 1481280000; Thermal Expansion Coefficient: 0.00001; Young Modulus: 3258810112

# Material: Calcestruzzo classe C28/35
Calcestruzzo classe C28/35 - Mass Density: 2500; Poisson Ratio: 0.1; Shear Modulus: 1481280000; Thermal Expansion Coefficient: 0.00001; Young Modulus: 3258810112

# Material: Calcestruzzo classe C28/35
Calcestruzzo classe C28/35 - Mass Density: 2500; Poisson Ratio: 0.1; Shear Modulus: 1481280000; Thermal Expansion Coefficient: 0.00001; Young Modulus: 3258810112

# Material: Calcestruzzo classe C28/35
Calcestruzzo classe C28/35 - Mass Density: 2500; Poisson Ratio: 0.1; Shear Modulus: 1481280000; Thermal Expansion Coefficient: 0.00001; Young Modulus: 3258810112

# Material: Calcestruzzo classe C28/35
Calcestruzzo classe C28/35 - Mass Density: 2500; Poisson Ratio: 0.1; Shear Modulus: 1481280000; Thermal Expansion Coefficient: 0.00001; Young Modulus: 3258810112

# Material: Calcestruzzo classe C28/35
Calcestruzzo classe C28/35 - Mass Density: 2500; Poisson Ratio: 0.1; Shear Modulus: 1481280000; Thermal Expansion Coefficient: 0.00001; Young Modulus: 3258810112

# Material: Calcestruzzo classe C28/35
Calcestruzzo classe C28/35 - Mass Density: 2500; Poisson Ratio: 0.1; Shear Modulus: 1481280000; Thermal Expansion Coefficient: 0.00001; Young Modulus: 3258810112

# Material: Calcestruzzo classe C28/35
Calcestruzzo classe C28/35 - Mass Density: 2500; Poisson Ratio: 0.1; Shear Modulus: 1481280000; Thermal Expansion Coefficient: 0.00001; Young Modulus: 3258810112

# Material: Calcestruzzo classe C28/35
Calcestruzzo classe C28/35 - Mass Density: 2500; Poisson Ratio: 0.1; Shear Modulus: 1481280000; Thermal Expansion Coefficient: 0.00001; Young Modulus: 3258810112

# Material: Calcestruzzo classe C28/35
Calcestruzzo classe C28/35 - Mass Density: 2500; Poisson Ratio: 0.1; Shear Modulus: 1481280000; Thermal Expansion Coefficient: 0.00001; Young Modulus: 3258810112

# Material: Calcestruzzo classe C28/35
Calcestruzzo classe C28/35 - Mass Density: 2500; Poisson Ratio: 0.1; Shear Modulus: 1481280000; Thermal Expansion Coefficient: 0.00001; Young Modulus: 3258810112

# Material: Calcestruzzo classe C28/35
Calcestruzzo classe C28/35 - Mass Density: 2500; Poisson Ratio: 0.1; Shear Modulus: 1481280000; Thermal Expansion Coefficient: 0.00001; Young Modulus: 3258810112

# Material: Calcestruzzo classe C28/35
Calcestruzzo classe C28/35 - Mass Density: 2500; Poisson Ratio: 0.1; Shear Modulus: 1481280000; Thermal Expansion Coefficient: 0.00001; Young Modulus: 3258810112

# Material: Calcestruzzo classe C28/35
Calcestruzzo classe C28/35 - Mass Density: 2500; Poisson Ratio: 0.1; Shear Modulus: 1481280000; Thermal Expansion Coefficient: 0.00001; Young Modulus: 3258810112

# Material: Calcestruzzo classe C28/35
Calcestruzzo classe C28/35 - Mass Density: 2500; Poisson Ratio: 0.1; Shear Modulus: 1481280000; Thermal Expansion Coefficient: 0.00001; Young Modulus: 3258810112

# Material: Calcestruzzo classe C28/35
Calcestruzzo classe C28/35 - Mass Density: 2500; Poisson Ratio: 0.1; Shear Modulus: 1481280000; Thermal Expansion Coefficient: 0.00001; Young Modulus: 3258810112

# Material: Calcestruzzo classe C28/35
Calcestruzzo classe C28/35 - Mass Density: 2500; Poisson Ratio: 0.1; Shear Modulus: 1481280000; Thermal Expansion Coefficient: 0.00001; Young Modulus: 3258810112

# Material: Calcestruzzo classe C28/35
Calcestruzzo classe C28/35 - Mass Density: 2500; Poisson Ratio: 0.1; Shear Modulus: 1481280000; Thermal Expansion Coefficient: 0.00001; Young Modulus: 3258810112

# Material: Calcestruzzo classe C28/35
Calcestruzzo classe C28/35 - Mass Density: 2500; Poisson Ratio: 0.1; Shear Modulus: 1481280000; Thermal Expansion Coefficient: 0.00001; Young Modulus: 3258810112

# Material: Calcestruzzo classe C28/35
Calcestruzzo classe C28/35 - Mass Density: 2500; Poisson Ratio: 0.1; Shear Modulus: 1481280000; Thermal Expansion Coefficient: 0.00001; Young Modulus: 3258810112

# Material: Calcestruzzo classe C28/35
Calcestruzzo classe C28/35 - Mass Density: 2500; Poisson Ratio: 0.1; Shear Modulus: 1481280000; Thermal Expansion Coefficient: 0.00001; Young Modulus: 3258810112

# Material: Calcestruzzo classe C28/35
Calcestruzzo classe C28/35 - Mass Density: 2500; Poisson Ratio: 0.1; Shear Modulus: 1481280000; Thermal Expansion Coefficient: 0.00001; Young Modulus: 3258810112

# Material: Calcestruzzo classe C28/35
Calcestruzzo classe C28/35 - Mass Density: 2500; Poisson Ratio: 0.1; Shear Modulus: 1481280000; Thermal Expansion Coefficient: 0.00001; Young Modulus: 3258810112

# Material: Calcestruzzo classe C28/35
Calcestruzzo classe C28/35 - Mass Density: 2500; Poisson Ratio: 0.1; Shear Modulus: 1481280000; Thermal Expansion Coefficient: 0.00001; Young Modulus: 3258810112

# Material: Calcestruzzo classe C28/35
Calcestruzzo classe C28/35 - Mass Density: 2500; Poisson Ratio: 0.1; Shear Modulus: 1481280000; Thermal Expansion Coefficient: 0.00001; Young Modulus: 3258810112

# Material: Calcestruzzo classe C28/35
Calcestruzzo classe C28/35 - Mass Density: 2500; Poisson Ratio: 0.1; Shear Modulus: 1481280000; Thermal Expansion Coefficient: 0.00001; Young Modulus: 3258810112

# Material: Calcestruzzo classe C28/35
Calcestruzzo classe C28/35 - Mass Density: 2500; Poisson Ratio: 0.1; Shear Modulus: 1481280000; Thermal Expansion Coefficient: 0.00001; Young Modulus: 3258810112

# Material: Calcestruzzo classe C28/35
Calcestruzzo classe C28/35 - Mass Density: 2500; Poisson Ratio: 0.1; Shear Modulus: 1481280000; Thermal Expansion Coefficient: 0.00001; Young Modulus: 3258810112

# Material: Calcestruzzo classe C28/35
Calcestruzzo classe C28/35 - Mass Density: 2500; Poisson Ratio: 0.1; Shear Modulus: 1481280000; Thermal Expansion Coefficient: 0.00001; Young Modulus: 3258810112

# Material: Calcestruzzo classe C28/35
Calcestruzzo classe C28/35 - Mass Density: 2500; Poisson Ratio: 0.1; Shear Modulus: 1481280000; Thermal Expansion Coefficient: 0.00001; Young Modulus: 3258810112

# Material: Calcestruzzo classe C28/35
Calcestruzzo classe C28/35 - Mass Density: 2500; Poisson Ratio: 0.1; Shear Modulus: 1481280000; Thermal Expansion Coefficient: 0.00001; Young Modulus: 3258810112

# Material: Calcestruzzo classe C28/35
Calcestruzzo classe C28/35 - Mass Density: 2500; Poisson Ratio: 0.1; Shear Modulus: 1481280000; Thermal Expansion Coefficient: 0.00001; Young Modulus: 3258810112

# Material: Calcestruzzo classe C28/35
Calcestruzzo classe C28/35 - Mass Density: 2500; Poisson Ratio: 0.1; Shear Modulus: 1481280000; Thermal Expansion Coefficient: 0.00001; Young Modulus: 3258810112
